VERSION 5.8 ;
BUSBITCHARS "[]" ;
DIVIDERCHAR "/" ;
CLEARANCEMEASURE EUCLIDEAN ;

SITE CoreSite
    SIZE 0.4800 BY 3.7800 ;
    CLASS CORE ;
    SYMMETRY Y ;
END CoreSite

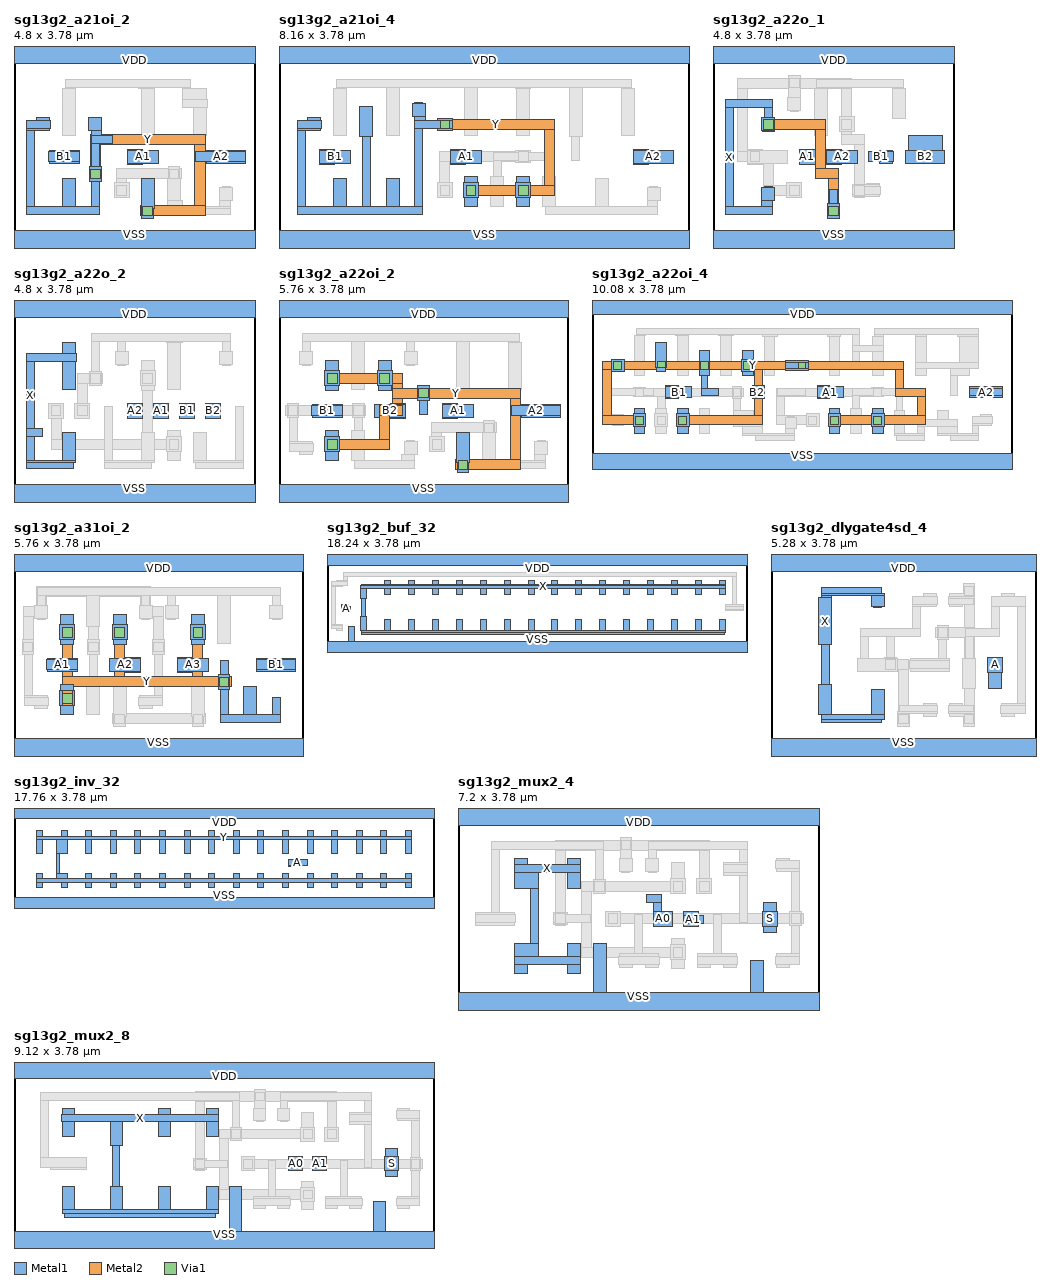
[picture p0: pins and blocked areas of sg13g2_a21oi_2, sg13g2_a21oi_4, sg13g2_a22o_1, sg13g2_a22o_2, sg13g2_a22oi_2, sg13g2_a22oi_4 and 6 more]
MACRO sg13g2_a21oi_2
  CLASS CORE ;
  ORIGIN 0 0 ;
  FOREIGN sg13g2_a21oi_2 0 0 ;
  SIZE 4.8000 BY 3.7800 ;
  SYMMETRY X Y ;
  SITE CoreSite ;
  PIN A1
    DIRECTION INPUT ;
    USE SIGNAL ;
    ANTENNAMODEL OXIDE1 ;
    ANTENNAGATEAREA 0.4836 LAYER Metal1 ;
    PORT
      LAYER Metal1 ;
        RECT 2.2500 1.5500 2.5500 1.5700 ;
        RECT 2.2500 1.5700 2.8700 1.8300 ;
        RECT 2.2500 1.8300 2.5500 1.8500 ;
    END
  END A1
  PIN A2
    DIRECTION INPUT ;
    USE SIGNAL ;
    ANTENNAMODEL OXIDE1 ;
    ANTENNAGATEAREA 0.4836 LAYER Metal1 ;
    PORT
      LAYER Metal1 ;
        RECT 3.8300 1.5700 4.6100 1.6050 ;
        RECT 3.6200 1.6050 4.6100 1.7950 ;
        RECT 3.8300 1.7950 4.6100 1.8300 ;
    END
  END A2
  PIN B1
    DIRECTION INPUT ;
    USE SIGNAL ;
    ANTENNAMODEL OXIDE1 ;
    ANTENNAGATEAREA 0.4836 LAYER Metal1 ;
    PORT
      LAYER Metal1 ;
        RECT 0.7100 1.5700 1.3100 1.6050 ;
        RECT 0.6950 1.6050 1.3100 1.7950 ;
        RECT 0.7100 1.7950 1.3100 1.8300 ;
    END
  END B1
  PIN Y
    DIRECTION OUTPUT ;
    USE SIGNAL ;
    ANTENNAPARTIALMETALAREA 0.19855 LAYER Metal1 ;
    ANTENNADIFFAREA 1.309 LAYER Metal1 ;
    ANTENNADIFFAREA 1.309 LAYER Metal2 ;
    PORT
      LAYER Metal2 ;
        RECT 2.5150 0.5200 3.8000 0.7200 ;
        RECT 1.5200 1.2100 1.7200 1.9450 ;
        RECT 3.6000 0.7200 3.8000 1.9450 ;
        RECT 1.5200 1.9450 3.8000 2.1450 ;
      LAYER Metal1 ;
        RECT 2.5450 0.4750 2.7750 0.6600 ;
        RECT 2.5300 0.6600 2.7900 1.2600 ;
        RECT 0.2400 0.5400 1.7000 0.7000 ;
        RECT 1.5400 0.7000 1.7000 1.2100 ;
        RECT 0.9700 0.7000 1.2300 1.2600 ;
        RECT 1.5050 1.2100 1.7350 1.5000 ;
        RECT 1.5400 1.5000 1.7000 1.9650 ;
        RECT 1.5400 1.9650 1.9600 2.1250 ;
        RECT 0.2400 0.7000 0.4000 2.2100 ;
        RECT 1.5400 2.1250 1.7500 2.2100 ;
        RECT 0.2400 2.2100 0.7100 2.2600 ;
        RECT 0.2400 2.2600 0.7250 2.4200 ;
        RECT 0.4500 2.4200 0.7100 2.4700 ;
        RECT 1.4900 2.2100 1.7500 2.4700 ;
        RECT 1.5400 2.4700 1.7000 2.4850 ;
      LAYER Via1 ;
        RECT 2.5650 0.5250 2.7550 0.7150 ;
        RECT 1.5250 1.2600 1.7150 1.4500 ;
    END
  END Y
  PIN VDD
    DIRECTION INOUT ;
    USE POWER ;
    SHAPE ABUTMENT ;
    PORT
      LAYER Metal1 ;
        RECT 0.0000 3.5600 4.8000 4.0000 ;
    END
  END VDD
  PIN VSS
    DIRECTION INOUT ;
    USE GROUND ;
    SHAPE ABUTMENT ;
    PORT
      LAYER Metal1 ;
        RECT 0.0000 -0.2200 4.8000 0.2200 ;
    END
  END VSS
  OBS
    LAYER Metal2 ;
      RECT 2.0400 0.8850 2.2400 1.2550 ;
      RECT 2.0400 1.2550 3.3250 1.4550 ;
    LAYER Metal1 ;
      RECT 1.9900 0.8800 2.2900 1.1800 ;
      RECT 3.1000 0.5400 4.3000 0.6600 ;
      RECT 3.0500 0.6600 4.3000 0.7000 ;
      RECT 3.0500 0.7000 3.3600 0.8300 ;
      RECT 4.0900 0.7000 4.3000 0.8300 ;
      RECT 4.0900 0.8300 4.3500 1.0900 ;
      RECT 4.1400 1.0900 4.3000 1.1050 ;
      RECT 3.0500 0.8300 3.3100 1.2600 ;
      RECT 3.0650 1.2600 3.2950 1.5000 ;
      RECT 3.5700 2.1100 3.8300 2.6700 ;
      RECT 3.3600 2.6700 3.8450 2.8300 ;
      RECT 0.9700 2.1100 1.2300 3.0500 ;
      RECT 2.5300 2.1100 2.7900 3.0500 ;
      RECT 3.3600 2.8300 3.8300 3.0500 ;
      RECT 1.0200 3.0500 1.2300 3.0800 ;
      RECT 2.4800 3.0500 2.7900 3.0800 ;
      RECT 3.3600 3.0500 3.5200 3.0800 ;
      RECT 1.0200 3.0800 3.5200 3.2400 ;
    LAYER Via1 ;
      RECT 2.0450 0.9350 2.2350 1.1250 ;
      RECT 3.0850 1.2600 3.2750 1.4500 ;
  END
END sg13g2_a21oi_2

MACRO sg13g2_a21oi_4
  CLASS CORE ;
  ORIGIN 0 0 ;
  FOREIGN sg13g2_a21oi_4 0 0 ;
  SIZE 8.1600 BY 3.7800 ;
  SYMMETRY X Y ;
  SITE CoreSite ;
  PIN A1
    DIRECTION INPUT ;
    USE SIGNAL ;
    ANTENNAMODEL OXIDE1 ;
    ANTENNAGATEAREA 0.9672 LAYER Metal1 ;
    PORT
      LAYER Metal1 ;
        RECT 3.4100 1.5500 3.7100 1.5700 ;
        RECT 3.4100 1.5700 4.0300 1.8300 ;
        RECT 3.4100 1.8300 3.7100 1.8500 ;
    END
  END A1
  PIN A2
    DIRECTION INPUT ;
    USE SIGNAL ;
    ANTENNAMODEL OXIDE1 ;
    ANTENNAGATEAREA 0.9672 LAYER Metal1 ;
    PORT
      LAYER Metal1 ;
        RECT 7.0500 1.5500 7.3500 1.5700 ;
        RECT 7.0500 1.5700 7.8500 1.8300 ;
        RECT 7.0500 1.8300 7.3500 1.8500 ;
    END
  END A2
  PIN B1
    DIRECTION INPUT ;
    USE SIGNAL ;
    ANTENNAMODEL OXIDE1 ;
    ANTENNAGATEAREA 0.9672 LAYER Metal1 ;
    PORT
      LAYER Metal1 ;
        RECT 0.8100 1.5500 1.1100 1.5700 ;
        RECT 0.8100 1.5700 1.4300 1.8300 ;
        RECT 0.8100 1.8300 1.1100 1.8500 ;
    END
  END B1
  PIN Y
    DIRECTION OUTPUT ;
    USE SIGNAL ;
    ANTENNAPARTIALMETALAREA 2.0692 LAYER Metal1 ;
    ANTENNADIFFAREA 2.323 LAYER Metal1 ;
    ANTENNADIFFAREA 2.323 LAYER Metal2 ;
    PORT
      LAYER Metal2 ;
        RECT 3.6750 0.9300 5.4800 1.1300 ;
        RECT 5.2800 1.1300 5.4800 2.2400 ;
        RECT 3.1550 2.2400 5.4800 2.4400 ;
      LAYER Metal1 ;
        RECT 3.6900 0.7100 3.9500 0.8800 ;
        RECT 3.6700 0.8800 3.9700 1.1800 ;
        RECT 3.6900 1.1800 3.9500 1.3100 ;
        RECT 4.7300 0.7100 4.9900 0.8800 ;
        RECT 4.7100 0.8800 5.0100 1.1800 ;
        RECT 4.7300 1.1800 4.9900 1.3100 ;
        RECT 0.3600 0.5400 2.8600 0.7000 ;
        RECT 1.0900 0.7000 1.3500 1.2600 ;
        RECT 2.1300 0.7000 2.3900 1.2600 ;
        RECT 1.6600 0.7000 1.8200 2.0900 ;
        RECT 0.3600 0.7000 0.5200 2.2100 ;
        RECT 0.3600 2.2100 0.8300 2.2600 ;
        RECT 2.7000 0.7000 2.8600 2.2600 ;
        RECT 3.1550 2.2250 3.4450 2.2600 ;
        RECT 0.3600 2.2600 0.8450 2.4200 ;
        RECT 2.7000 2.2600 3.4450 2.4200 ;
        RECT 3.1550 2.4200 3.4450 2.4550 ;
        RECT 0.5700 2.4200 0.8300 2.4700 ;
        RECT 2.7000 2.4200 2.9100 2.5000 ;
        RECT 1.6100 2.0900 1.8700 2.6900 ;
        RECT 2.6500 2.5000 2.9100 2.7600 ;
        RECT 2.7000 2.7600 2.8600 2.7750 ;
      LAYER Via1 ;
        RECT 3.7250 0.9350 3.9150 1.1250 ;
        RECT 4.7650 0.9350 4.9550 1.1250 ;
        RECT 3.2050 2.2450 3.3950 2.4350 ;
    END
  END Y
  PIN VDD
    DIRECTION INOUT ;
    USE POWER ;
    SHAPE ABUTMENT ;
    PORT
      LAYER Metal1 ;
        RECT 0.0000 3.5600 8.1600 4.0000 ;
    END
  END VDD
  PIN VSS
    DIRECTION INOUT ;
    USE GROUND ;
    SHAPE ABUTMENT ;
    PORT
      LAYER Metal1 ;
        RECT 0.0000 -0.2200 8.1600 0.2200 ;
    END
  END VSS
  OBS
    LAYER Metal2 ;
      RECT 3.2000 0.8850 3.4000 1.6000 ;
      RECT 3.2000 1.6000 5.0050 1.8000 ;
    LAYER Metal1 ;
      RECT 3.1500 0.8800 3.4500 1.1800 ;
      RECT 5.3000 0.5400 7.5400 0.7000 ;
      RECT 5.3000 0.7000 5.5100 0.7100 ;
      RECT 7.3300 0.7000 7.5400 0.8300 ;
      RECT 7.3300 0.8300 7.5900 1.0900 ;
      RECT 7.3800 1.0900 7.5400 1.1050 ;
      RECT 6.2900 0.7000 6.5500 1.2600 ;
      RECT 4.2100 0.7100 4.4700 1.3100 ;
      RECT 5.2500 0.7100 5.5100 1.3100 ;
      RECT 4.2600 1.3100 4.4200 1.6200 ;
      RECT 4.7150 1.5850 5.0050 1.6200 ;
      RECT 5.3000 1.3100 5.4600 1.6200 ;
      RECT 4.2600 1.6200 5.4600 1.7800 ;
      RECT 4.7150 1.7800 5.0050 1.8150 ;
      RECT 5.8200 1.6200 5.9800 2.0900 ;
      RECT 1.0900 2.1100 1.3500 3.0500 ;
      RECT 4.7300 2.1100 4.9900 3.0500 ;
      RECT 6.8100 2.1100 7.0700 3.0500 ;
      RECT 1.1400 3.0500 1.3500 3.0800 ;
      RECT 2.1300 2.1100 2.3900 3.0800 ;
      RECT 3.6900 2.1100 3.9500 3.0800 ;
      RECT 4.7150 3.0500 5.0050 3.0800 ;
      RECT 5.7700 2.0900 6.0300 3.0800 ;
      RECT 6.8100 3.0500 7.0200 3.0800 ;
      RECT 1.1400 3.0800 7.0200 3.2400 ;
    LAYER Via1 ;
      RECT 3.2050 0.9350 3.3950 1.1250 ;
      RECT 4.7650 1.6050 4.9550 1.7950 ;
  END
END sg13g2_a21oi_4

MACRO sg13g2_a22o_1
  CLASS CORE ;
  ORIGIN 0 0 ;
  FOREIGN sg13g2_a22o_1 0 0 ;
  SIZE 4.8000 BY 3.7800 ;
  SYMMETRY X Y ;
  SITE CoreSite ;
  PIN A1
    DIRECTION INPUT ;
    USE SIGNAL ;
    ANTENNAMODEL OXIDE1 ;
    ANTENNAGATEAREA 0.2418 LAYER Metal1 ;
    PORT
      LAYER Metal1 ;
        RECT 1.7300 1.5500 2.0300 1.8500 ;
    END
  END A1
  PIN A2
    DIRECTION INPUT ;
    USE SIGNAL ;
    ANTENNAMODEL OXIDE1 ;
    ANTENNAGATEAREA 0.2418 LAYER Metal1 ;
    PORT
      LAYER Metal1 ;
        RECT 2.2500 1.5500 2.5500 1.5700 ;
        RECT 2.2500 1.5700 2.8700 1.8300 ;
        RECT 2.2500 1.8300 2.5500 1.8500 ;
    END
  END A2
  PIN B1
    DIRECTION INPUT ;
    USE SIGNAL ;
    ANTENNAMODEL OXIDE1 ;
    ANTENNAGATEAREA 0.2418 LAYER Metal1 ;
    PORT
      LAYER Metal1 ;
        RECT 3.3100 1.5700 3.5700 1.6050 ;
        RECT 3.1000 1.6050 3.5850 1.7950 ;
        RECT 3.3100 1.7950 3.5700 1.8300 ;
    END
  END B1
  PIN B2
    DIRECTION INPUT ;
    USE SIGNAL ;
    ANTENNAMODEL OXIDE1 ;
    ANTENNAGATEAREA 0.2418 LAYER Metal1 ;
    PORT
      LAYER Metal1 ;
        RECT 3.8800 1.5550 4.0400 1.5700 ;
        RECT 3.8300 1.5700 4.6100 1.8300 ;
        RECT 3.8800 1.8300 4.5600 2.1250 ;
    END
  END B2
  PIN X
    DIRECTION OUTPUT ;
    USE SIGNAL ;
    ANTENNAPARTIALMETALAREA 0.8174 LAYER Metal1 ;
    ANTENNADIFFAREA 0.6102 LAYER Metal1 ;
    ANTENNADIFFAREA 0.6102 LAYER Metal2 ;
    PORT
      LAYER Metal2 ;
        RECT 2.3000 0.4750 2.5000 1.2550 ;
        RECT 2.0400 1.2550 2.5000 1.4550 ;
        RECT 2.0400 1.4550 2.2400 2.2400 ;
        RECT 0.9550 2.2400 2.2400 2.4400 ;
      LAYER Metal1 ;
        RECT 2.2850 0.4750 2.5150 0.7650 ;
        RECT 2.3200 0.7650 2.4800 1.0400 ;
        RECT 0.2400 0.5400 1.1800 0.7000 ;
        RECT 0.9700 0.7000 1.1800 0.8300 ;
        RECT 0.9700 0.8300 1.2300 1.0900 ;
        RECT 1.0200 1.0900 1.1800 1.1050 ;
        RECT 0.9850 2.1950 1.2150 2.2100 ;
        RECT 0.9700 2.2100 1.2300 2.4700 ;
        RECT 0.9850 2.4700 1.2150 2.4850 ;
        RECT 0.2400 0.7000 0.4000 2.6700 ;
        RECT 1.0200 2.4850 1.1800 2.6700 ;
        RECT 0.2400 2.6700 1.1800 2.8300 ;
      LAYER Via1 ;
        RECT 2.3050 0.5250 2.4950 0.7150 ;
        RECT 1.0050 2.2450 1.1950 2.4350 ;
    END
  END X
  PIN VDD
    DIRECTION INOUT ;
    USE POWER ;
    SHAPE ABUTMENT ;
    PORT
      LAYER Metal1 ;
        RECT 0.0000 3.5600 4.8000 4.0000 ;
    END
  END VDD
  PIN VSS
    DIRECTION INOUT ;
    USE GROUND ;
    SHAPE ABUTMENT ;
    PORT
      LAYER Metal1 ;
        RECT 0.0000 -0.2200 4.8000 0.2200 ;
    END
  END VSS
  OBS
    LAYER Metal2 ;
      RECT 1.0000 0.9300 1.7650 1.1300 ;
      RECT 1.0000 1.1300 1.2000 1.6000 ;
      RECT 0.4800 1.6000 1.2000 1.8000 ;
      RECT 2.8200 0.8850 3.0200 1.9450 ;
      RECT 2.5600 1.9450 3.0200 2.1450 ;
      RECT 0.4800 1.8000 0.6800 3.0600 ;
      RECT 2.5600 2.1450 2.7600 3.0600 ;
      RECT 0.4800 3.0600 2.7600 3.2600 ;
    LAYER Metal1 ;
      RECT 3.0500 0.9000 3.3100 0.9150 ;
      RECT 2.7750 0.9150 3.3100 0.9500 ;
      RECT 2.7750 0.9500 3.3250 1.1100 ;
      RECT 2.7750 1.1100 3.3100 1.1450 ;
      RECT 3.0500 1.1450 3.3100 1.1600 ;
      RECT 1.4700 0.8800 1.7700 1.1800 ;
      RECT 0.6900 1.5500 0.9900 1.5700 ;
      RECT 0.6900 1.5700 1.4900 1.8300 ;
      RECT 0.6900 1.8300 0.9900 1.8500 ;
      RECT 2.5100 2.1900 2.8100 2.4900 ;
      RECT 1.5400 2.6050 1.7000 2.6200 ;
      RECT 1.4900 2.6200 1.7500 2.8800 ;
      RECT 1.5050 2.8800 1.7350 3.3050 ;
      RECT 2.0100 2.1100 2.2700 3.0500 ;
      RECT 3.5700 2.4500 3.8300 3.0500 ;
      RECT 2.0600 3.0500 2.3200 3.0800 ;
      RECT 3.5700 3.0500 3.7800 3.0800 ;
      RECT 2.0600 3.0800 3.7800 3.2400 ;
    LAYER Via1 ;
      RECT 1.5250 0.9350 1.7150 1.1250 ;
      RECT 2.8250 0.9350 3.0150 1.1250 ;
      RECT 0.7450 1.6050 0.9350 1.7950 ;
      RECT 2.5650 2.2450 2.7550 2.4350 ;
      RECT 1.5250 3.0650 1.7150 3.2550 ;
  END
END sg13g2_a22o_1

MACRO sg13g2_a22o_2
  CLASS CORE ;
  ORIGIN 0 0 ;
  FOREIGN sg13g2_a22o_2 0 0 ;
  SIZE 4.8000 BY 3.7800 ;
  SYMMETRY X Y ;
  SITE CoreSite ;
  PIN A1
    DIRECTION INPUT ;
    USE SIGNAL ;
    ANTENNAMODEL OXIDE1 ;
    ANTENNAGATEAREA 0.2418 LAYER Metal1 ;
    PORT
      LAYER Metal1 ;
        RECT 2.7700 1.5500 3.0700 1.8500 ;
    END
  END A1
  PIN A2
    DIRECTION INPUT ;
    USE SIGNAL ;
    ANTENNAMODEL OXIDE1 ;
    ANTENNAGATEAREA 0.2418 LAYER Metal1 ;
    PORT
      LAYER Metal1 ;
        RECT 2.2500 1.5500 2.5500 1.8500 ;
    END
  END A2
  PIN B1
    DIRECTION INPUT ;
    USE SIGNAL ;
    ANTENNAMODEL OXIDE1 ;
    ANTENNAGATEAREA 0.2418 LAYER Metal1 ;
    PORT
      LAYER Metal1 ;
        RECT 3.2900 1.5500 3.5900 1.8500 ;
    END
  END B1
  PIN B2
    DIRECTION INPUT ;
    USE SIGNAL ;
    ANTENNAMODEL OXIDE1 ;
    ANTENNAGATEAREA 0.2418 LAYER Metal1 ;
    PORT
      LAYER Metal1 ;
        RECT 3.8100 1.5500 4.1100 1.8500 ;
    END
  END B2
  PIN X
    DIRECTION OUTPUT ;
    USE SIGNAL ;
    ANTENNADIFFAREA 0.7254 LAYER Metal1 ;
    PORT
      LAYER Metal1 ;
        RECT 0.2400 0.5400 1.1800 0.6600 ;
        RECT 0.2400 0.6600 1.2300 0.7000 ;
        RECT 0.2400 0.7000 0.4000 1.1800 ;
        RECT 0.9700 0.7000 1.2300 1.2600 ;
        RECT 0.2400 1.1800 0.5600 1.3400 ;
        RECT 0.2400 1.3400 0.4000 2.6700 ;
        RECT 0.9700 2.1100 1.2300 2.6700 ;
        RECT 0.2400 2.6700 1.2450 2.8300 ;
        RECT 0.9700 2.8300 1.2300 3.0500 ;
    END
  END X
  PIN VDD
    DIRECTION INOUT ;
    USE POWER ;
    SHAPE ABUTMENT ;
    PORT
      LAYER Metal1 ;
        RECT 0.0000 3.5600 4.8000 4.0000 ;
    END
  END VDD
  PIN VSS
    DIRECTION INOUT ;
    USE GROUND ;
    SHAPE ABUTMENT ;
    PORT
      LAYER Metal1 ;
        RECT 0.0000 -0.2200 4.8000 0.2200 ;
    END
  END VSS
  OBS
    LAYER Metal2 ;
      RECT 0.7400 0.9300 3.3250 1.1300 ;
      RECT 0.7400 1.1300 0.9400 1.8450 ;
      RECT 2.5600 1.1300 2.7600 2.4850 ;
      RECT 1.2600 1.5550 1.4600 2.2400 ;
      RECT 1.2600 2.2400 1.7650 2.4400 ;
    LAYER Metal1 ;
      RECT 3.0500 0.7100 3.3100 0.8800 ;
      RECT 3.0300 0.8800 3.3300 1.1800 ;
      RECT 3.0500 1.1800 3.3100 1.3100 ;
      RECT 0.6900 1.5500 0.9900 1.8500 ;
      RECT 2.5300 2.0900 2.7900 2.1900 ;
      RECT 2.5100 2.1900 2.8100 2.4900 ;
      RECT 2.5300 2.4900 2.7900 2.6900 ;
      RECT 1.8000 0.5400 2.7400 0.6600 ;
      RECT 1.8000 0.6600 2.7900 0.7000 ;
      RECT 2.5300 0.7000 2.7900 1.2600 ;
      RECT 1.8000 0.7000 1.9600 1.7800 ;
      RECT 3.6200 0.5400 4.5600 0.6600 ;
      RECT 3.5700 0.6600 4.5600 0.7000 ;
      RECT 3.5700 0.7000 3.8300 1.2600 ;
      RECT 4.4000 0.7000 4.5600 1.7800 ;
      RECT 1.2100 1.5500 1.5100 1.8500 ;
      RECT 1.5050 2.1950 1.7350 2.4850 ;
      RECT 2.0600 2.6050 2.2200 2.6200 ;
      RECT 4.1400 2.6050 4.3000 2.6200 ;
      RECT 2.0100 2.6200 2.2700 2.8800 ;
      RECT 4.0900 2.6200 4.3500 2.8800 ;
      RECT 3.0500 2.1100 3.3100 3.0500 ;
      RECT 1.5400 2.4850 1.7000 3.0800 ;
      RECT 2.0600 2.8800 2.2200 3.0800 ;
      RECT 3.0350 3.0500 3.3600 3.0800 ;
      RECT 4.1400 2.8800 4.3000 3.0800 ;
      RECT 1.5400 3.0800 4.3000 3.2400 ;
    LAYER Via1 ;
      RECT 3.0850 0.9350 3.2750 1.1250 ;
      RECT 0.7450 1.6050 0.9350 1.7950 ;
      RECT 2.5650 2.2450 2.7550 2.4350 ;
      RECT 1.2650 1.6050 1.4550 1.7950 ;
      RECT 1.5250 2.2450 1.7150 2.4350 ;
  END
END sg13g2_a22o_2

MACRO sg13g2_a22oi_2
  CLASS CORE ;
  ORIGIN 0 0 ;
  FOREIGN sg13g2_a22oi_2 0 0 ;
  SIZE 5.7600 BY 3.7800 ;
  SYMMETRY X Y ;
  SITE CoreSite ;
  PIN A1
    DIRECTION INPUT ;
    USE SIGNAL ;
    ANTENNAMODEL OXIDE1 ;
    ANTENNAGATEAREA 0.4836 LAYER Metal1 ;
    PORT
      LAYER Metal1 ;
        RECT 3.2500 1.5500 3.5500 1.5700 ;
        RECT 3.2500 1.5700 3.8700 1.8300 ;
        RECT 3.2500 1.8300 3.5500 1.8500 ;
    END
  END A1
  PIN A2
    DIRECTION INPUT ;
    USE SIGNAL ;
    ANTENNAMODEL OXIDE1 ;
    ANTENNAGATEAREA 0.4836 LAYER Metal1 ;
    PORT
      LAYER Metal1 ;
        RECT 4.8300 1.5700 5.6100 1.6050 ;
        RECT 4.6200 1.6050 5.6100 1.7950 ;
        RECT 4.8300 1.7950 5.6100 1.8300 ;
    END
  END A2
  PIN B1
    DIRECTION INPUT ;
    USE SIGNAL ;
    ANTENNAMODEL OXIDE1 ;
    ANTENNAGATEAREA 0.4836 LAYER Metal1 ;
    PORT
      LAYER Metal1 ;
        RECT 0.6700 1.5700 1.2700 1.6050 ;
        RECT 0.6550 1.6050 1.2700 1.7950 ;
        RECT 0.6700 1.7950 1.2700 1.8300 ;
    END
  END B1
  PIN B2
    DIRECTION INPUT ;
    USE SIGNAL ;
    ANTENNAMODEL OXIDE1 ;
    ANTENNAGATEAREA 0.4836 LAYER Metal1 ;
    PORT
      LAYER Metal1 ;
        RECT 2.2100 1.5500 2.5100 1.5700 ;
        RECT 1.8900 1.5700 2.5100 1.8300 ;
        RECT 2.2100 1.8300 2.5100 1.8500 ;
    END
  END B2
  PIN Y
    DIRECTION OUTPUT ;
    USE SIGNAL ;
    ANTENNAPARTIALMETALAREA 0.70255 LAYER Metal1 ;
    ANTENNADIFFAREA 1.4508 LAYER Metal1 ;
    ANTENNADIFFAREA 1.4508 LAYER Metal2 ;
    PORT
      LAYER Metal2 ;
        RECT 3.5150 0.5200 4.8000 0.7200 ;
        RECT 0.9150 0.9300 2.2000 1.1300 ;
        RECT 2.0000 1.1300 2.2000 1.6000 ;
        RECT 2.0000 1.6000 2.4600 1.8000 ;
        RECT 2.2600 1.8000 2.4600 1.9450 ;
        RECT 4.6000 0.7200 4.8000 1.9450 ;
        RECT 2.2600 1.9450 4.8000 2.1450 ;
        RECT 2.2600 2.1450 2.4600 2.2400 ;
        RECT 0.9150 2.2400 2.4600 2.4400 ;
      LAYER Metal1 ;
        RECT 3.5450 0.4750 3.7750 0.6600 ;
        RECT 3.5300 0.6600 3.7900 1.2600 ;
        RECT 0.9300 0.7100 1.1900 0.8800 ;
        RECT 0.9100 0.8800 1.2100 1.1800 ;
        RECT 0.9300 1.1800 1.1900 1.3100 ;
        RECT 2.8000 1.6200 2.9600 1.9000 ;
        RECT 2.7650 1.9000 2.9950 2.1900 ;
        RECT 0.9300 2.0900 1.1900 2.1900 ;
        RECT 0.9100 2.1900 1.2100 2.4900 ;
        RECT 0.9300 2.4900 1.1900 2.6900 ;
        RECT 1.9700 2.0900 2.2300 2.1900 ;
        RECT 1.9500 2.1900 2.2500 2.4900 ;
        RECT 1.9700 2.4900 2.2300 2.6900 ;
      LAYER Via1 ;
        RECT 3.5650 0.5250 3.7550 0.7150 ;
        RECT 0.9650 0.9350 1.1550 1.1250 ;
        RECT 2.7850 1.9500 2.9750 2.1400 ;
        RECT 0.9650 2.2450 1.1550 2.4350 ;
        RECT 2.0050 2.2450 2.1950 2.4350 ;
    END
  END Y
  PIN VDD
    DIRECTION INOUT ;
    USE POWER ;
    SHAPE ABUTMENT ;
    PORT
      LAYER Metal1 ;
        RECT 0.0000 3.5600 5.7600 4.0000 ;
    END
  END VDD
  PIN VSS
    DIRECTION INOUT ;
    USE GROUND ;
    SHAPE ABUTMENT ;
    PORT
      LAYER Metal1 ;
        RECT 0.0000 -0.2200 5.7600 0.2200 ;
    END
  END VSS
  OBS
    LAYER Metal2 ;
      RECT 0.1350 1.6000 1.7250 1.8000 ;
      RECT 3.0400 0.8850 3.2400 1.2550 ;
      RECT 3.0400 1.2550 4.3250 1.4550 ;
    LAYER Metal1 ;
      RECT 0.4100 0.8300 0.6700 0.8800 ;
      RECT 0.2000 0.8800 0.6850 1.0400 ;
      RECT 0.2000 1.0400 0.6700 1.0900 ;
      RECT 0.2000 1.0900 0.3600 1.5550 ;
      RECT 0.1650 1.5550 0.3950 1.8450 ;
      RECT 1.5000 0.5400 2.7000 0.7000 ;
      RECT 1.5000 0.7000 1.7100 0.7100 ;
      RECT 2.4400 0.7000 2.7000 0.8300 ;
      RECT 2.4900 0.8300 2.7500 1.0900 ;
      RECT 2.5400 1.0900 2.7000 1.1050 ;
      RECT 1.4500 0.7100 1.7100 1.3100 ;
      RECT 1.5000 1.3100 1.6600 1.5550 ;
      RECT 1.4650 1.5550 1.6950 1.8450 ;
      RECT 2.9900 0.8800 3.2900 1.1800 ;
      RECT 4.1000 0.5400 5.3000 0.6600 ;
      RECT 4.0500 0.6600 5.3000 0.7000 ;
      RECT 5.0900 0.7000 5.3000 0.8300 ;
      RECT 5.0900 0.8300 5.3500 1.0900 ;
      RECT 5.1400 1.0900 5.3000 1.1050 ;
      RECT 4.0500 0.7000 4.3100 1.2600 ;
      RECT 4.0650 1.2600 4.2950 1.5000 ;
      RECT 0.4600 2.6050 0.6200 2.6200 ;
      RECT 2.5400 2.6050 2.7000 2.6200 ;
      RECT 0.4100 2.6200 0.6700 2.8800 ;
      RECT 2.4900 2.6200 2.7500 2.8800 ;
      RECT 4.5700 2.1100 4.8300 3.0500 ;
      RECT 0.4600 2.8800 0.6200 3.0800 ;
      RECT 1.4500 2.1100 1.7100 3.0800 ;
      RECT 2.5400 2.8800 2.7000 3.0800 ;
      RECT 3.5300 2.1100 3.7900 3.0800 ;
      RECT 4.5700 3.0500 4.7800 3.0800 ;
      RECT 0.4600 3.0800 4.7800 3.2400 ;
    LAYER Via1 ;
      RECT 0.1850 1.6050 0.3750 1.7950 ;
      RECT 1.4850 1.6050 1.6750 1.7950 ;
      RECT 3.0450 0.9350 3.2350 1.1250 ;
      RECT 4.0850 1.2600 4.2750 1.4500 ;
  END
END sg13g2_a22oi_2

MACRO sg13g2_a22oi_4
  CLASS CORE ;
  ORIGIN 0 0 ;
  FOREIGN sg13g2_a22oi_4 0 0 ;
  SIZE 10.0800 BY 3.7800 ;
  SYMMETRY X Y ;
  SITE CoreSite ;
  PIN A1
    DIRECTION INPUT ;
    USE SIGNAL ;
    ANTENNAMODEL OXIDE1 ;
    ANTENNAGATEAREA 0.9672 LAYER Metal1 ;
    PORT
      LAYER Metal1 ;
        RECT 5.4100 1.5500 5.7100 1.5700 ;
        RECT 5.4100 1.5700 6.0300 1.8300 ;
        RECT 5.4100 1.8300 5.7100 1.8500 ;
    END
  END A1
  PIN A2
    DIRECTION INPUT ;
    USE SIGNAL ;
    ANTENNAMODEL OXIDE1 ;
    ANTENNAGATEAREA 0.9672 LAYER Metal1 ;
    PORT
      LAYER Metal1 ;
        RECT 9.0700 1.5700 9.8500 1.6200 ;
        RECT 9.0550 1.6200 9.8500 1.7800 ;
        RECT 9.0700 1.7800 9.8500 1.8300 ;
    END
  END A2
  PIN B1
    DIRECTION INPUT ;
    USE SIGNAL ;
    ANTENNAMODEL OXIDE1 ;
    ANTENNAGATEAREA 0.9672 LAYER Metal1 ;
    PORT
      LAYER Metal1 ;
        RECT 1.7700 1.5500 2.0700 1.5700 ;
        RECT 1.7700 1.5700 2.3900 1.8300 ;
        RECT 1.7700 1.8300 2.0700 1.8500 ;
    END
  END B1
  PIN B2
    DIRECTION INPUT ;
    USE SIGNAL ;
    ANTENNAMODEL OXIDE1 ;
    ANTENNAGATEAREA 0.9672 LAYER Metal1 ;
    PORT
      LAYER Metal1 ;
        RECT 3.8500 1.5500 4.1500 1.6200 ;
        RECT 3.7800 1.6200 4.1500 1.7800 ;
        RECT 3.8500 1.7800 4.1500 1.8500 ;
    END
  END B2
  PIN Y
    DIRECTION OUTPUT ;
    USE SIGNAL ;
    ANTENNAPARTIALMETALAREA 1.2434 LAYER Metal1 ;
    ANTENNADIFFAREA 3.1966 LAYER Metal1 ;
    ANTENNADIFFAREA 3.1966 LAYER Metal2 ;
    PORT
      LAYER Metal2 ;
        RECT 0.2600 0.9300 1.2850 1.1300 ;
        RECT 2.0350 0.9300 4.1000 1.1300 ;
        RECT 5.6750 0.9300 8.0000 1.1300 ;
        RECT 7.8000 1.1300 8.0000 1.6000 ;
        RECT 7.2800 1.6000 8.0000 1.8000 ;
        RECT 0.2600 1.1300 0.4600 2.2400 ;
        RECT 3.9000 1.1300 4.1000 2.2400 ;
        RECT 7.2800 1.8000 7.4800 2.2400 ;
        RECT 0.2600 2.2400 7.4800 2.4400 ;
      LAYER Metal1 ;
        RECT 1.0100 0.7100 1.2700 0.8800 ;
        RECT 0.9900 0.8800 1.2900 1.1800 ;
        RECT 1.0100 1.1800 1.2700 1.3100 ;
        RECT 2.0500 0.7100 2.3100 0.8800 ;
        RECT 2.0300 0.8800 2.3300 1.1800 ;
        RECT 2.0500 1.1800 2.3100 1.3100 ;
        RECT 5.6900 0.7100 5.9500 0.8800 ;
        RECT 5.6700 0.8800 5.9700 1.1800 ;
        RECT 5.6900 1.1800 5.9500 1.3100 ;
        RECT 6.7300 0.7100 6.9900 0.8800 ;
        RECT 6.7100 0.8800 7.0100 1.1800 ;
        RECT 6.7300 1.1800 6.9900 1.3100 ;
        RECT 4.6500 2.2100 4.9100 2.2250 ;
        RECT 4.6500 2.2250 5.1850 2.2600 ;
        RECT 4.6350 2.2600 5.1850 2.4200 ;
        RECT 4.6500 2.4200 5.1850 2.4550 ;
        RECT 4.6500 2.4550 4.9100 2.4700 ;
        RECT 0.4700 2.1900 0.7700 2.4900 ;
        RECT 2.6200 1.6200 3.0400 1.7800 ;
        RECT 2.6200 1.7800 2.7800 2.0900 ;
        RECT 2.5700 2.0900 2.8300 2.6900 ;
        RECT 3.6100 2.0900 3.8700 2.1900 ;
        RECT 3.5900 2.1900 3.8900 2.4900 ;
        RECT 3.6100 2.4900 3.8700 2.6900 ;
        RECT 1.5450 2.1950 1.7750 2.3000 ;
        RECT 1.5300 2.3000 1.7900 2.9000 ;
      LAYER Via1 ;
        RECT 1.0450 0.9350 1.2350 1.1250 ;
        RECT 2.0850 0.9350 2.2750 1.1250 ;
        RECT 5.7250 0.9350 5.9150 1.1250 ;
        RECT 6.7650 0.9350 6.9550 1.1250 ;
        RECT 0.5250 2.2450 0.7150 2.4350 ;
        RECT 1.5650 2.2450 1.7550 2.4350 ;
        RECT 2.6050 2.2450 2.7950 2.4350 ;
        RECT 3.6450 2.2450 3.8350 2.4350 ;
        RECT 4.9450 2.2450 5.1350 2.4350 ;
    END
  END Y
  PIN VDD
    DIRECTION INOUT ;
    USE POWER ;
    SHAPE ABUTMENT ;
    PORT
      LAYER Metal1 ;
        RECT 0.0000 3.5600 10.0800 4.0000 ;
    END
  END VDD
  PIN VSS
    DIRECTION INOUT ;
    USE GROUND ;
    SHAPE ABUTMENT ;
    PORT
      LAYER Metal1 ;
        RECT 0.0000 -0.2200 10.0800 0.2200 ;
    END
  END VSS
  OBS
    LAYER Metal2 ;
      RECT 4.4200 0.9300 5.4450 1.1300 ;
      RECT 4.4200 1.1300 4.6200 1.6000 ;
      RECT 4.4200 1.6000 7.0050 1.8000 ;
      RECT 1.5600 0.8850 1.7600 1.6000 ;
      RECT 0.9950 1.6000 3.6250 1.8000 ;
    LAYER Metal1 ;
      RECT 5.1500 0.8800 5.4500 1.1800 ;
      RECT 7.3000 0.5400 7.9800 0.6600 ;
      RECT 8.6000 0.5400 9.2800 0.6600 ;
      RECT 7.2500 0.6600 7.9800 0.7000 ;
      RECT 8.2900 0.6600 9.2800 0.7000 ;
      RECT 7.8200 0.7000 7.9800 0.8800 ;
      RECT 8.2900 0.7000 8.7600 0.8800 ;
      RECT 9.1200 0.7000 9.2800 0.9000 ;
      RECT 9.1200 0.9000 9.5900 0.9500 ;
      RECT 7.8200 0.8800 8.7600 1.0400 ;
      RECT 9.1200 0.9500 9.6050 1.1100 ;
      RECT 9.3300 1.1100 9.5900 1.1600 ;
      RECT 7.2500 0.7000 7.5100 1.2600 ;
      RECT 8.2900 1.0400 8.5500 1.2600 ;
      RECT 6.2100 0.7100 6.4700 1.3100 ;
      RECT 6.2600 1.3100 6.4200 1.6200 ;
      RECT 6.7150 1.5850 7.0050 1.6200 ;
      RECT 7.3000 1.2600 7.4600 1.6200 ;
      RECT 6.2600 1.6200 7.4600 1.7800 ;
      RECT 6.7150 1.7800 7.0050 1.8150 ;
      RECT 1.5300 0.7100 1.7900 0.8800 ;
      RECT 1.5100 0.8800 1.8100 1.1800 ;
      RECT 1.5300 1.1800 1.7900 1.3100 ;
      RECT 0.4900 0.9000 0.7500 0.9500 ;
      RECT 0.2800 0.9500 0.7650 1.1100 ;
      RECT 0.2800 1.1100 0.7500 1.1600 ;
      RECT 0.2800 1.1600 0.4400 1.6200 ;
      RECT 0.9950 1.5850 1.2850 1.6200 ;
      RECT 0.2800 1.6200 1.4800 1.7800 ;
      RECT 0.9950 1.7800 1.2850 1.8150 ;
      RECT 3.9200 0.5400 4.8600 0.6600 ;
      RECT 3.6100 0.6600 4.8600 0.7000 ;
      RECT 4.6350 0.7000 4.8600 0.8300 ;
      RECT 3.6100 0.7000 4.0800 0.8800 ;
      RECT 2.5700 0.7100 2.8300 0.9500 ;
      RECT 3.4000 0.8800 4.0800 0.9500 ;
      RECT 2.5550 0.9500 4.0800 1.0400 ;
      RECT 4.6500 0.8300 4.9100 1.0900 ;
      RECT 4.7000 1.0900 4.8600 1.1050 ;
      RECT 2.5550 1.0400 3.8700 1.1100 ;
      RECT 3.4000 1.1100 3.8700 1.2600 ;
      RECT 2.5700 1.1100 2.8300 1.3100 ;
      RECT 3.4000 1.2600 3.5600 1.5550 ;
      RECT 3.3650 1.5550 3.5950 1.8450 ;
      RECT 4.4400 1.6200 5.1200 1.7800 ;
      RECT 8.6000 1.6200 8.7600 2.0900 ;
      RECT 5.6900 2.0900 5.9500 2.2600 ;
      RECT 7.7700 2.0900 8.0300 2.2600 ;
      RECT 8.6000 2.0900 9.0700 2.2600 ;
      RECT 5.6750 2.2600 6.4200 2.4200 ;
      RECT 7.7550 2.2600 9.2800 2.4200 ;
      RECT 6.2600 2.4200 6.4200 2.6700 ;
      RECT 6.7300 2.0900 6.9900 2.6700 ;
      RECT 6.2600 2.6700 6.9900 2.8300 ;
      RECT 4.1300 2.0900 4.3900 3.0300 ;
      RECT 5.6900 2.4200 5.9500 3.0300 ;
      RECT 6.7300 2.8300 6.9900 3.0300 ;
      RECT 7.7700 2.4200 8.0300 3.0300 ;
      RECT 8.8100 2.4200 9.2800 3.0300 ;
      RECT 1.0100 2.1100 1.2700 3.0500 ;
      RECT 2.0500 2.1100 2.3100 3.0500 ;
      RECT 3.0900 2.1100 3.3500 3.0500 ;
      RECT 1.0600 3.0500 1.2850 3.0800 ;
      RECT 2.0000 3.0500 2.3250 3.0800 ;
      RECT 3.0400 3.0500 3.4000 3.0800 ;
      RECT 4.0800 3.0300 4.4400 3.0800 ;
      RECT 5.6400 3.0300 5.9650 3.0800 ;
      RECT 6.2600 2.8300 6.4200 3.0800 ;
      RECT 6.7800 3.0300 7.0050 3.0800 ;
      RECT 7.7550 3.0300 8.0300 3.0800 ;
      RECT 8.7600 3.0300 9.2800 3.0800 ;
      RECT 1.0600 3.0800 6.4200 3.2400 ;
      RECT 6.7800 3.0800 9.2800 3.2400 ;
    LAYER Via1 ;
      RECT 5.2050 0.9350 5.3950 1.1250 ;
      RECT 6.7650 1.6050 6.9550 1.7950 ;
      RECT 1.5650 0.9350 1.7550 1.1250 ;
      RECT 1.0450 1.6050 1.2350 1.7950 ;
      RECT 3.3850 1.6050 3.5750 1.7950 ;
  END
END sg13g2_a22oi_4

MACRO sg13g2_a31oi_2
  CLASS CORE ;
  ORIGIN 0 0 ;
  FOREIGN sg13g2_a31oi_2 0 0 ;
  SIZE 5.7600 BY 3.7800 ;
  SYMMETRY X Y ;
  SITE CoreSite ;
  PIN A1
    DIRECTION INPUT ;
    USE SIGNAL ;
    ANTENNAMODEL OXIDE1 ;
    ANTENNAGATEAREA 0.4836 LAYER Metal1 ;
    PORT
      LAYER Metal1 ;
        RECT 0.6700 1.5700 1.2700 1.6050 ;
        RECT 0.6550 1.6050 1.2700 1.7950 ;
        RECT 0.6700 1.7950 1.2700 1.8300 ;
    END
  END A1
  PIN A2
    DIRECTION INPUT ;
    USE SIGNAL ;
    ANTENNAMODEL OXIDE1 ;
    ANTENNAGATEAREA 0.4836 LAYER Metal1 ;
    PORT
      LAYER Metal1 ;
        RECT 2.2100 1.5500 2.5100 1.5700 ;
        RECT 1.8900 1.5700 2.5100 1.8300 ;
        RECT 2.2100 1.8300 2.5100 1.8500 ;
    END
  END A2
  PIN A3
    DIRECTION INPUT ;
    USE SIGNAL ;
    ANTENNAMODEL OXIDE1 ;
    ANTENNAGATEAREA 0.4836 LAYER Metal1 ;
    PORT
      LAYER Metal1 ;
        RECT 3.2500 1.5500 3.5500 1.5700 ;
        RECT 3.2500 1.5700 3.8700 1.8300 ;
        RECT 3.2500 1.8300 3.5500 1.8500 ;
    END
  END A3
  PIN B1
    DIRECTION INPUT ;
    USE SIGNAL ;
    ANTENNAMODEL OXIDE1 ;
    ANTENNAGATEAREA 0.4836 LAYER Metal1 ;
    PORT
      LAYER Metal1 ;
        RECT 4.8300 1.5700 5.6100 1.6050 ;
        RECT 4.8150 1.6050 5.6100 1.7950 ;
        RECT 4.8300 1.7950 5.6100 1.8300 ;
    END
  END B1
  PIN Y
    DIRECTION OUTPUT ;
    USE SIGNAL ;
    ANTENNAPARTIALMETALAREA 0.672 LAYER Metal1 ;
    ANTENNADIFFAREA 1.8876 LAYER Metal1 ;
    ANTENNADIFFAREA 1.8876 LAYER Metal2 ;
    PORT
      LAYER Metal2 ;
        RECT 0.9600 0.8850 1.1600 1.2550 ;
        RECT 0.9600 1.2550 4.3250 1.4550 ;
        RECT 0.9600 1.4550 1.1600 2.4850 ;
        RECT 2.0000 1.4550 2.2000 2.4850 ;
        RECT 3.5600 1.4550 3.7600 2.4850 ;
      LAYER Metal1 ;
        RECT 0.9300 0.7100 1.1900 0.8800 ;
        RECT 0.9100 0.8800 1.2100 1.1800 ;
        RECT 0.9300 1.1800 1.1900 1.3100 ;
        RECT 4.1000 0.5400 5.3000 0.7000 ;
        RECT 5.1400 0.7000 5.3000 1.0400 ;
        RECT 4.1000 0.7000 4.2600 1.2100 ;
        RECT 4.5700 0.7000 4.8300 1.2600 ;
        RECT 4.0650 1.2100 4.2950 1.5000 ;
        RECT 4.1000 1.5000 4.2600 1.7800 ;
        RECT 0.9300 2.0900 1.1900 2.1900 ;
        RECT 0.9100 2.1900 1.2100 2.4900 ;
        RECT 0.9300 2.4900 1.1900 2.6900 ;
        RECT 1.9700 2.0900 2.2300 2.1900 ;
        RECT 1.9500 2.1900 2.2500 2.4900 ;
        RECT 1.9700 2.4900 2.2300 2.6900 ;
        RECT 3.5300 2.0900 3.7900 2.1900 ;
        RECT 3.5100 2.1900 3.8100 2.4900 ;
        RECT 3.5300 2.4900 3.7900 2.6900 ;
      LAYER Via1 ;
        RECT 0.9650 0.9350 1.1550 1.1250 ;
        RECT 4.0850 1.2600 4.2750 1.4500 ;
        RECT 0.9650 2.2450 1.1550 2.4350 ;
        RECT 2.0050 2.2450 2.1950 2.4350 ;
        RECT 3.5650 2.2450 3.7550 2.4350 ;
    END
  END Y
  PIN VDD
    DIRECTION INOUT ;
    USE POWER ;
    SHAPE ABUTMENT ;
    PORT
      LAYER Metal1 ;
        RECT 0.0000 3.5600 5.7600 4.0000 ;
    END
  END VDD
  PIN VSS
    DIRECTION INOUT ;
    USE GROUND ;
    SHAPE ABUTMENT ;
    PORT
      LAYER Metal1 ;
        RECT 0.0000 -0.2200 5.7600 0.2200 ;
    END
  END VSS
  OBS
    LAYER Metal2 ;
      RECT 1.9550 0.5200 3.8050 0.7200 ;
      RECT 0.1800 1.9000 0.3800 2.6500 ;
      RECT 2.7800 1.9000 2.9800 2.6500 ;
      RECT 0.1800 2.6500 0.6400 2.8500 ;
      RECT 2.5200 2.6500 2.9800 2.8500 ;
      RECT 0.4400 2.8500 0.6400 3.0600 ;
      RECT 1.4800 1.9000 1.6800 3.0600 ;
      RECT 2.5200 2.8500 2.7200 3.0600 ;
      RECT 0.4400 3.0600 2.7200 3.2600 ;
    LAYER Metal1 ;
      RECT 1.9850 0.4750 2.2150 0.6600 ;
      RECT 1.9700 0.6600 2.2300 1.2600 ;
      RECT 3.5450 0.4750 3.7750 0.6600 ;
      RECT 3.5300 0.6600 3.7900 1.2600 ;
      RECT 0.4100 0.8300 0.6700 0.8800 ;
      RECT 0.2000 0.8800 0.6850 1.0400 ;
      RECT 0.2000 1.0400 0.6700 1.0900 ;
      RECT 0.2000 1.0900 0.3600 1.9000 ;
      RECT 0.1650 1.9000 0.3950 2.1900 ;
      RECT 1.4500 0.7100 1.7100 1.3100 ;
      RECT 1.5000 1.3100 1.6600 1.9000 ;
      RECT 1.4650 1.9000 1.6950 2.1900 ;
      RECT 2.4900 0.8300 2.7500 0.8800 ;
      RECT 2.4750 0.8800 2.9600 1.0400 ;
      RECT 2.4900 1.0400 2.9600 1.0900 ;
      RECT 2.8000 1.0900 2.9600 1.9000 ;
      RECT 2.7650 1.9000 2.9950 2.1900 ;
      RECT 0.4600 2.6050 0.6200 2.6200 ;
      RECT 2.5400 2.6050 2.7000 2.6200 ;
      RECT 3.0600 2.6050 3.2200 2.6200 ;
      RECT 5.1400 2.6050 5.3000 2.6200 ;
      RECT 0.4100 2.6200 0.6700 2.8800 ;
      RECT 2.4900 2.6200 2.7500 2.8800 ;
      RECT 3.0100 2.6200 3.2700 2.8800 ;
      RECT 5.0900 2.6200 5.3500 2.8800 ;
      RECT 0.4600 2.8800 0.6200 3.0800 ;
      RECT 1.4500 2.4500 1.7100 3.0800 ;
      RECT 2.5400 2.8800 2.7000 3.0800 ;
      RECT 3.0600 2.8800 3.2200 3.0800 ;
      RECT 4.0500 2.1100 4.3100 3.0800 ;
      RECT 5.1400 2.8800 5.3000 3.0800 ;
      RECT 0.4600 3.0800 5.3000 3.2400 ;
    LAYER Via1 ;
      RECT 2.0050 0.5250 2.1950 0.7150 ;
      RECT 3.5650 0.5250 3.7550 0.7150 ;
      RECT 0.1850 1.9500 0.3750 2.1400 ;
      RECT 1.4850 1.9500 1.6750 2.1400 ;
      RECT 2.7850 1.9500 2.9750 2.1400 ;
  END
END sg13g2_a31oi_2

MACRO sg13g2_buf_32
  CLASS CORE ;
  ORIGIN 0 0 ;
  FOREIGN sg13g2_buf_32 0 0 ;
  SIZE 18.2400 BY 3.7800 ;
  SYMMETRY X Y ;
  SITE CoreSite ;
  PIN A
    DIRECTION INPUT ;
    USE SIGNAL ;
    ANTENNAMODEL OXIDE1 ;
    ANTENNAGATEAREA 0.1807 LAYER Metal1 ;
    PORT
      LAYER Metal1 ;
        RECT 0.6500 1.5500 0.9500 1.6000 ;
        RECT 0.6500 1.6000 1.0400 1.7600 ;
        RECT 0.6500 1.7600 0.9500 1.8500 ;
    END
  END A
  PIN X
    DIRECTION OUTPUT ;
    USE SIGNAL ;
    ANTENNADIFFAREA 11.6064 LAYER Metal1 ;
    PORT
      LAYER Metal1 ;
        RECT 1.5000 0.5400 17.2600 0.6100 ;
        RECT 1.5000 0.6100 17.3100 0.7000 ;
        RECT 1.5000 0.7000 1.7100 0.7100 ;
        RECT 2.4900 0.7000 2.7500 1.2100 ;
        RECT 3.5300 0.7000 3.7900 1.2100 ;
        RECT 4.5700 0.7000 4.8300 1.2100 ;
        RECT 5.6100 0.7000 5.8700 1.2100 ;
        RECT 6.6500 0.7000 6.9100 1.2100 ;
        RECT 7.6900 0.7000 7.9500 1.2100 ;
        RECT 8.7300 0.7000 8.9900 1.2100 ;
        RECT 9.7700 0.7000 10.0300 1.2100 ;
        RECT 10.8100 0.7000 11.0700 1.2100 ;
        RECT 11.8500 0.7000 12.1100 1.2100 ;
        RECT 12.8900 0.7000 13.1500 1.2100 ;
        RECT 13.9300 0.7000 14.1900 1.2100 ;
        RECT 14.9700 0.7000 15.2300 1.2100 ;
        RECT 16.0100 0.7000 16.2700 1.2100 ;
        RECT 17.0500 0.7000 17.3100 1.2100 ;
        RECT 1.4500 0.7100 1.7100 1.3100 ;
        RECT 1.5000 1.3100 1.6600 2.0900 ;
        RECT 1.4500 2.0900 1.7100 2.5500 ;
        RECT 2.4900 2.3000 2.7500 2.5500 ;
        RECT 3.5300 2.3000 3.7900 2.5500 ;
        RECT 4.5700 2.3000 4.8300 2.5500 ;
        RECT 5.6100 2.3000 5.8700 2.5500 ;
        RECT 6.6500 2.3000 6.9100 2.5500 ;
        RECT 7.6900 2.3000 7.9500 2.5500 ;
        RECT 8.7300 2.3000 8.9900 2.5500 ;
        RECT 9.7700 2.3000 10.0300 2.5500 ;
        RECT 10.8100 2.3000 11.0700 2.5500 ;
        RECT 11.8500 2.3000 12.1100 2.5500 ;
        RECT 12.8900 2.3000 13.1500 2.5500 ;
        RECT 13.9300 2.3000 14.1900 2.5500 ;
        RECT 14.9700 2.3000 15.2300 2.5500 ;
        RECT 16.0100 2.3000 16.2700 2.5500 ;
        RECT 17.0500 2.3000 17.3100 2.5500 ;
        RECT 1.4500 2.5500 17.3250 2.6900 ;
        RECT 1.5000 2.6900 17.3250 2.7100 ;
        RECT 2.4900 2.7100 2.7500 2.9000 ;
        RECT 3.5300 2.7100 3.7900 2.9000 ;
        RECT 4.5700 2.7100 4.8300 2.9000 ;
        RECT 5.6100 2.7100 5.8700 2.9000 ;
        RECT 6.6500 2.7100 6.9100 2.9000 ;
        RECT 7.6900 2.7100 7.9500 2.9000 ;
        RECT 8.7300 2.7100 8.9900 2.9000 ;
        RECT 9.7700 2.7100 10.0300 2.9000 ;
        RECT 10.8100 2.7100 11.0700 2.9000 ;
        RECT 11.8500 2.7100 12.1100 2.9000 ;
        RECT 12.8900 2.7100 13.1500 2.9000 ;
        RECT 13.9300 2.7100 14.1900 2.9000 ;
        RECT 14.9700 2.7100 15.2300 2.9000 ;
        RECT 16.0100 2.7100 16.2700 2.9000 ;
        RECT 17.0500 2.7100 17.3100 2.9000 ;
    END
  END X
  PIN VDD
    DIRECTION INOUT ;
    USE POWER ;
    SHAPE ABUTMENT ;
    PORT
      LAYER Metal1 ;
        RECT 0.0000 3.5600 18.2400 4.0000 ;
    END
  END VDD
  PIN VSS
    DIRECTION INOUT ;
    USE GROUND ;
    SHAPE ABUTMENT ;
    PORT
      LAYER Metal1 ;
        RECT 0.0000 -0.2200 18.2400 0.2200 ;
        RECT 0.9300 0.2200 1.1900 0.8700 ;
    END
  END VSS
  OBS
    LAYER Metal1 ;
      RECT 0.4100 0.7350 0.6700 0.7850 ;
      RECT 0.2000 0.7850 0.6850 0.9450 ;
      RECT 0.2000 0.9450 0.6700 0.9950 ;
      RECT 17.3100 1.5700 18.0900 1.6200 ;
      RECT 17.2950 1.6200 18.0900 1.7800 ;
      RECT 17.3100 1.7800 18.0900 1.8300 ;
      RECT 0.2000 0.9950 0.3600 2.6400 ;
      RECT 0.2000 2.6400 0.6700 2.6900 ;
      RECT 0.2000 2.6900 0.8800 2.8500 ;
      RECT 0.4100 2.8500 0.8800 2.9000 ;
      RECT 0.7200 2.9000 0.8800 3.0800 ;
      RECT 17.6200 1.8300 17.7800 3.0800 ;
      RECT 0.7200 3.0800 17.7800 3.2400 ;
  END
END sg13g2_buf_32

MACRO sg13g2_dlygate4sd_4
  CLASS CORE ;
  ORIGIN 0 0 ;
  FOREIGN sg13g2_dlygate4sd_4 0 0 ;
  SIZE 5.2800 BY 3.7800 ;
  SYMMETRY X Y ;
  SITE CoreSite ;
  PIN A
    DIRECTION INPUT ;
    USE SIGNAL ;
    ANTENNAMODEL OXIDE1 ;
    ANTENNAGATEAREA 0.1092 LAYER Metal1 ;
    PORT
      LAYER Metal1 ;
        RECT 4.3300 1.2300 4.5900 1.5500 ;
        RECT 4.3100 1.5500 4.6100 1.8500 ;
    END
  END A
  PIN X
    DIRECTION OUTPUT ;
    USE SIGNAL ;
    ANTENNADIFFAREA 1.4508 LAYER Metal1 ;
    PORT
      LAYER Metal1 ;
        RECT 1.0000 0.5400 2.2000 0.6100 ;
        RECT 1.0000 0.6100 2.2500 0.7000 ;
        RECT 1.0000 0.7000 1.2100 0.7100 ;
        RECT 1.9900 0.7000 2.2500 1.2100 ;
        RECT 0.9500 0.7100 1.2100 1.3100 ;
        RECT 1.0000 1.3100 1.1600 2.0900 ;
        RECT 2.0400 2.8350 2.2000 2.8500 ;
        RECT 0.9500 2.0900 1.2100 3.0300 ;
        RECT 1.0000 3.0300 1.2100 3.0800 ;
        RECT 1.9900 2.8500 2.2500 3.0800 ;
        RECT 1.0000 3.0800 2.2500 3.1100 ;
        RECT 1.0000 3.1100 2.2000 3.2400 ;
    END
  END X
  PIN VDD
    DIRECTION INOUT ;
    USE POWER ;
    SHAPE ABUTMENT ;
    PORT
      LAYER Metal1 ;
        RECT 0.0000 3.5600 5.2800 4.0000 ;
    END
  END VDD
  PIN VSS
    DIRECTION INOUT ;
    USE GROUND ;
    SHAPE ABUTMENT ;
    PORT
      LAYER Metal1 ;
        RECT 0.0000 -0.2200 5.2800 0.2200 ;
    END
  END VSS
  OBS
    LAYER Metal2 ;
      RECT 2.5400 0.4750 2.7400 1.6000 ;
      RECT 2.2350 1.6000 2.7400 1.8000 ;
      RECT 3.8400 0.4750 4.0400 2.2400 ;
      RECT 3.2750 2.2400 4.0400 2.4400 ;
      RECT 3.8400 2.4400 4.0400 3.3050 ;
    LAYER Metal1 ;
      RECT 2.5250 0.4750 2.7550 0.7200 ;
      RECT 3.0300 0.6700 3.2900 0.7200 ;
      RECT 2.5250 0.7200 3.3050 0.7650 ;
      RECT 2.5600 0.7650 3.3050 0.8800 ;
      RECT 3.0300 0.8800 3.2900 0.9300 ;
      RECT 1.7800 1.5550 1.9400 1.5700 ;
      RECT 2.2650 1.5550 2.4950 1.5700 ;
      RECT 1.7300 1.5700 2.5100 1.8300 ;
      RECT 2.2650 1.8300 2.4950 1.8450 ;
      RECT 1.7800 1.8300 1.9400 2.2600 ;
      RECT 2.3000 1.8450 2.4600 2.2600 ;
      RECT 1.7800 2.2600 2.9800 2.4200 ;
      RECT 2.8200 2.4200 2.9800 2.8500 ;
      RECT 2.8200 2.8500 3.2900 2.9000 ;
      RECT 2.8200 2.9000 3.3050 3.0600 ;
      RECT 3.0300 3.0600 3.2900 3.1100 ;
      RECT 3.8250 0.4750 4.0550 0.6700 ;
      RECT 3.5500 0.6700 4.0550 0.7200 ;
      RECT 3.5350 0.7200 4.0550 0.7650 ;
      RECT 3.5350 0.7650 4.0200 0.8800 ;
      RECT 3.5500 0.8800 3.8100 0.9300 ;
      RECT 2.7700 1.5700 3.5500 1.6200 ;
      RECT 2.7550 1.6200 3.5500 1.7800 ;
      RECT 2.7700 1.7800 3.5500 1.8300 ;
      RECT 3.3400 1.8300 3.5000 2.1950 ;
      RECT 3.3050 2.1950 3.5350 2.4850 ;
      RECT 3.5500 2.8500 3.8100 2.9000 ;
      RECT 3.5350 2.9000 4.0200 3.0150 ;
      RECT 3.5350 3.0150 4.0550 3.0600 ;
      RECT 3.5500 3.0600 4.0550 3.1100 ;
      RECT 3.8250 3.1100 4.0550 3.3050 ;
      RECT 4.5900 0.6700 4.8500 0.7200 ;
      RECT 4.5750 0.7200 5.0600 0.8800 ;
      RECT 4.5900 0.8800 5.0600 0.9300 ;
      RECT 3.8100 1.2300 4.0700 1.8300 ;
      RECT 3.8600 1.8300 4.0200 2.2600 ;
      RECT 3.8600 2.2600 4.5400 2.4200 ;
      RECT 4.3800 2.4200 4.5400 2.8500 ;
      RECT 4.9000 0.9300 5.0600 2.8500 ;
      RECT 4.3800 2.8500 5.0600 3.0600 ;
      RECT 4.5900 3.0600 4.8500 3.1100 ;
    LAYER Via1 ;
      RECT 2.5450 0.5250 2.7350 0.7150 ;
      RECT 2.2850 1.6050 2.4750 1.7950 ;
      RECT 3.8450 0.5250 4.0350 0.7150 ;
      RECT 3.3250 2.2450 3.5150 2.4350 ;
      RECT 3.8450 3.0650 4.0350 3.2550 ;
  END
END sg13g2_dlygate4sd_4

MACRO sg13g2_inv_32
  CLASS CORE ;
  ORIGIN 0 0 ;
  FOREIGN sg13g2_inv_32 0 0 ;
  SIZE 17.7600 BY 3.7800 ;
  SYMMETRY X Y ;
  SITE CoreSite ;
  PIN A
    DIRECTION INPUT ;
    USE SIGNAL ;
    ANTENNAMODEL OXIDE1 ;
    ANTENNAGATEAREA 7.7376 LAYER Metal1 ;
    PORT
      LAYER Metal1 ;
        RECT 11.5900 1.5500 11.8900 1.5700 ;
        RECT 11.5900 1.5700 12.3900 1.8300 ;
        RECT 11.5900 1.8300 11.8900 1.8500 ;
    END
  END A
  PIN Y
    DIRECTION OUTPUT ;
    USE SIGNAL ;
    ANTENNADIFFAREA 11.6064 LAYER Metal1 ;
    PORT
      LAYER Metal1 ;
        RECT 0.9500 0.6600 1.2100 0.8800 ;
        RECT 1.9900 0.6600 2.2500 0.8800 ;
        RECT 3.0300 0.6600 3.2900 0.8800 ;
        RECT 4.0700 0.6600 4.3300 0.8800 ;
        RECT 5.1100 0.6600 5.3700 0.8800 ;
        RECT 6.1500 0.6600 6.4100 0.8800 ;
        RECT 7.1900 0.6600 7.4500 0.8800 ;
        RECT 8.2300 0.6600 8.4900 0.8800 ;
        RECT 9.2700 0.6600 9.5300 0.8800 ;
        RECT 10.3100 0.6600 10.5700 0.8800 ;
        RECT 11.3500 0.6600 11.6100 0.8800 ;
        RECT 12.3900 0.6600 12.6500 0.8800 ;
        RECT 13.4300 0.6600 13.6900 0.8800 ;
        RECT 14.4700 0.6600 14.7300 0.8800 ;
        RECT 15.5100 0.6600 15.7700 0.8800 ;
        RECT 16.5500 0.6600 16.8100 0.8800 ;
        RECT 0.9350 0.8800 16.8250 1.0400 ;
        RECT 0.9500 1.0400 1.2100 1.2600 ;
        RECT 1.7800 1.0400 2.2500 1.2600 ;
        RECT 3.0300 1.0400 3.2900 1.2600 ;
        RECT 4.0700 1.0400 4.3300 1.2600 ;
        RECT 5.1100 1.0400 5.3700 1.2600 ;
        RECT 6.1500 1.0400 6.4100 1.2600 ;
        RECT 7.1900 1.0400 7.4500 1.2600 ;
        RECT 8.2300 1.0400 8.4900 1.2600 ;
        RECT 9.2700 1.0400 9.5300 1.2600 ;
        RECT 10.3100 1.0400 10.5700 1.2600 ;
        RECT 11.3500 1.0400 11.6100 1.2600 ;
        RECT 12.3900 1.0400 12.6500 1.2600 ;
        RECT 13.4300 1.0400 13.6900 1.2600 ;
        RECT 14.4700 1.0400 14.7300 1.2600 ;
        RECT 15.5100 1.0400 15.7700 1.2600 ;
        RECT 16.5500 1.0400 16.8100 1.2600 ;
        RECT 1.7800 1.2600 1.9400 2.1100 ;
        RECT 0.9500 2.1100 1.2100 2.6700 ;
        RECT 1.7800 2.1100 2.2500 2.6700 ;
        RECT 3.0300 2.1100 3.2900 2.6700 ;
        RECT 4.0700 2.1100 4.3300 2.6700 ;
        RECT 5.1100 2.1100 5.3700 2.6700 ;
        RECT 6.1500 2.1100 6.4100 2.6700 ;
        RECT 7.1900 2.1100 7.4500 2.6700 ;
        RECT 8.2300 2.1100 8.4900 2.6700 ;
        RECT 9.2700 2.1100 9.5300 2.6700 ;
        RECT 10.3100 2.1100 10.5700 2.6700 ;
        RECT 11.3500 2.1100 11.6100 2.6700 ;
        RECT 12.3900 2.1100 12.6500 2.6700 ;
        RECT 13.4300 2.1100 13.6900 2.6700 ;
        RECT 14.4700 2.1100 14.7300 2.6700 ;
        RECT 15.5100 2.1100 15.7700 2.6700 ;
        RECT 16.5500 2.1100 16.8100 2.6700 ;
        RECT 0.9350 2.6700 16.8250 2.8300 ;
        RECT 0.9500 2.8300 1.2100 3.0500 ;
        RECT 1.9900 2.8300 2.2500 3.0500 ;
        RECT 3.0300 2.8300 3.2900 3.0500 ;
        RECT 4.0700 2.8300 4.3300 3.0500 ;
        RECT 5.1100 2.8300 5.3700 3.0500 ;
        RECT 6.1500 2.8300 6.4100 3.0500 ;
        RECT 7.1900 2.8300 7.4500 3.0500 ;
        RECT 8.2300 2.8300 8.4900 3.0500 ;
        RECT 9.2700 2.8300 9.5300 3.0500 ;
        RECT 10.3100 2.8300 10.5700 3.0500 ;
        RECT 11.3500 2.8300 11.6100 3.0500 ;
        RECT 12.3900 2.8300 12.6500 3.0500 ;
        RECT 13.4300 2.8300 13.6900 3.0500 ;
        RECT 14.4700 2.8300 14.7300 3.0500 ;
        RECT 15.5100 2.8300 15.7700 3.0500 ;
        RECT 16.5500 2.8300 16.8100 3.0500 ;
    END
  END Y
  PIN VDD
    DIRECTION INOUT ;
    USE POWER ;
    SHAPE ABUTMENT ;
    PORT
      LAYER Metal1 ;
        RECT 0.0000 3.5600 17.7600 4.0000 ;
    END
  END VDD
  PIN VSS
    DIRECTION INOUT ;
    USE GROUND ;
    SHAPE ABUTMENT ;
    PORT
      LAYER Metal1 ;
        RECT 0.0000 -0.2200 17.7600 0.2200 ;
    END
  END VSS
END sg13g2_inv_32

MACRO sg13g2_mux2_4
  CLASS CORE ;
  ORIGIN 0 0 ;
  FOREIGN sg13g2_mux2_4 0 0 ;
  SIZE 7.2000 BY 3.7800 ;
  SYMMETRY X Y ;
  SITE CoreSite ;
  PIN A0
    DIRECTION INPUT ;
    USE SIGNAL ;
    ANTENNAMODEL OXIDE1 ;
    ANTENNAGATEAREA 0.2262 LAYER Metal1 ;
    PORT
      LAYER Metal1 ;
        RECT 3.8900 1.5500 4.2700 1.8500 ;
        RECT 3.8900 1.8500 4.0500 2.0200 ;
        RECT 3.7600 2.0200 4.0500 2.1800 ;
    END
  END A0
  PIN A1
    DIRECTION INPUT ;
    USE SIGNAL ;
    ANTENNAMODEL OXIDE1 ;
    ANTENNAGATEAREA 0.2262 LAYER Metal1 ;
    PORT
      LAYER Metal1 ;
        RECT 4.4900 1.5500 4.7900 1.6000 ;
        RECT 4.4900 1.6000 4.8800 1.7600 ;
        RECT 4.4900 1.7600 4.7900 1.8500 ;
    END
  END A1
  PIN S
    DIRECTION INPUT ;
    USE SIGNAL ;
    ANTENNAMODEL OXIDE1 ;
    ANTENNAGATEAREA 0.4069 LAYER Metal1 ;
    PORT
      LAYER Metal1 ;
        RECT 6.0700 1.4200 6.3300 1.5500 ;
        RECT 6.0500 1.5500 6.3500 1.8500 ;
        RECT 6.0700 1.8500 6.3300 2.0200 ;
    END
  END S
  PIN X
    DIRECTION OUTPUT ;
    USE SIGNAL ;
    ANTENNADIFFAREA 1.4508 LAYER Metal1 ;
    PORT
      LAYER Metal1 ;
        RECT 1.1300 0.6100 1.3900 0.7850 ;
        RECT 2.1700 0.6100 2.4300 0.7850 ;
        RECT 1.1150 0.7850 2.4450 0.9450 ;
        RECT 1.1300 0.9450 1.6000 1.2100 ;
        RECT 2.1700 0.9450 2.4300 1.2100 ;
        RECT 1.4400 1.2100 1.6000 2.3000 ;
        RECT 1.1300 2.3000 1.6000 2.6100 ;
        RECT 2.1700 2.3000 2.4300 2.6100 ;
        RECT 1.1150 2.6100 2.4450 2.7700 ;
        RECT 1.1300 2.7700 1.3900 2.9000 ;
        RECT 2.1700 2.7700 2.4300 2.9000 ;
    END
  END X
  PIN VDD
    DIRECTION INOUT ;
    USE POWER ;
    SHAPE ABUTMENT ;
    PORT
      LAYER Metal1 ;
        RECT 0.0000 3.5600 7.2000 4.0000 ;
    END
  END VDD
  PIN VSS
    DIRECTION INOUT ;
    USE GROUND ;
    SHAPE ABUTMENT ;
    PORT
      LAYER Metal1 ;
        RECT 0.0000 -0.2200 7.2000 0.2200 ;
        RECT 5.8100 0.2200 6.0700 0.8700 ;
        RECT 2.6900 0.2200 2.9500 1.2100 ;
    END
  END VSS
  OBS
    LAYER Metal2 ;
      RECT 2.4600 0.9300 4.5250 1.1300 ;
      RECT 2.4600 1.1300 2.6600 2.2400 ;
      RECT 2.4600 2.2400 4.5250 2.4400 ;
      RECT 1.9400 1.5550 2.1400 3.0600 ;
      RECT 4.8000 2.1950 5.0000 3.0600 ;
      RECT 1.9400 3.0600 5.0000 3.2600 ;
      RECT 2.9350 1.6000 6.8650 1.8000 ;
    LAYER Metal1 ;
      RECT 3.2100 0.7350 3.4700 0.7850 ;
      RECT 3.7300 0.7350 3.9900 0.7850 ;
      RECT 3.1950 0.7850 4.0050 0.9450 ;
      RECT 3.2100 0.9450 3.9900 0.9950 ;
      RECT 3.5200 0.9950 3.6800 1.7800 ;
      RECT 4.7700 0.7350 5.0300 0.7850 ;
      RECT 5.2900 0.7350 5.5500 0.7850 ;
      RECT 4.7550 0.7850 5.5650 0.9450 ;
      RECT 4.7700 0.9450 5.5500 0.9950 ;
      RECT 5.0800 0.9950 5.2400 1.7800 ;
      RECT 4.2500 0.7100 4.5100 0.8800 ;
      RECT 4.2300 0.8800 4.5300 1.1800 ;
      RECT 4.2500 1.1800 4.5100 1.3100 ;
      RECT 4.2300 2.1900 4.5300 2.4900 ;
      RECT 4.2500 2.4900 4.5100 2.8100 ;
      RECT 0.3500 1.5700 1.1300 1.6200 ;
      RECT 0.3500 1.6200 1.1450 1.7800 ;
      RECT 0.3500 1.7800 1.1300 1.8300 ;
      RECT 2.7050 2.1950 2.9350 2.4850 ;
      RECT 0.6600 1.8300 0.8200 3.0800 ;
      RECT 2.7400 2.4850 2.9000 3.0800 ;
      RECT 0.6600 3.0800 2.9000 3.2400 ;
      RECT 1.8950 1.5850 2.1850 1.6200 ;
      RECT 1.8950 1.6200 2.6400 1.7800 ;
      RECT 1.8950 1.7800 2.1850 1.8150 ;
      RECT 4.7500 2.1900 5.0500 2.4900 ;
      RECT 3.2600 2.6250 3.4200 2.6400 ;
      RECT 3.2100 2.6400 3.4700 2.9000 ;
      RECT 3.2250 2.9000 3.4550 3.3050 ;
      RECT 2.9300 1.5500 3.2300 1.8500 ;
      RECT 6.3300 0.7350 6.5900 0.7850 ;
      RECT 6.3150 0.7850 6.8000 0.9450 ;
      RECT 6.3300 0.9450 6.8000 0.9950 ;
      RECT 6.6400 0.9950 6.8000 1.5550 ;
      RECT 6.6050 1.5550 6.8350 1.8450 ;
      RECT 6.6400 1.8450 6.8000 2.6400 ;
      RECT 6.3300 2.6400 6.8000 2.6900 ;
      RECT 6.3150 2.6900 6.8000 2.8500 ;
      RECT 6.3300 2.8500 6.5900 2.9000 ;
      RECT 5.6000 1.6200 5.7600 2.5600 ;
      RECT 5.2900 2.5600 5.7600 2.6100 ;
      RECT 3.7800 2.6250 3.9400 2.6400 ;
      RECT 5.2750 2.6100 5.7600 2.7700 ;
      RECT 5.2900 2.7700 5.7600 2.8200 ;
      RECT 3.7300 2.6400 3.9900 2.9000 ;
      RECT 3.7800 2.9000 3.9400 3.0800 ;
      RECT 5.6000 2.8200 5.7600 3.0800 ;
      RECT 3.7800 3.0800 5.7600 3.2400 ;
    LAYER Via1 ;
      RECT 4.2850 0.9350 4.4750 1.1250 ;
      RECT 2.7250 2.2450 2.9150 2.4350 ;
      RECT 4.2850 2.2450 4.4750 2.4350 ;
      RECT 1.9450 1.6050 2.1350 1.7950 ;
      RECT 4.8050 2.2450 4.9950 2.4350 ;
      RECT 3.2450 3.0650 3.4350 3.2550 ;
      RECT 2.9850 1.6050 3.1750 1.7950 ;
      RECT 6.6250 1.6050 6.8150 1.7950 ;
  END
END sg13g2_mux2_4

MACRO sg13g2_mux2_8
  CLASS CORE ;
  ORIGIN 0 0 ;
  FOREIGN sg13g2_mux2_8 0 0 ;
  SIZE 9.1200 BY 3.7800 ;
  SYMMETRY X Y ;
  SITE CoreSite ;
  PIN A0
    DIRECTION INPUT ;
    USE SIGNAL ;
    ANTENNAMODEL OXIDE1 ;
    ANTENNAGATEAREA 0.2262 LAYER Metal1 ;
    PORT
      LAYER Metal1 ;
        RECT 5.9700 1.5500 6.2700 1.8500 ;
    END
  END A0
  PIN A1
    DIRECTION INPUT ;
    USE SIGNAL ;
    ANTENNAMODEL OXIDE1 ;
    ANTENNAGATEAREA 0.2262 LAYER Metal1 ;
    PORT
      LAYER Metal1 ;
        RECT 6.4900 1.5500 6.7900 1.8500 ;
    END
  END A1
  PIN S
    DIRECTION INPUT ;
    USE SIGNAL ;
    ANTENNAMODEL OXIDE1 ;
    ANTENNAGATEAREA 0.4069 LAYER Metal1 ;
    PORT
      LAYER Metal1 ;
        RECT 8.0700 1.4200 8.3300 1.5500 ;
        RECT 8.0500 1.5500 8.3500 1.8500 ;
        RECT 8.0700 1.8500 8.3300 2.0200 ;
    END
  END S
  PIN X
    DIRECTION OUTPUT ;
    USE SIGNAL ;
    ANTENNADIFFAREA 2.9016 LAYER Metal1 ;
    PORT
      LAYER Metal1 ;
        RECT 1.1000 0.5400 4.3800 0.6100 ;
        RECT 1.0500 0.6100 4.4300 0.7000 ;
        RECT 1.0500 0.7000 1.3100 1.2100 ;
        RECT 2.0900 0.7000 2.3500 1.2100 ;
        RECT 3.1300 0.7000 3.3900 1.2100 ;
        RECT 4.1700 0.7000 4.4300 1.2100 ;
        RECT 2.1400 1.2100 2.3000 2.0900 ;
        RECT 1.0500 2.3000 1.3100 2.6100 ;
        RECT 2.0900 2.0900 2.3500 2.6100 ;
        RECT 3.1300 2.3000 3.3900 2.6100 ;
        RECT 4.1700 2.3000 4.4300 2.6100 ;
        RECT 1.0350 2.6100 4.4450 2.7700 ;
        RECT 1.0500 2.7700 1.3100 2.9000 ;
        RECT 3.1300 2.7700 3.3900 2.9000 ;
        RECT 4.1700 2.7700 4.4300 2.9000 ;
    END
  END X
  PIN VDD
    DIRECTION INOUT ;
    USE POWER ;
    SHAPE ABUTMENT ;
    PORT
      LAYER Metal1 ;
        RECT 0.0000 3.5600 9.1200 4.0000 ;
    END
  END VDD
  PIN VSS
    DIRECTION INOUT ;
    USE GROUND ;
    SHAPE ABUTMENT ;
    PORT
      LAYER Metal1 ;
        RECT 0.0000 -0.2200 9.1200 0.2200 ;
        RECT 7.8100 0.2200 8.0700 0.8700 ;
        RECT 4.6900 0.2200 4.9500 1.2100 ;
    END
  END VSS
  OBS
    LAYER Metal2 ;
      RECT 4.4600 0.9300 6.5250 1.1300 ;
      RECT 4.4600 1.1300 4.6600 2.2400 ;
      RECT 4.4600 2.2400 6.5250 2.4400 ;
      RECT 3.9400 1.5550 4.1400 3.0600 ;
      RECT 6.8000 2.1950 7.0000 3.0600 ;
      RECT 3.9400 3.0600 7.0000 3.2600 ;
      RECT 4.9350 1.6000 8.8650 1.8000 ;
    LAYER Metal1 ;
      RECT 6.2500 0.7100 6.5100 0.8800 ;
      RECT 6.2300 0.8800 6.5300 1.1800 ;
      RECT 6.2500 1.1800 6.5100 1.3100 ;
      RECT 6.2300 2.1900 6.5300 2.4900 ;
      RECT 6.2500 2.4900 6.5100 2.8100 ;
      RECT 0.7900 1.5700 1.5700 1.6200 ;
      RECT 0.5800 1.6200 1.5700 1.8300 ;
      RECT 4.7050 2.1950 4.9350 2.4850 ;
      RECT 0.5800 1.8300 0.7400 3.0800 ;
      RECT 4.7400 2.4850 4.9000 3.0800 ;
      RECT 0.5800 3.0800 4.9000 3.2400 ;
      RECT 3.8950 1.5850 4.1850 1.6200 ;
      RECT 3.8950 1.6200 4.6400 1.7800 ;
      RECT 3.8950 1.7800 4.1850 1.8150 ;
      RECT 6.7500 2.1900 7.0500 2.4900 ;
      RECT 5.2600 2.6250 5.4200 2.6400 ;
      RECT 5.2100 2.6400 5.4700 2.9000 ;
      RECT 5.2250 2.9000 5.4550 3.3050 ;
      RECT 4.9300 1.5500 5.2300 1.8500 ;
      RECT 8.3300 0.7350 8.5900 0.7850 ;
      RECT 8.3150 0.7850 8.8000 0.9450 ;
      RECT 8.3300 0.9450 8.8000 0.9950 ;
      RECT 8.6400 0.9950 8.8000 1.5550 ;
      RECT 8.6050 1.5550 8.8350 1.8450 ;
      RECT 8.6400 1.8450 8.8000 2.6400 ;
      RECT 8.3300 2.6400 8.8000 2.6900 ;
      RECT 8.3150 2.6900 8.8000 2.8500 ;
      RECT 8.3300 2.8500 8.5900 2.9000 ;
      RECT 5.2100 0.7350 5.4700 0.7850 ;
      RECT 5.7300 0.7350 5.9900 0.7850 ;
      RECT 5.1950 0.7850 6.0050 0.9450 ;
      RECT 5.2100 0.9450 5.9900 0.9950 ;
      RECT 5.5200 0.9950 5.6800 1.7800 ;
      RECT 6.7700 0.7350 7.0300 0.7850 ;
      RECT 7.2900 0.7350 7.5500 0.7850 ;
      RECT 6.7550 0.7850 7.5650 0.9450 ;
      RECT 6.7700 0.9450 7.5500 0.9950 ;
      RECT 7.0800 0.9950 7.2400 1.7800 ;
      RECT 7.6000 1.6200 7.7600 2.5600 ;
      RECT 7.2900 2.5600 7.7600 2.6100 ;
      RECT 5.7800 2.6250 5.9400 2.6400 ;
      RECT 7.2750 2.6100 7.7600 2.7700 ;
      RECT 7.2900 2.7700 7.7600 2.8200 ;
      RECT 5.7300 2.6400 5.9900 2.9000 ;
      RECT 5.7800 2.9000 5.9400 3.0800 ;
      RECT 7.6000 2.8200 7.7600 3.0800 ;
      RECT 5.7800 3.0800 7.7600 3.2400 ;
    LAYER Via1 ;
      RECT 6.2850 0.9350 6.4750 1.1250 ;
      RECT 4.7250 2.2450 4.9150 2.4350 ;
      RECT 6.2850 2.2450 6.4750 2.4350 ;
      RECT 3.9450 1.6050 4.1350 1.7950 ;
      RECT 6.8050 2.2450 6.9950 2.4350 ;
      RECT 5.2450 3.0650 5.4350 3.2550 ;
      RECT 4.9850 1.6050 5.1750 1.7950 ;
      RECT 8.6250 1.6050 8.8150 1.7950 ;
  END
END sg13g2_mux2_8

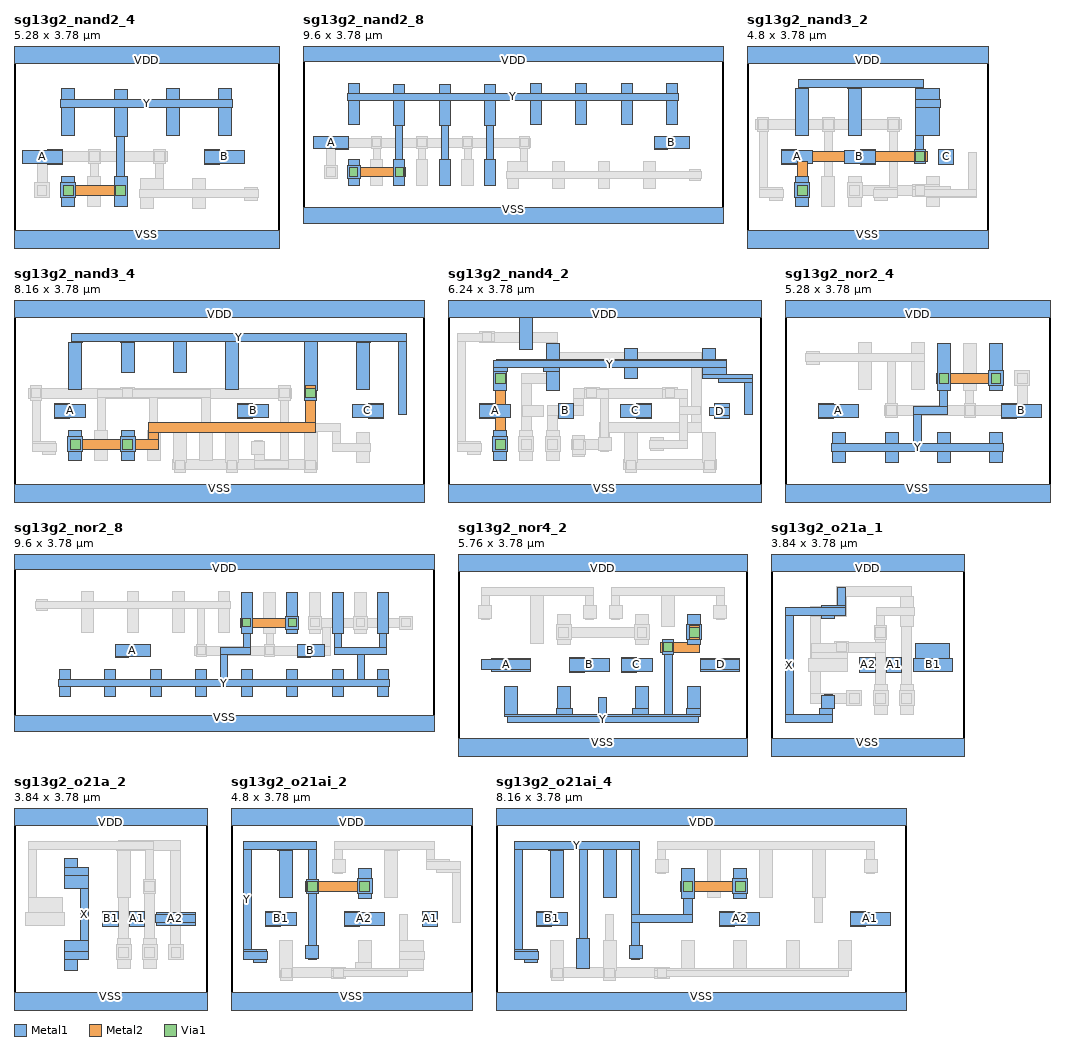
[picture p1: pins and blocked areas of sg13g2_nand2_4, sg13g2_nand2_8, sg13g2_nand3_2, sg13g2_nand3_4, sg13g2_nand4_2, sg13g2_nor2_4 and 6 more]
MACRO sg13g2_nand2_4
  CLASS CORE ;
  ORIGIN 0 0 ;
  FOREIGN sg13g2_nand2_4 0 0 ;
  SIZE 5.2800 BY 3.7800 ;
  SYMMETRY X Y ;
  SITE CoreSite ;
  PIN A
    DIRECTION INPUT ;
    USE SIGNAL ;
    ANTENNAMODEL OXIDE1 ;
    ANTENNAGATEAREA 0.9672 LAYER Metal1 ;
    PORT
      LAYER Metal1 ;
        RECT 0.6700 1.5500 0.9700 1.5700 ;
        RECT 0.1700 1.5700 0.9700 1.8300 ;
        RECT 0.6700 1.8300 0.9700 1.8500 ;
    END
  END A
  PIN B
    DIRECTION INPUT ;
    USE SIGNAL ;
    ANTENNAMODEL OXIDE1 ;
    ANTENNAGATEAREA 0.9672 LAYER Metal1 ;
    PORT
      LAYER Metal1 ;
        RECT 3.7900 1.5500 4.0900 1.5700 ;
        RECT 3.7900 1.5700 4.5900 1.8300 ;
        RECT 3.7900 1.8300 4.0900 1.8500 ;
    END
  END B
  PIN Y
    DIRECTION OUTPUT ;
    USE SIGNAL ;
    ANTENNAPARTIALMETALAREA 0.168 LAYER Metal1 ;
    ANTENNADIFFAREA 2.3244 LAYER Metal1 ;
    ANTENNADIFFAREA 2.3244 LAYER Metal2 ;
    PORT
      LAYER Metal2 ;
        RECT 0.9350 0.9300 2.2650 1.1300 ;
      LAYER Metal1 ;
        RECT 0.9500 0.7100 1.2100 0.8800 ;
        RECT 0.9300 0.8800 1.2300 1.1800 ;
        RECT 0.9500 1.1800 1.2100 1.3100 ;
        RECT 1.9900 0.7100 2.2500 1.3100 ;
        RECT 2.0400 1.3100 2.2000 2.0900 ;
        RECT 0.9500 2.1100 1.2100 2.6700 ;
        RECT 1.9900 2.0900 2.2500 2.6700 ;
        RECT 3.0300 2.1100 3.2900 2.6700 ;
        RECT 4.0700 2.1100 4.3300 2.6700 ;
        RECT 0.9350 2.6700 4.3450 2.8300 ;
        RECT 1.9900 2.8300 2.2500 3.0300 ;
        RECT 0.9500 2.8300 1.2100 3.0500 ;
        RECT 3.0300 2.8300 3.2900 3.0500 ;
        RECT 4.0700 2.8300 4.3300 3.0500 ;
      LAYER Via1 ;
        RECT 0.9850 0.9350 1.1750 1.1250 ;
        RECT 2.0250 0.9350 2.2150 1.1250 ;
    END
  END Y
  PIN VDD
    DIRECTION INOUT ;
    USE POWER ;
    SHAPE ABUTMENT ;
    PORT
      LAYER Metal1 ;
        RECT 0.0000 3.5600 5.2800 4.0000 ;
    END
  END VDD
  PIN VSS
    DIRECTION INOUT ;
    USE GROUND ;
    SHAPE ABUTMENT ;
    PORT
      LAYER Metal1 ;
        RECT 0.0000 -0.2200 5.2800 0.2200 ;
    END
  END VSS
  OBS
    LAYER Metal2 ;
      RECT 0.4600 0.8850 0.6600 1.6000 ;
      RECT 0.4600 1.6000 3.0450 1.8000 ;
    LAYER Metal1 ;
      RECT 0.4100 0.8800 0.7100 1.1800 ;
      RECT 1.4700 0.7100 1.7300 1.3100 ;
      RECT 1.5200 1.3100 1.6800 1.5550 ;
      RECT 1.4850 1.5550 1.7150 1.8450 ;
      RECT 2.5100 0.6600 2.7700 0.8800 ;
      RECT 3.5500 0.6600 3.8100 0.8800 ;
      RECT 4.5900 0.8300 4.8500 0.8800 ;
      RECT 2.4950 0.8800 4.8650 1.0400 ;
      RECT 4.5900 1.0400 4.8500 1.0900 ;
      RECT 2.5100 1.0400 2.9800 1.2600 ;
      RECT 3.5500 1.0400 3.8100 1.2600 ;
      RECT 2.8200 1.2600 2.9800 1.5550 ;
      RECT 2.7850 1.5550 3.0150 1.8450 ;
    LAYER Via1 ;
      RECT 0.4650 0.9350 0.6550 1.1250 ;
      RECT 1.5050 1.6050 1.6950 1.7950 ;
      RECT 2.8050 1.6050 2.9950 1.7950 ;
  END
END sg13g2_nand2_4

MACRO sg13g2_nand2_8
  CLASS CORE ;
  ORIGIN 0 0 ;
  FOREIGN sg13g2_nand2_8 0 0 ;
  SIZE 9.6000 BY 3.7800 ;
  SYMMETRY X Y ;
  SITE CoreSite ;
  PIN A
    DIRECTION INPUT ;
    USE SIGNAL ;
    ANTENNAMODEL OXIDE1 ;
    ANTENNAGATEAREA 1.9344 LAYER Metal1 ;
    PORT
      LAYER Metal1 ;
        RECT 0.7500 1.5500 1.0500 1.5700 ;
        RECT 0.2500 1.5700 1.0500 1.8300 ;
        RECT 0.7500 1.8300 1.0500 1.8500 ;
    END
  END A
  PIN B
    DIRECTION INPUT ;
    USE SIGNAL ;
    ANTENNAMODEL OXIDE1 ;
    ANTENNAGATEAREA 1.9344 LAYER Metal1 ;
    PORT
      LAYER Metal1 ;
        RECT 8.0300 1.5500 8.3300 1.5700 ;
        RECT 8.0300 1.5700 8.8300 1.8300 ;
        RECT 8.0300 1.8300 8.3300 1.8500 ;
    END
  END B
  PIN Y
    DIRECTION OUTPUT ;
    USE SIGNAL ;
    ANTENNAPARTIALMETALAREA 0.168 LAYER Metal1 ;
    ANTENNADIFFAREA 4.6488 LAYER Metal1 ;
    ANTENNADIFFAREA 4.6488 LAYER Metal2 ;
    PORT
      LAYER Metal2 ;
        RECT 1.0150 0.9300 2.3450 1.1300 ;
      LAYER Metal1 ;
        RECT 1.0300 0.7100 1.2900 0.8800 ;
        RECT 1.0100 0.8800 1.3100 1.1800 ;
        RECT 1.0300 1.1800 1.2900 1.3100 ;
        RECT 2.0700 0.7100 2.3300 1.3100 ;
        RECT 3.1100 0.7100 3.3700 1.3100 ;
        RECT 4.1500 0.7100 4.4100 1.3100 ;
        RECT 2.1200 1.3100 2.2800 2.0900 ;
        RECT 3.1600 1.3100 3.3200 2.0900 ;
        RECT 4.2000 1.3100 4.3600 2.0900 ;
        RECT 1.0300 2.1100 1.2900 2.6700 ;
        RECT 2.0700 2.0900 2.3300 2.6700 ;
        RECT 3.1100 2.0900 3.3700 2.6700 ;
        RECT 4.1500 2.0900 4.4100 2.6700 ;
        RECT 5.1900 2.1100 5.4500 2.6700 ;
        RECT 6.2300 2.1100 6.4900 2.6700 ;
        RECT 7.2700 2.1100 7.5300 2.6700 ;
        RECT 8.3100 2.1100 8.5700 2.6700 ;
        RECT 1.0150 2.6700 8.5850 2.8300 ;
        RECT 2.0700 2.8300 2.3300 3.0300 ;
        RECT 3.1100 2.8300 3.3700 3.0300 ;
        RECT 4.1500 2.8300 4.4100 3.0300 ;
        RECT 1.0300 2.8300 1.2900 3.0500 ;
        RECT 5.1900 2.8300 5.4500 3.0500 ;
        RECT 6.2300 2.8300 6.4900 3.0500 ;
        RECT 7.2700 2.8300 7.5300 3.0500 ;
        RECT 8.3100 2.8300 8.5700 3.0500 ;
      LAYER Via1 ;
        RECT 1.0650 0.9350 1.2550 1.1250 ;
        RECT 2.1050 0.9350 2.2950 1.1250 ;
    END
  END Y
  PIN VDD
    DIRECTION INOUT ;
    USE POWER ;
    SHAPE ABUTMENT ;
    PORT
      LAYER Metal1 ;
        RECT 0.0000 3.5600 9.6000 4.0000 ;
    END
  END VDD
  PIN VSS
    DIRECTION INOUT ;
    USE GROUND ;
    SHAPE ABUTMENT ;
    PORT
      LAYER Metal1 ;
        RECT 0.0000 -0.2200 9.6000 0.2200 ;
    END
  END VSS
  OBS
    LAYER Metal2 ;
      RECT 0.5400 0.8850 0.7400 1.6000 ;
      RECT 0.5400 1.6000 5.2050 1.8000 ;
    LAYER Metal1 ;
      RECT 0.4900 0.8800 0.7900 1.1800 ;
      RECT 1.5500 0.7100 1.8100 1.3100 ;
      RECT 1.6000 1.3100 1.7600 1.5550 ;
      RECT 1.5650 1.5550 1.7950 1.8450 ;
      RECT 2.5900 0.7100 2.8500 1.3100 ;
      RECT 2.6400 1.3100 2.8000 1.5550 ;
      RECT 2.6050 1.5550 2.8350 1.8450 ;
      RECT 3.6300 0.7100 3.8900 1.3100 ;
      RECT 3.6800 1.3100 3.8400 1.5550 ;
      RECT 3.6450 1.5550 3.8750 1.8450 ;
      RECT 4.6700 0.6600 4.9300 0.8800 ;
      RECT 5.7100 0.6600 5.9700 0.8800 ;
      RECT 6.7500 0.6600 7.0100 0.8800 ;
      RECT 7.7900 0.6600 8.0500 0.8800 ;
      RECT 8.8300 0.8300 9.0900 0.8800 ;
      RECT 4.6550 0.8800 9.1050 1.0400 ;
      RECT 8.8300 1.0400 9.0900 1.0900 ;
      RECT 4.6700 1.0400 5.1400 1.2600 ;
      RECT 5.7100 1.0400 5.9700 1.2600 ;
      RECT 6.7500 1.0400 7.0100 1.2600 ;
      RECT 7.7900 1.0400 8.0500 1.2600 ;
      RECT 4.9800 1.2600 5.1400 1.5550 ;
      RECT 4.9450 1.5550 5.1750 1.8450 ;
    LAYER Via1 ;
      RECT 0.5450 0.9350 0.7350 1.1250 ;
      RECT 1.5850 1.6050 1.7750 1.7950 ;
      RECT 2.6250 1.6050 2.8150 1.7950 ;
      RECT 3.6650 1.6050 3.8550 1.7950 ;
      RECT 4.9650 1.6050 5.1550 1.7950 ;
  END
END sg13g2_nand2_8

MACRO sg13g2_nand3_2
  CLASS CORE ;
  ORIGIN 0 0 ;
  FOREIGN sg13g2_nand3_2 0 0 ;
  SIZE 4.8000 BY 3.7800 ;
  SYMMETRY X Y ;
  SITE CoreSite ;
  PIN A
    DIRECTION INPUT ;
    USE SIGNAL ;
    ANTENNAMODEL OXIDE1 ;
    ANTENNAGATEAREA 0.4836 LAYER Metal1 ;
    PORT
      LAYER Metal1 ;
        RECT 0.6900 1.5500 0.9900 1.5700 ;
        RECT 0.6900 1.5700 1.3100 1.8300 ;
        RECT 0.6900 1.8300 0.9900 1.8500 ;
    END
  END A
  PIN B
    DIRECTION INPUT ;
    USE SIGNAL ;
    ANTENNAMODEL OXIDE1 ;
    ANTENNAGATEAREA 0.4836 LAYER Metal1 ;
    PORT
      LAYER Metal1 ;
        RECT 2.2500 1.5500 2.5500 1.5700 ;
        RECT 1.9300 1.5700 2.5500 1.8300 ;
        RECT 2.2500 1.8300 2.5500 1.8500 ;
    END
  END B
  PIN C
    DIRECTION INPUT ;
    USE SIGNAL ;
    ANTENNAMODEL OXIDE1 ;
    ANTENNAGATEAREA 0.4836 LAYER Metal1 ;
    PORT
      LAYER Metal1 ;
        RECT 3.8100 1.5500 4.1100 1.8500 ;
    END
  END C
  PIN Y
    DIRECTION OUTPUT ;
    USE SIGNAL ;
    ANTENNAPARTIALMETALAREA 0.168 LAYER Metal1 ;
    ANTENNADIFFAREA 1.599 LAYER Metal1 ;
    ANTENNADIFFAREA 1.599 LAYER Metal2 ;
    PORT
      LAYER Metal2 ;
        RECT 1.0000 0.8850 1.2000 1.6000 ;
        RECT 1.0000 1.6000 3.5850 1.8000 ;
      LAYER Metal1 ;
        RECT 0.9700 0.7100 1.2300 0.8800 ;
        RECT 0.9500 0.8800 1.2500 1.1800 ;
        RECT 0.9700 1.1800 1.2300 1.3100 ;
        RECT 3.3250 1.5550 3.5550 1.8450 ;
        RECT 3.3600 1.8450 3.5200 2.1100 ;
        RECT 3.3600 2.1100 3.8300 2.6700 ;
        RECT 3.3600 2.6700 3.8450 2.8300 ;
        RECT 0.9700 2.1100 1.2300 3.0500 ;
        RECT 2.0100 2.1100 2.2700 3.0500 ;
        RECT 3.3600 2.8300 3.8300 3.0500 ;
        RECT 1.0200 3.0500 1.2300 3.0800 ;
        RECT 1.9950 3.0500 2.2850 3.0800 ;
        RECT 3.3600 3.0500 3.5200 3.0800 ;
        RECT 1.0200 3.0800 3.5200 3.2400 ;
      LAYER Via1 ;
        RECT 1.0050 0.9350 1.1950 1.1250 ;
        RECT 3.3450 1.6050 3.5350 1.7950 ;
    END
  END Y
  PIN VDD
    DIRECTION INOUT ;
    USE POWER ;
    SHAPE ABUTMENT ;
    PORT
      LAYER Metal1 ;
        RECT 0.0000 3.5600 4.8000 4.0000 ;
    END
  END VDD
  PIN VSS
    DIRECTION INOUT ;
    USE GROUND ;
    SHAPE ABUTMENT ;
    PORT
      LAYER Metal1 ;
        RECT 0.0000 -0.2200 4.8000 0.2200 ;
    END
  END VSS
  OBS
    LAYER Metal2 ;
      RECT 0.1750 2.2400 3.0650 2.4400 ;
      RECT 1.9950 0.9300 3.5850 1.1300 ;
    LAYER Metal1 ;
      RECT 0.4500 0.8300 0.7100 0.8800 ;
      RECT 0.2400 0.8800 0.7250 1.0400 ;
      RECT 0.2400 1.0400 0.7100 1.0900 ;
      RECT 0.2400 1.0900 0.4000 2.1950 ;
      RECT 0.2050 2.1950 0.4350 2.4850 ;
      RECT 1.4900 0.7100 1.7500 1.3100 ;
      RECT 1.5400 1.3100 1.7000 2.1950 ;
      RECT 1.5050 2.1950 1.7350 2.4850 ;
      RECT 2.5300 0.8300 2.7900 0.8800 ;
      RECT 2.5150 0.8800 3.0000 1.0400 ;
      RECT 2.5300 1.0400 3.0000 1.0900 ;
      RECT 2.8400 1.0900 3.0000 2.1950 ;
      RECT 2.8050 2.1950 3.0350 2.4850 ;
      RECT 2.0100 0.7100 2.2700 0.8800 ;
      RECT 1.9900 0.8800 2.2900 1.1800 ;
      RECT 2.0100 1.1800 2.2700 1.3100 ;
      RECT 3.5700 0.7100 3.8300 0.8800 ;
      RECT 3.5700 0.8800 4.5600 0.9150 ;
      RECT 3.2950 0.9150 4.5600 1.0400 ;
      RECT 3.2950 1.0400 4.0400 1.1100 ;
      RECT 3.2950 1.1100 3.8300 1.1450 ;
      RECT 3.5700 1.1450 3.8300 1.3100 ;
      RECT 4.4000 1.0400 4.5600 1.7800 ;
    LAYER Via1 ;
      RECT 0.2250 2.2450 0.4150 2.4350 ;
      RECT 1.5250 2.2450 1.7150 2.4350 ;
      RECT 2.8250 2.2450 3.0150 2.4350 ;
      RECT 2.0450 0.9350 2.2350 1.1250 ;
      RECT 3.3450 0.9350 3.5350 1.1250 ;
  END
END sg13g2_nand3_2

MACRO sg13g2_nand3_4
  CLASS CORE ;
  ORIGIN 0 0 ;
  FOREIGN sg13g2_nand3_4 0 0 ;
  SIZE 8.1600 BY 3.7800 ;
  SYMMETRY X Y ;
  SITE CoreSite ;
  PIN A
    DIRECTION INPUT ;
    USE SIGNAL ;
    ANTENNAMODEL OXIDE1 ;
    ANTENNAGATEAREA 0.9672 LAYER Metal1 ;
    PORT
      LAYER Metal1 ;
        RECT 0.8100 1.5500 1.1100 1.5700 ;
        RECT 0.8100 1.5700 1.4300 1.8300 ;
        RECT 0.8100 1.8300 1.1100 1.8500 ;
    END
  END A
  PIN B
    DIRECTION INPUT ;
    USE SIGNAL ;
    ANTENNAMODEL OXIDE1 ;
    ANTENNAGATEAREA 0.9672 LAYER Metal1 ;
    PORT
      LAYER Metal1 ;
        RECT 4.4500 1.5500 4.7500 1.5700 ;
        RECT 4.4500 1.5700 5.0700 1.8300 ;
        RECT 4.4500 1.8300 4.7500 1.8500 ;
    END
  END B
  PIN C
    DIRECTION INPUT ;
    USE SIGNAL ;
    ANTENNAMODEL OXIDE1 ;
    ANTENNAGATEAREA 0.9672 LAYER Metal1 ;
    PORT
      LAYER Metal1 ;
        RECT 7.0500 1.5500 7.3500 1.5700 ;
        RECT 6.7300 1.5700 7.3500 1.8300 ;
        RECT 7.0500 1.8300 7.3500 1.8500 ;
    END
  END C
  PIN Y
    DIRECTION OUTPUT ;
    USE SIGNAL ;
    ANTENNAPARTIALMETALAREA 0.336 LAYER Metal1 ;
    ANTENNADIFFAREA 3.198 LAYER Metal1 ;
    ANTENNADIFFAREA 3.198 LAYER Metal2 ;
    PORT
      LAYER Metal2 ;
        RECT 1.0750 0.9300 2.8800 1.1300 ;
        RECT 2.6800 1.1300 2.8800 1.2550 ;
        RECT 2.6800 1.2550 6.0000 1.4550 ;
        RECT 5.8000 1.4550 6.0000 2.1900 ;
      LAYER Metal1 ;
        RECT 1.0900 0.7100 1.3500 0.8800 ;
        RECT 1.0700 0.8800 1.3700 1.1800 ;
        RECT 1.0900 1.1800 1.3500 1.3100 ;
        RECT 2.1300 0.7100 2.3900 0.8800 ;
        RECT 2.1100 0.8800 2.4100 1.1800 ;
        RECT 2.1300 1.1800 2.3900 1.3100 ;
        RECT 5.7850 1.9000 6.0150 2.0900 ;
        RECT 1.0900 2.1100 1.3500 3.0500 ;
        RECT 2.1300 2.4500 2.3900 3.0500 ;
        RECT 6.8100 2.1100 7.0700 3.0500 ;
        RECT 1.1400 3.0500 1.3650 3.0800 ;
        RECT 2.1150 3.0500 2.4050 3.0800 ;
        RECT 3.1700 2.4500 3.4300 3.0800 ;
        RECT 4.2100 2.1100 4.4700 3.0800 ;
        RECT 5.7700 2.0900 6.0300 3.0800 ;
        RECT 6.8100 3.0500 7.0850 3.0800 ;
        RECT 7.6400 1.6200 7.8000 3.0800 ;
        RECT 1.1400 3.0800 7.8000 3.2400 ;
      LAYER Via1 ;
        RECT 1.1250 0.9350 1.3150 1.1250 ;
        RECT 2.1650 0.9350 2.3550 1.1250 ;
        RECT 5.8050 1.9500 5.9950 2.1400 ;
    END
  END Y
  PIN VDD
    DIRECTION INOUT ;
    USE POWER ;
    SHAPE ABUTMENT ;
    PORT
      LAYER Metal1 ;
        RECT 0.0000 3.5600 8.1600 4.0000 ;
    END
  END VDD
  PIN VSS
    DIRECTION INOUT ;
    USE GROUND ;
    SHAPE ABUTMENT ;
    PORT
      LAYER Metal1 ;
        RECT 0.0000 -0.2200 8.1600 0.2200 ;
    END
  END VSS
  OBS
    LAYER Metal2 ;
      RECT 3.1550 0.5200 6.0450 0.7200 ;
      RECT 0.2950 1.9450 5.5250 2.1450 ;
    LAYER Metal1 ;
      RECT 3.1850 0.4750 3.4150 0.6600 ;
      RECT 3.1700 0.6600 3.4300 1.2600 ;
      RECT 4.2250 0.4750 4.4550 0.6600 ;
      RECT 4.2100 0.6600 4.4700 1.2600 ;
      RECT 5.7850 0.4750 6.0150 0.6600 ;
      RECT 6.8100 0.6600 7.0700 0.8800 ;
      RECT 6.3400 0.8800 7.0850 1.0400 ;
      RECT 5.7700 0.6600 6.0300 1.2600 ;
      RECT 6.8100 1.0400 7.0700 1.2600 ;
      RECT 5.8200 1.2600 6.0300 1.2750 ;
      RECT 6.3400 1.0400 6.5000 1.2750 ;
      RECT 5.8200 1.2750 6.5000 1.4350 ;
      RECT 1.6100 0.7100 1.8700 1.3100 ;
      RECT 2.6500 0.7100 2.9100 1.3100 ;
      RECT 3.6900 0.7100 3.9500 1.3100 ;
      RECT 1.6600 1.3100 1.8200 1.9650 ;
      RECT 2.1150 1.9300 2.4050 1.9650 ;
      RECT 2.7000 1.3100 2.8600 1.9650 ;
      RECT 3.7400 1.3100 3.9000 1.9650 ;
      RECT 1.6600 1.9650 3.9000 2.1250 ;
      RECT 2.1150 2.1250 2.4050 2.1600 ;
      RECT 0.5700 0.8300 0.8300 0.8800 ;
      RECT 0.3600 0.8800 0.8450 1.0400 ;
      RECT 0.3600 1.0400 0.8300 1.0900 ;
      RECT 0.3600 1.0900 0.5200 1.9000 ;
      RECT 0.3250 1.9000 0.5550 2.1900 ;
      RECT 4.7800 0.5400 5.4600 0.7000 ;
      RECT 4.7800 0.7000 4.9900 0.8300 ;
      RECT 4.7300 0.8300 4.9900 1.0900 ;
      RECT 4.7800 1.0900 4.9400 1.1050 ;
      RECT 5.3000 0.7000 5.4600 1.9000 ;
      RECT 5.2650 1.9000 5.4950 2.1900 ;
    LAYER Via1 ;
      RECT 3.2050 0.5250 3.3950 0.7150 ;
      RECT 4.2450 0.5250 4.4350 0.7150 ;
      RECT 5.8050 0.5250 5.9950 0.7150 ;
      RECT 0.3450 1.9500 0.5350 2.1400 ;
      RECT 2.1650 1.9500 2.3550 2.1400 ;
      RECT 5.2850 1.9500 5.4750 2.1400 ;
  END
END sg13g2_nand3_4

MACRO sg13g2_nand4_2
  CLASS CORE ;
  ORIGIN 0 0 ;
  FOREIGN sg13g2_nand4_2 0 0 ;
  SIZE 6.2400 BY 3.7800 ;
  SYMMETRY X Y ;
  SITE CoreSite ;
  PIN A
    DIRECTION INPUT ;
    USE SIGNAL ;
    ANTENNAMODEL OXIDE1 ;
    ANTENNAGATEAREA 0.4836 LAYER Metal1 ;
    PORT
      LAYER Metal1 ;
        RECT 0.6300 1.5500 0.9300 1.5700 ;
        RECT 0.6300 1.5700 1.2500 1.8300 ;
        RECT 0.6300 1.8300 0.9300 1.8500 ;
    END
  END A
  PIN B
    DIRECTION INPUT ;
    USE SIGNAL ;
    ANTENNAMODEL OXIDE1 ;
    ANTENNAGATEAREA 0.4836 LAYER Metal1 ;
    PORT
      LAYER Metal1 ;
        RECT 2.1900 1.5500 2.4900 1.8500 ;
    END
  END B
  PIN C
    DIRECTION INPUT ;
    USE SIGNAL ;
    ANTENNAMODEL OXIDE1 ;
    ANTENNAGATEAREA 0.4836 LAYER Metal1 ;
    PORT
      LAYER Metal1 ;
        RECT 3.7500 1.5500 4.0500 1.5700 ;
        RECT 3.4300 1.5700 4.0500 1.8300 ;
        RECT 3.7500 1.8300 4.0500 1.8500 ;
    END
  END C
  PIN D
    DIRECTION INPUT ;
    USE SIGNAL ;
    ANTENNAMODEL OXIDE1 ;
    ANTENNAGATEAREA 0.4836 LAYER Metal1 ;
    PORT
      LAYER Metal1 ;
        RECT 5.3100 1.5500 5.6100 1.6000 ;
        RECT 5.2000 1.6000 5.6100 1.7600 ;
        RECT 5.3100 1.7600 5.6100 1.8500 ;
    END
  END D
  PIN Y
    DIRECTION OUTPUT ;
    USE SIGNAL ;
    ANTENNAPARTIALMETALAREA 0.168 LAYER Metal1 ;
    ANTENNADIFFAREA 2.0358 LAYER Metal1 ;
    ANTENNADIFFAREA 2.0358 LAYER Metal2 ;
    PORT
      LAYER Metal2 ;
        RECT 0.9400 0.8850 1.1400 2.4850 ;
      LAYER Metal1 ;
        RECT 0.9100 0.7100 1.1700 0.8800 ;
        RECT 0.8900 0.8800 1.1900 1.1800 ;
        RECT 0.9100 1.1800 1.1700 1.3100 ;
        RECT 5.9000 1.6200 6.0600 2.2600 ;
        RECT 5.3800 2.2600 6.0600 2.3300 ;
        RECT 5.0700 2.3300 6.0600 2.4200 ;
        RECT 0.9100 2.0900 1.1700 2.4700 ;
        RECT 1.9500 2.0900 2.2100 2.4700 ;
        RECT 0.9100 2.4700 1.1850 2.5500 ;
        RECT 1.9000 2.4700 2.2250 2.5500 ;
        RECT 3.5100 2.3300 3.7700 2.5500 ;
        RECT 5.0700 2.4200 5.5400 2.5500 ;
        RECT 0.9100 2.5500 5.5400 2.6900 ;
        RECT 0.9600 2.6900 5.5400 2.7100 ;
        RECT 3.5100 2.7100 3.7700 2.9300 ;
        RECT 5.0700 2.7100 5.3300 2.9300 ;
        RECT 1.9500 2.7100 2.2100 3.0300 ;
      LAYER Via1 ;
        RECT 0.9450 0.9350 1.1350 1.1250 ;
        RECT 0.9450 2.2450 1.1350 2.4350 ;
    END
  END Y
  PIN VDD
    DIRECTION INOUT ;
    USE POWER ;
    SHAPE ABUTMENT ;
    PORT
      LAYER Metal1 ;
        RECT 1.4300 2.9100 1.6900 3.5600 ;
        RECT 0.0000 3.5600 6.2400 4.0000 ;
    END
  END VDD
  PIN VSS
    DIRECTION INOUT ;
    USE GROUND ;
    SHAPE ABUTMENT ;
    PORT
      LAYER Metal1 ;
        RECT 0.0000 -0.2200 6.2400 0.2200 ;
    END
  END VSS
  OBS
    LAYER Metal2 ;
      RECT 3.4950 0.5200 5.3450 0.7200 ;
      RECT 2.4550 0.9300 3.2200 1.1300 ;
      RECT 3.0200 1.1300 3.2200 1.2550 ;
      RECT 3.0200 1.2550 5.0400 1.4550 ;
      RECT 1.4600 0.8850 1.6600 2.2400 ;
      RECT 1.4600 2.2400 2.1800 2.4400 ;
      RECT 1.9800 2.4400 2.1800 2.6500 ;
      RECT 4.8400 1.4550 5.0400 2.6500 ;
      RECT 1.9800 2.6500 5.0400 2.8500 ;
      RECT 1.9800 2.8500 2.1800 3.0600 ;
      RECT 0.6350 3.0600 2.1800 3.2600 ;
      RECT 1.9800 0.8850 2.1800 1.6000 ;
      RECT 1.9800 1.6000 2.7000 1.8000 ;
      RECT 2.5000 1.8000 2.7000 1.9450 ;
      RECT 2.5000 1.9450 4.5650 2.1450 ;
    LAYER Metal1 ;
      RECT 3.5250 0.4750 3.7550 0.6600 ;
      RECT 3.5100 0.6600 3.7700 1.2600 ;
      RECT 5.0850 0.4750 5.3150 0.6600 ;
      RECT 5.0700 0.6600 5.3300 1.2600 ;
      RECT 2.4850 0.7950 2.7150 0.8300 ;
      RECT 2.4700 0.8300 2.7300 1.0900 ;
      RECT 2.4850 1.0900 2.7150 1.1950 ;
      RECT 1.4300 0.7100 1.6900 0.8800 ;
      RECT 1.4100 0.8800 1.7100 1.1800 ;
      RECT 1.4300 1.1800 1.6900 1.3100 ;
      RECT 0.3900 0.8300 0.6500 0.8800 ;
      RECT 0.1800 0.8800 0.6650 1.0400 ;
      RECT 0.1800 1.0400 0.6500 1.0900 ;
      RECT 0.1800 1.0900 0.3400 3.0800 ;
      RECT 0.6350 3.0450 0.9250 3.0800 ;
      RECT 0.1800 3.0800 0.9250 3.2400 ;
      RECT 0.6350 3.2400 0.9250 3.2750 ;
      RECT 1.9500 0.7100 2.2100 0.8800 ;
      RECT 1.9300 0.8800 2.2300 1.1800 ;
      RECT 1.9500 1.1800 2.2100 1.3100 ;
      RECT 3.0400 0.8850 3.2000 0.9000 ;
      RECT 2.9900 0.9000 3.2500 1.1600 ;
      RECT 3.0400 1.1600 3.2000 1.9300 ;
      RECT 2.7150 1.9300 3.2000 2.1250 ;
      RECT 2.7150 2.1250 3.0050 2.1600 ;
      RECT 4.0300 0.9000 4.2900 0.9500 ;
      RECT 4.0150 0.9500 4.7600 1.1100 ;
      RECT 4.0300 1.1100 4.2900 1.1600 ;
      RECT 4.6000 1.1100 4.7600 1.6200 ;
      RECT 4.6000 1.6200 5.0200 1.7800 ;
      RECT 4.6000 1.7800 4.7600 1.9300 ;
      RECT 4.2750 1.9300 4.7600 2.1250 ;
      RECT 4.2750 2.1250 4.5650 2.1600 ;
      RECT 1.4800 1.5900 1.9000 1.8100 ;
    LAYER Via1 ;
      RECT 3.5450 0.5250 3.7350 0.7150 ;
      RECT 5.1050 0.5250 5.2950 0.7150 ;
      RECT 1.4650 0.9350 1.6550 1.1250 ;
      RECT 2.5050 0.9350 2.6950 1.1250 ;
      RECT 0.6850 3.0650 0.8750 3.2550 ;
      RECT 1.9850 0.9350 2.1750 1.1250 ;
      RECT 2.7650 1.9500 2.9550 2.1400 ;
      RECT 4.3250 1.9500 4.5150 2.1400 ;
  END
END sg13g2_nand4_2

MACRO sg13g2_nor2_4
  CLASS CORE ;
  ORIGIN 0 0 ;
  FOREIGN sg13g2_nor2_4 0 0 ;
  SIZE 5.2800 BY 3.7800 ;
  SYMMETRY X Y ;
  SITE CoreSite ;
  PIN A
    DIRECTION INPUT ;
    USE SIGNAL ;
    ANTENNAMODEL OXIDE1 ;
    ANTENNAGATEAREA 0.9672 LAYER Metal1 ;
    PORT
      LAYER Metal1 ;
        RECT 0.6700 1.5500 0.9700 1.5700 ;
        RECT 0.6700 1.5700 1.4700 1.8300 ;
        RECT 0.6700 1.8300 0.9700 1.8500 ;
    END
  END A
  PIN B
    DIRECTION INPUT ;
    USE SIGNAL ;
    ANTENNAMODEL OXIDE1 ;
    ANTENNAGATEAREA 0.9672 LAYER Metal1 ;
    PORT
      LAYER Metal1 ;
        RECT 4.3100 1.5500 4.6100 1.5700 ;
        RECT 4.3100 1.5700 5.1100 1.8300 ;
        RECT 4.3100 1.8300 4.6100 1.8500 ;
    END
  END B
  PIN Y
    DIRECTION OUTPUT ;
    USE SIGNAL ;
    ANTENNAPARTIALMETALAREA 0.2564 LAYER Metal1 ;
    ANTENNADIFFAREA 2.028 LAYER Metal1 ;
    ANTENNADIFFAREA 2.028 LAYER Metal2 ;
    PORT
      LAYER Metal2 ;
        RECT 3.0150 2.2400 4.3450 2.4400 ;
      LAYER Metal1 ;
        RECT 0.9500 0.6600 1.2100 0.8800 ;
        RECT 1.9900 0.6600 2.2500 0.8800 ;
        RECT 3.0300 0.6600 3.2900 0.8800 ;
        RECT 4.0700 0.6600 4.3300 0.8800 ;
        RECT 0.9350 0.8800 4.3450 1.0400 ;
        RECT 0.9500 1.0400 1.2100 1.2600 ;
        RECT 1.9900 1.0400 2.2500 1.2600 ;
        RECT 3.0300 1.0400 3.2900 1.2600 ;
        RECT 4.0700 1.0400 4.3300 1.2600 ;
        RECT 2.5600 1.0400 2.7200 1.6200 ;
        RECT 2.5600 1.6200 3.2400 1.7800 ;
        RECT 3.0800 1.7800 3.2400 2.0900 ;
        RECT 3.0300 2.0900 3.2900 3.0300 ;
        RECT 4.0700 2.0900 4.3300 2.1900 ;
        RECT 4.0500 2.1900 4.3500 2.4900 ;
        RECT 4.0700 2.4900 4.3300 3.0300 ;
      LAYER Via1 ;
        RECT 3.0650 2.2450 3.2550 2.4350 ;
        RECT 4.1050 2.2450 4.2950 2.4350 ;
    END
  END Y
  PIN VDD
    DIRECTION INOUT ;
    USE POWER ;
    SHAPE ABUTMENT ;
    PORT
      LAYER Metal1 ;
        RECT 0.0000 3.5600 5.2800 4.0000 ;
    END
  END VDD
  PIN VSS
    DIRECTION INOUT ;
    USE GROUND ;
    SHAPE ABUTMENT ;
    PORT
      LAYER Metal1 ;
        RECT 0.0000 -0.2200 5.2800 0.2200 ;
    END
  END VSS
  OBS
    LAYER Metal2 ;
      RECT 1.9750 1.6000 4.8200 1.8000 ;
      RECT 4.6200 1.8000 4.8200 2.4850 ;
    LAYER Metal1 ;
      RECT 4.5700 2.1900 4.8700 2.4900 ;
      RECT 3.5650 1.5550 3.7950 1.8450 ;
      RECT 3.6000 1.8450 3.7600 2.0900 ;
      RECT 3.5500 2.0900 3.8100 3.0300 ;
      RECT 2.0050 1.5550 2.2350 1.8450 ;
      RECT 0.4300 2.6200 0.6900 2.6700 ;
      RECT 1.4700 2.1100 1.7300 2.6700 ;
      RECT 2.0400 1.8450 2.2000 2.6700 ;
      RECT 2.5100 2.1100 2.7700 2.6700 ;
      RECT 0.4150 2.6700 2.7850 2.8300 ;
      RECT 0.4300 2.8300 0.6900 2.8800 ;
      RECT 1.4700 2.8300 1.7300 3.0500 ;
      RECT 2.5100 2.8300 2.7700 3.0500 ;
    LAYER Via1 ;
      RECT 2.0250 1.6050 2.2150 1.7950 ;
      RECT 3.5850 1.6050 3.7750 1.7950 ;
      RECT 4.6250 2.2450 4.8150 2.4350 ;
  END
END sg13g2_nor2_4

MACRO sg13g2_nor2_8
  CLASS CORE ;
  ORIGIN 0 0 ;
  FOREIGN sg13g2_nor2_8 0 0 ;
  SIZE 9.6000 BY 3.7800 ;
  SYMMETRY X Y ;
  SITE CoreSite ;
  PIN A
    DIRECTION INPUT ;
    USE SIGNAL ;
    ANTENNAMODEL OXIDE1 ;
    ANTENNAGATEAREA 1.9344 LAYER Metal1 ;
    PORT
      LAYER Metal1 ;
        RECT 2.3100 1.5500 2.6100 1.5700 ;
        RECT 2.3100 1.5700 3.1100 1.8300 ;
        RECT 2.3100 1.8300 2.6100 1.8500 ;
    END
  END A
  PIN B
    DIRECTION INPUT ;
    USE SIGNAL ;
    ANTENNAMODEL OXIDE1 ;
    ANTENNAGATEAREA 1.9344 LAYER Metal1 ;
    PORT
      LAYER Metal1 ;
        RECT 6.4700 1.5500 6.7700 1.5700 ;
        RECT 6.4700 1.5700 7.0900 1.8300 ;
        RECT 6.4700 1.8300 6.7700 1.8500 ;
    END
  END B
  PIN Y
    DIRECTION OUTPUT ;
    USE SIGNAL ;
    ANTENNAPARTIALMETALAREA 0.2564 LAYER Metal1 ;
    ANTENNADIFFAREA 4.056 LAYER Metal1 ;
    ANTENNADIFFAREA 4.056 LAYER Metal2 ;
    PORT
      LAYER Metal2 ;
        RECT 5.1750 2.2400 6.5050 2.4400 ;
      LAYER Metal1 ;
        RECT 6.2300 2.0900 6.4900 2.1900 ;
        RECT 6.2100 2.1900 6.5100 2.4900 ;
        RECT 6.2300 2.4900 6.4900 3.0300 ;
        RECT 1.0300 0.6600 1.2900 0.8800 ;
        RECT 2.0700 0.6600 2.3300 0.8800 ;
        RECT 3.1100 0.6600 3.3700 0.8800 ;
        RECT 4.1500 0.6600 4.4100 0.8800 ;
        RECT 5.1900 0.6600 5.4500 0.8800 ;
        RECT 6.2300 0.6600 6.4900 0.8800 ;
        RECT 7.2700 0.6600 7.5300 0.8800 ;
        RECT 8.3100 0.6600 8.5700 0.8800 ;
        RECT 1.0150 0.8800 8.5850 1.0400 ;
        RECT 1.0300 1.0400 1.2900 1.2600 ;
        RECT 2.0700 1.0400 2.3300 1.2600 ;
        RECT 3.1100 1.0400 3.3700 1.2600 ;
        RECT 4.1500 1.0400 4.4100 1.2600 ;
        RECT 5.1900 1.0400 5.4500 1.2600 ;
        RECT 6.2300 1.0400 6.4900 1.2600 ;
        RECT 7.2700 1.0400 7.5300 1.2600 ;
        RECT 8.3100 1.0400 8.5700 1.2600 ;
        RECT 4.7200 1.0400 4.8800 1.6200 ;
        RECT 7.8400 1.0400 8.0000 1.6200 ;
        RECT 4.7200 1.6200 5.4000 1.7800 ;
        RECT 7.3200 1.6200 8.5200 1.7800 ;
        RECT 5.2400 1.7800 5.4000 2.0900 ;
        RECT 7.3200 1.7800 7.4800 2.0900 ;
        RECT 8.3600 1.7800 8.5200 2.0900 ;
        RECT 5.1900 2.0900 5.4500 3.0300 ;
        RECT 7.2700 2.0900 7.5300 3.0300 ;
        RECT 8.3100 2.0900 8.5700 3.0300 ;
      LAYER Via1 ;
        RECT 5.2250 2.2450 5.4150 2.4350 ;
        RECT 6.2650 2.2450 6.4550 2.4350 ;
    END
  END Y
  PIN VDD
    DIRECTION INOUT ;
    USE POWER ;
    SHAPE ABUTMENT ;
    PORT
      LAYER Metal1 ;
        RECT 0.0000 3.5600 9.6000 4.0000 ;
    END
  END VDD
  PIN VSS
    DIRECTION INOUT ;
    USE GROUND ;
    SHAPE ABUTMENT ;
    PORT
      LAYER Metal1 ;
        RECT 0.0000 -0.2200 9.6000 0.2200 ;
    END
  END VSS
  OBS
    LAYER Metal2 ;
      RECT 4.1350 1.6000 7.2400 1.8000 ;
      RECT 7.0400 1.8000 7.2400 2.2400 ;
      RECT 6.7350 2.2400 9.1050 2.4400 ;
    LAYER Metal1 ;
      RECT 8.8100 2.1900 9.1100 2.4900 ;
      RECT 5.7250 1.5550 5.9550 1.8450 ;
      RECT 5.7600 1.8450 5.9200 2.0900 ;
      RECT 5.7100 2.0900 5.9700 3.0300 ;
      RECT 6.7500 2.0900 7.0100 2.1900 ;
      RECT 6.7300 2.1900 7.0300 2.4900 ;
      RECT 6.7500 2.4900 7.0100 3.0300 ;
      RECT 7.7900 2.0900 8.0500 2.1900 ;
      RECT 7.7700 2.1900 8.0700 2.4900 ;
      RECT 7.7900 2.4900 8.0500 3.0300 ;
      RECT 4.1650 1.5550 4.3950 1.8450 ;
      RECT 0.5100 2.6200 0.7700 2.6700 ;
      RECT 1.5500 2.1100 1.8100 2.6700 ;
      RECT 2.5900 2.1100 2.8500 2.6700 ;
      RECT 3.6300 2.1100 3.8900 2.6700 ;
      RECT 4.2000 1.8450 4.3600 2.6700 ;
      RECT 4.6700 2.1100 4.9300 2.6700 ;
      RECT 0.4950 2.6700 4.9450 2.8300 ;
      RECT 0.5100 2.8300 0.7700 2.8800 ;
      RECT 1.5500 2.8300 1.8100 3.0500 ;
      RECT 2.5900 2.8300 2.8500 3.0500 ;
      RECT 3.6300 2.8300 3.8900 3.0500 ;
      RECT 4.6700 2.8300 4.9300 3.0500 ;
    LAYER Via1 ;
      RECT 4.1850 1.6050 4.3750 1.7950 ;
      RECT 5.7450 1.6050 5.9350 1.7950 ;
      RECT 6.7850 2.2450 6.9750 2.4350 ;
      RECT 7.8250 2.2450 8.0150 2.4350 ;
      RECT 8.8650 2.2450 9.0550 2.4350 ;
  END
END sg13g2_nor2_8

MACRO sg13g2_nor4_2
  CLASS CORE ;
  ORIGIN 0 0 ;
  FOREIGN sg13g2_nor4_2 0 0 ;
  SIZE 5.7600 BY 3.7800 ;
  SYMMETRY X Y ;
  SITE CoreSite ;
  PIN A
    DIRECTION INPUT ;
    USE SIGNAL ;
    ANTENNAMODEL OXIDE1 ;
    ANTENNAGATEAREA 0.4836 LAYER Metal1 ;
    PORT
      LAYER Metal1 ;
        RECT 0.6700 1.5700 1.4500 1.6050 ;
        RECT 0.4600 1.6050 1.4500 1.7950 ;
        RECT 0.6700 1.7950 1.4500 1.8300 ;
    END
  END A
  PIN B
    DIRECTION INPUT ;
    USE SIGNAL ;
    ANTENNAMODEL OXIDE1 ;
    ANTENNAGATEAREA 0.4836 LAYER Metal1 ;
    PORT
      LAYER Metal1 ;
        RECT 2.2100 1.5500 2.5100 1.5700 ;
        RECT 2.2100 1.5700 3.0100 1.8300 ;
        RECT 2.2100 1.8300 2.5100 1.8500 ;
    END
  END B
  PIN C
    DIRECTION INPUT ;
    USE SIGNAL ;
    ANTENNAMODEL OXIDE1 ;
    ANTENNAGATEAREA 0.4836 LAYER Metal1 ;
    PORT
      LAYER Metal1 ;
        RECT 3.2500 1.5500 3.5500 1.5700 ;
        RECT 3.2500 1.5700 3.8700 1.8300 ;
        RECT 3.2500 1.8300 3.5500 1.8500 ;
    END
  END C
  PIN D
    DIRECTION INPUT ;
    USE SIGNAL ;
    ANTENNAMODEL OXIDE1 ;
    ANTENNAGATEAREA 0.4836 LAYER Metal1 ;
    PORT
      LAYER Metal1 ;
        RECT 4.8300 1.5700 5.6100 1.6050 ;
        RECT 4.8150 1.6050 5.6100 1.7950 ;
        RECT 4.8300 1.7950 5.6100 1.8300 ;
    END
  END D
  PIN Y
    DIRECTION OUTPUT ;
    USE SIGNAL ;
    ANTENNAPARTIALMETALAREA 0.168 LAYER Metal1 ;
    ANTENNADIFFAREA 1.5912 LAYER Metal1 ;
    ANTENNADIFFAREA 1.5912 LAYER Metal2 ;
    PORT
      LAYER Metal2 ;
        RECT 4.0350 1.9450 4.8000 2.1450 ;
        RECT 4.6000 2.1450 4.8000 2.4850 ;
      LAYER Metal1 ;
        RECT 0.9800 0.5400 4.7800 0.6600 ;
        RECT 0.9300 0.6600 4.8300 0.7000 ;
        RECT 1.9550 0.7000 2.2800 0.8300 ;
        RECT 3.4800 0.7000 3.7900 0.8300 ;
        RECT 4.5550 0.7000 4.8300 0.8300 ;
        RECT 2.8000 0.7000 2.9600 1.0400 ;
        RECT 0.9300 0.7000 1.1900 1.2600 ;
        RECT 1.9700 0.8300 2.2300 1.2600 ;
        RECT 3.5300 0.8300 3.7900 1.2600 ;
        RECT 4.5700 0.8300 4.8300 1.2600 ;
        RECT 4.1000 0.7000 4.2600 1.9000 ;
        RECT 4.0650 1.9000 4.2950 2.1900 ;
        RECT 4.5700 2.0900 4.8300 2.1900 ;
        RECT 4.5500 2.1900 4.8500 2.4900 ;
        RECT 4.5700 2.4900 4.8300 2.6900 ;
      LAYER Via1 ;
        RECT 4.0850 1.9500 4.2750 2.1400 ;
        RECT 4.6050 2.2450 4.7950 2.4350 ;
    END
  END Y
  PIN VDD
    DIRECTION INOUT ;
    USE POWER ;
    SHAPE ABUTMENT ;
    PORT
      LAYER Metal1 ;
        RECT 0.0000 3.5600 5.7600 4.0000 ;
    END
  END VDD
  PIN VSS
    DIRECTION INOUT ;
    USE GROUND ;
    SHAPE ABUTMENT ;
    PORT
      LAYER Metal1 ;
        RECT 0.0000 -0.2200 5.7600 0.2200 ;
    END
  END VSS
  OBS
    LAYER Metal2 ;
      RECT 1.9550 2.2400 3.8050 2.4400 ;
    LAYER Metal1 ;
      RECT 0.4600 2.6050 0.6200 2.6200 ;
      RECT 2.5400 2.6050 2.7000 2.6200 ;
      RECT 0.4100 2.6200 0.6700 2.8800 ;
      RECT 2.4900 2.6200 2.7500 2.8800 ;
      RECT 0.4600 2.8800 0.6200 3.0800 ;
      RECT 1.4500 2.1100 1.7100 3.0800 ;
      RECT 2.5400 2.8800 2.7000 3.0800 ;
      RECT 0.4600 3.0800 2.7000 3.2400 ;
      RECT 1.9700 2.0900 2.2300 2.1900 ;
      RECT 1.9500 2.1900 2.2500 2.4900 ;
      RECT 1.9700 2.4900 2.2300 2.6900 ;
      RECT 3.5300 2.0900 3.7900 2.1900 ;
      RECT 3.5100 2.1900 3.8100 2.4900 ;
      RECT 3.5300 2.4900 3.7900 2.6900 ;
      RECT 3.0600 2.6050 3.2200 2.6200 ;
      RECT 5.1400 2.6050 5.3000 2.6200 ;
      RECT 3.0100 2.6200 3.2700 2.8800 ;
      RECT 5.0900 2.6200 5.3500 2.8800 ;
      RECT 3.0600 2.8800 3.2200 3.0800 ;
      RECT 4.0500 2.4500 4.3100 3.0800 ;
      RECT 5.1400 2.8800 5.3000 3.0800 ;
      RECT 3.0600 3.0800 5.3000 3.2400 ;
    LAYER Via1 ;
      RECT 2.0050 2.2450 2.1950 2.4350 ;
      RECT 3.5650 2.2450 3.7550 2.4350 ;
  END
END sg13g2_nor4_2

MACRO sg13g2_o21a_1
  CLASS CORE ;
  ORIGIN 0 0 ;
  FOREIGN sg13g2_o21a_1 0 0 ;
  SIZE 3.8400 BY 3.7800 ;
  SYMMETRY X Y ;
  SITE CoreSite ;
  PIN A1
    DIRECTION INPUT ;
    USE SIGNAL ;
    ANTENNAMODEL OXIDE1 ;
    ANTENNAGATEAREA 0.2418 LAYER Metal1 ;
    PORT
      LAYER Metal1 ;
        RECT 2.2900 1.5500 2.5900 1.8500 ;
    END
  END A1
  PIN A2
    DIRECTION INPUT ;
    USE SIGNAL ;
    ANTENNAMODEL OXIDE1 ;
    ANTENNAGATEAREA 0.2418 LAYER Metal1 ;
    PORT
      LAYER Metal1 ;
        RECT 1.7700 1.5500 2.0700 1.8500 ;
    END
  END A2
  PIN B1
    DIRECTION INPUT ;
    USE SIGNAL ;
    ANTENNAMODEL OXIDE1 ;
    ANTENNAGATEAREA 0.2418 LAYER Metal1 ;
    PORT
      LAYER Metal1 ;
        RECT 2.8800 1.5550 3.0400 1.5700 ;
        RECT 2.8300 1.5700 3.6100 1.8300 ;
        RECT 2.8800 1.8300 3.5600 2.1250 ;
    END
  END B1
  PIN X
    DIRECTION OUTPUT ;
    USE SIGNAL ;
    ANTENNADIFFAREA 0.6102 LAYER Metal1 ;
    PORT
      LAYER Metal1 ;
        RECT 0.2800 0.5400 1.2200 0.7000 ;
        RECT 0.9600 0.7000 1.2200 0.8300 ;
        RECT 1.0100 0.8300 1.2700 1.0900 ;
        RECT 1.0600 1.0900 1.2200 1.1050 ;
        RECT 0.2800 0.7000 0.4400 2.6700 ;
        RECT 1.0100 2.6200 1.2700 2.6700 ;
        RECT 0.2800 2.6700 1.4800 2.8300 ;
        RECT 1.0100 2.8300 1.4800 2.8800 ;
        RECT 1.3200 2.8800 1.4800 3.2400 ;
    END
  END X
  PIN VDD
    DIRECTION INOUT ;
    USE POWER ;
    SHAPE ABUTMENT ;
    PORT
      LAYER Metal1 ;
        RECT 0.0000 3.5600 3.8400 4.0000 ;
    END
  END VDD
  PIN VSS
    DIRECTION INOUT ;
    USE GROUND ;
    SHAPE ABUTMENT ;
    PORT
      LAYER Metal1 ;
        RECT 0.0000 -0.2200 3.8400 0.2200 ;
    END
  END VSS
  OBS
    LAYER Metal2 ;
      RECT 0.7800 0.9300 1.8050 1.1300 ;
      RECT 0.7800 1.1300 0.9800 2.6500 ;
      RECT 0.7800 2.6500 1.5000 2.8500 ;
      RECT 1.3000 2.8500 1.5000 3.0600 ;
      RECT 2.6000 0.8850 2.8000 3.0600 ;
      RECT 1.3000 3.0600 2.8000 3.2600 ;
      RECT 2.0800 0.8850 2.2800 1.9450 ;
      RECT 1.2550 1.9450 2.2800 2.1450 ;
      RECT 2.0800 2.1450 2.2800 2.4850 ;
    LAYER Metal1 ;
      RECT 1.5100 0.8800 1.8100 1.1800 ;
      RECT 2.5700 0.7100 2.8300 0.8800 ;
      RECT 2.5500 0.8800 2.8500 1.1800 ;
      RECT 2.5700 1.1800 2.8300 1.3100 ;
      RECT 2.0500 0.7100 2.3100 0.8800 ;
      RECT 2.0300 0.8800 2.3300 1.1800 ;
      RECT 2.0500 1.1800 2.3100 1.3100 ;
      RECT 0.8000 1.5550 0.9600 1.5700 ;
      RECT 0.7500 1.5700 1.5300 1.8300 ;
      RECT 0.8000 1.8300 1.5300 1.9300 ;
      RECT 0.8000 1.9300 1.5450 2.1250 ;
      RECT 1.2550 2.1250 1.5450 2.1600 ;
      RECT 2.0650 2.1950 2.2950 2.4850 ;
      RECT 2.1000 2.4850 2.2600 2.6700 ;
      RECT 2.5700 2.4500 2.8300 2.6700 ;
      RECT 2.1000 2.6700 2.8450 2.8300 ;
      RECT 2.5700 2.8300 2.8300 3.0500 ;
    LAYER Via1 ;
      RECT 1.5650 0.9350 1.7550 1.1250 ;
      RECT 2.6050 0.9350 2.7950 1.1250 ;
      RECT 2.0850 0.9350 2.2750 1.1250 ;
      RECT 1.3050 1.9500 1.4950 2.1400 ;
      RECT 2.0850 2.2450 2.2750 2.4350 ;
  END
END sg13g2_o21a_1

MACRO sg13g2_o21a_2
  CLASS CORE ;
  ORIGIN 0 0 ;
  FOREIGN sg13g2_o21a_2 0 0 ;
  SIZE 3.8400 BY 3.7800 ;
  SYMMETRY X Y ;
  SITE CoreSite ;
  PIN A1
    DIRECTION INPUT ;
    USE SIGNAL ;
    ANTENNAMODEL OXIDE1 ;
    ANTENNAGATEAREA 0.2418 LAYER Metal1 ;
    PORT
      LAYER Metal1 ;
        RECT 2.2900 1.5500 2.5900 1.8500 ;
    END
  END A1
  PIN A2
    DIRECTION INPUT ;
    USE SIGNAL ;
    ANTENNAMODEL OXIDE1 ;
    ANTENNAGATEAREA 0.2418 LAYER Metal1 ;
    PORT
      LAYER Metal1 ;
        RECT 2.8300 1.5700 3.6100 1.6200 ;
        RECT 2.8150 1.6200 3.6100 1.7800 ;
        RECT 2.8300 1.7800 3.6100 1.8300 ;
    END
  END A2
  PIN B1
    DIRECTION INPUT ;
    USE SIGNAL ;
    ANTENNAMODEL OXIDE1 ;
    ANTENNAGATEAREA 0.2418 LAYER Metal1 ;
    PORT
      LAYER Metal1 ;
        RECT 1.7700 1.5500 2.0700 1.8500 ;
    END
  END B1
  PIN X
    DIRECTION OUTPUT ;
    USE SIGNAL ;
    ANTENNADIFFAREA 0.7254 LAYER Metal1 ;
    PORT
      LAYER Metal1 ;
        RECT 1.0100 0.6600 1.2700 0.8800 ;
        RECT 0.9950 0.8800 1.4800 1.0400 ;
        RECT 1.0100 1.0400 1.4800 1.2600 ;
        RECT 1.3200 1.2600 1.4800 2.3000 ;
        RECT 1.0100 2.3000 1.4800 2.5500 ;
        RECT 0.9950 2.5500 1.4800 2.7100 ;
        RECT 1.0100 2.7100 1.2700 2.9000 ;
    END
  END X
  PIN VDD
    DIRECTION INOUT ;
    USE POWER ;
    SHAPE ABUTMENT ;
    PORT
      LAYER Metal1 ;
        RECT 0.0000 3.5600 3.8400 4.0000 ;
    END
  END VDD
  PIN VSS
    DIRECTION INOUT ;
    USE GROUND ;
    SHAPE ABUTMENT ;
    PORT
      LAYER Metal1 ;
        RECT 0.0000 -0.2200 3.8400 0.2200 ;
    END
  END VSS
  OBS
    LAYER Metal2 ;
      RECT 2.0800 0.8850 2.2800 3.0600 ;
      RECT 3.1200 0.8850 3.3200 3.0600 ;
      RECT 2.0800 3.0600 3.3200 3.2600 ;
      RECT 2.6000 0.8850 2.8000 2.4850 ;
    LAYER Metal1 ;
      RECT 3.0700 0.8800 3.3700 1.1800 ;
      RECT 2.0500 0.7100 2.3100 0.8800 ;
      RECT 2.0300 0.8800 2.3300 1.1800 ;
      RECT 2.0500 1.1800 2.3100 1.3100 ;
      RECT 2.5700 0.7100 2.8300 0.8800 ;
      RECT 2.5500 0.8800 2.8500 1.1800 ;
      RECT 2.5700 1.1800 2.8300 1.3100 ;
      RECT 0.8000 1.5550 0.9600 1.5700 ;
      RECT 0.2300 1.5700 1.0100 1.8300 ;
      RECT 0.2800 1.8300 0.9600 2.1250 ;
      RECT 2.5850 2.1950 2.8150 2.4850 ;
      RECT 2.0500 2.1100 2.3100 3.0500 ;
      RECT 0.2800 2.1250 0.4400 3.0800 ;
      RECT 2.0350 3.0500 2.3600 3.0800 ;
      RECT 2.6200 2.4850 2.7800 3.0800 ;
      RECT 0.2800 3.0800 2.7800 3.2400 ;
    LAYER Via1 ;
      RECT 2.0850 0.9350 2.2750 1.1250 ;
      RECT 3.1250 0.9350 3.3150 1.1250 ;
      RECT 2.6050 0.9350 2.7950 1.1250 ;
      RECT 2.6050 2.2450 2.7950 2.4350 ;
  END
END sg13g2_o21a_2

MACRO sg13g2_o21ai_2
  CLASS CORE ;
  ORIGIN 0 0 ;
  FOREIGN sg13g2_o21ai_2 0 0 ;
  SIZE 4.8000 BY 3.7800 ;
  SYMMETRY X Y ;
  SITE CoreSite ;
  PIN A1
    DIRECTION INPUT ;
    USE SIGNAL ;
    ANTENNAMODEL OXIDE1 ;
    ANTENNAGATEAREA 0.4836 LAYER Metal1 ;
    PORT
      LAYER Metal1 ;
        RECT 3.8100 1.5500 4.1100 1.8500 ;
    END
  END A1
  PIN A2
    DIRECTION INPUT ;
    USE SIGNAL ;
    ANTENNAMODEL OXIDE1 ;
    ANTENNAGATEAREA 0.4836 LAYER Metal1 ;
    PORT
      LAYER Metal1 ;
        RECT 2.2500 1.5500 2.5500 1.5700 ;
        RECT 2.2500 1.5700 3.0500 1.8300 ;
        RECT 2.2500 1.8300 2.5500 1.8500 ;
    END
  END A2
  PIN B1
    DIRECTION INPUT ;
    USE SIGNAL ;
    ANTENNAMODEL OXIDE1 ;
    ANTENNAGATEAREA 0.4836 LAYER Metal1 ;
    PORT
      LAYER Metal1 ;
        RECT 0.6900 1.5500 0.9900 1.5700 ;
        RECT 0.6900 1.5700 1.3100 1.8300 ;
        RECT 0.6900 1.8300 0.9900 1.8500 ;
    END
  END B1
  PIN Y
    DIRECTION OUTPUT ;
    USE SIGNAL ;
    ANTENNAPARTIALMETALAREA 0.168 LAYER Metal1 ;
    ANTENNADIFFAREA 1.3622 LAYER Metal1 ;
    ANTENNADIFFAREA 1.3622 LAYER Metal2 ;
    PORT
      LAYER Metal2 ;
        RECT 1.4750 2.2400 2.8050 2.4400 ;
      LAYER Metal1 ;
        RECT 2.5300 2.0900 2.7900 2.1900 ;
        RECT 2.5100 2.1900 2.8100 2.4900 ;
        RECT 2.5300 2.4900 2.7900 2.6900 ;
        RECT 0.4500 0.8300 0.7100 0.8800 ;
        RECT 1.5400 0.8850 1.7000 0.9000 ;
        RECT 0.2400 0.8800 0.7250 1.0400 ;
        RECT 0.2400 1.0400 0.7100 1.0900 ;
        RECT 1.4900 0.9000 1.7500 1.1600 ;
        RECT 1.5400 1.1600 1.7000 2.1950 ;
        RECT 1.5050 2.1950 1.7350 2.4850 ;
        RECT 0.9700 2.1100 1.2300 3.0500 ;
        RECT 0.2400 1.0900 0.4000 3.0800 ;
        RECT 0.9200 3.0500 1.2300 3.0800 ;
        RECT 1.5400 2.4850 1.7000 3.0800 ;
        RECT 0.2400 3.0800 1.7000 3.2400 ;
      LAYER Via1 ;
        RECT 1.5250 2.2450 1.7150 2.4350 ;
        RECT 2.5650 2.2450 2.7550 2.4350 ;
    END
  END Y
  PIN VDD
    DIRECTION INOUT ;
    USE POWER ;
    SHAPE ABUTMENT ;
    PORT
      LAYER Metal1 ;
        RECT 0.0000 3.5600 4.8000 4.0000 ;
    END
  END VDD
  PIN VSS
    DIRECTION INOUT ;
    USE GROUND ;
    SHAPE ABUTMENT ;
    PORT
      LAYER Metal1 ;
        RECT 0.0000 -0.2200 4.8000 0.2200 ;
    END
  END VSS
  OBS
    LAYER Metal2 ;
      RECT 0.9550 0.5200 2.2850 0.7200 ;
    LAYER Metal1 ;
      RECT 0.9850 0.4750 1.2150 0.6600 ;
      RECT 0.9700 0.6600 1.2300 1.2600 ;
      RECT 1.9950 0.5050 2.2850 0.5400 ;
      RECT 1.9950 0.5400 3.5200 0.6600 ;
      RECT 1.9950 0.6600 3.8300 0.7000 ;
      RECT 1.9950 0.7000 2.2850 0.7350 ;
      RECT 2.4800 0.7000 2.7900 0.8300 ;
      RECT 3.3600 0.7000 3.8300 0.8800 ;
      RECT 3.3600 0.8800 3.8450 1.0400 ;
      RECT 2.5300 0.8300 2.7900 1.2600 ;
      RECT 3.3600 1.0400 3.8300 1.2600 ;
      RECT 3.3600 1.2600 3.5200 1.7800 ;
      RECT 2.0600 2.6050 2.2200 2.6200 ;
      RECT 4.4000 1.6200 4.5600 2.6200 ;
      RECT 4.0900 2.6200 4.5600 2.6700 ;
      RECT 3.8800 2.6700 4.5600 2.8300 ;
      RECT 2.0100 2.6200 2.2700 2.8800 ;
      RECT 3.8800 2.8300 4.3500 2.8800 ;
      RECT 3.0500 2.1100 3.3100 3.0500 ;
      RECT 2.0600 2.8800 2.2200 3.0800 ;
      RECT 3.0500 3.0500 3.3600 3.0800 ;
      RECT 3.8800 2.8800 4.0400 3.0800 ;
      RECT 2.0600 3.0800 4.0400 3.2400 ;
    LAYER Via1 ;
      RECT 1.0050 0.5250 1.1950 0.7150 ;
      RECT 2.0450 0.5250 2.2350 0.7150 ;
  END
END sg13g2_o21ai_2

MACRO sg13g2_o21ai_4
  CLASS CORE ;
  ORIGIN 0 0 ;
  FOREIGN sg13g2_o21ai_4 0 0 ;
  SIZE 8.1600 BY 3.7800 ;
  SYMMETRY X Y ;
  SITE CoreSite ;
  PIN A1
    DIRECTION INPUT ;
    USE SIGNAL ;
    ANTENNAMODEL OXIDE1 ;
    ANTENNAGATEAREA 0.9672 LAYER Metal1 ;
    PORT
      LAYER Metal1 ;
        RECT 7.0500 1.5500 7.3500 1.5700 ;
        RECT 7.0500 1.5700 7.8500 1.8300 ;
        RECT 7.0500 1.8300 7.3500 1.8500 ;
    END
  END A1
  PIN A2
    DIRECTION INPUT ;
    USE SIGNAL ;
    ANTENNAMODEL OXIDE1 ;
    ANTENNAGATEAREA 0.9672 LAYER Metal1 ;
    PORT
      LAYER Metal1 ;
        RECT 4.4500 1.5500 4.7500 1.5700 ;
        RECT 4.4500 1.5700 5.2500 1.8300 ;
        RECT 4.4500 1.8300 4.7500 1.8500 ;
    END
  END A2
  PIN B1
    DIRECTION INPUT ;
    USE SIGNAL ;
    ANTENNAMODEL OXIDE1 ;
    ANTENNAGATEAREA 0.9672 LAYER Metal1 ;
    PORT
      LAYER Metal1 ;
        RECT 0.8100 1.5500 1.1100 1.5700 ;
        RECT 0.8100 1.5700 1.4300 1.8300 ;
        RECT 0.8100 1.8300 1.1100 1.8500 ;
    END
  END B1
  PIN Y
    DIRECTION OUTPUT ;
    USE SIGNAL ;
    ANTENNAPARTIALMETALAREA 0.168 LAYER Metal1 ;
    ANTENNADIFFAREA 2.5244 LAYER Metal1 ;
    ANTENNADIFFAREA 2.5244 LAYER Metal2 ;
    PORT
      LAYER Metal2 ;
        RECT 3.6750 2.2400 5.0050 2.4400 ;
      LAYER Metal1 ;
        RECT 4.7300 2.0900 4.9900 2.1900 ;
        RECT 4.7100 2.1900 5.0100 2.4900 ;
        RECT 4.7300 2.4900 4.9900 2.6900 ;
        RECT 0.5700 0.8300 0.8300 0.8800 ;
        RECT 2.7000 0.8850 2.8600 0.9000 ;
        RECT 0.3600 0.8800 0.8450 1.0400 ;
        RECT 0.3600 1.0400 0.8300 1.0900 ;
        RECT 2.6500 0.9000 2.9100 1.1600 ;
        RECT 1.6100 0.7100 1.8700 1.3100 ;
        RECT 2.7000 1.1600 2.8600 1.6200 ;
        RECT 2.7000 1.6200 3.9000 1.7800 ;
        RECT 3.7400 1.7800 3.9000 2.0900 ;
        RECT 3.6900 2.0900 3.9500 2.6900 ;
        RECT 1.0900 2.1100 1.3500 3.0500 ;
        RECT 0.3600 1.0900 0.5200 3.0800 ;
        RECT 1.0400 3.0500 1.3500 3.0800 ;
        RECT 1.6600 1.3100 1.8200 3.0800 ;
        RECT 2.1300 2.1100 2.3900 3.0800 ;
        RECT 2.7000 1.7800 2.8600 3.0800 ;
        RECT 0.3600 3.0800 2.8600 3.2400 ;
      LAYER Via1 ;
        RECT 3.7250 2.2450 3.9150 2.4350 ;
        RECT 4.7650 2.2450 4.9550 2.4350 ;
    END
  END Y
  PIN VDD
    DIRECTION INOUT ;
    USE POWER ;
    SHAPE ABUTMENT ;
    PORT
      LAYER Metal1 ;
        RECT 0.0000 3.5600 8.1600 4.0000 ;
    END
  END VDD
  PIN VSS
    DIRECTION INOUT ;
    USE GROUND ;
    SHAPE ABUTMENT ;
    PORT
      LAYER Metal1 ;
        RECT 0.0000 -0.2200 8.1600 0.2200 ;
    END
  END VSS
  OBS
    LAYER Metal2 ;
      RECT 1.0750 0.5200 3.4450 0.7200 ;
    LAYER Metal1 ;
      RECT 1.1050 0.4750 1.3350 0.6600 ;
      RECT 1.0900 0.6600 1.3500 1.2600 ;
      RECT 3.1550 0.5050 3.4450 0.5400 ;
      RECT 3.1550 0.5400 7.0200 0.6600 ;
      RECT 3.1550 0.6600 7.0700 0.7000 ;
      RECT 3.1550 0.7000 3.4450 0.7350 ;
      RECT 3.6900 0.7000 3.9500 1.2600 ;
      RECT 4.7300 0.7000 4.9900 1.2600 ;
      RECT 5.7700 0.7000 6.0300 1.2600 ;
      RECT 6.8100 0.7000 7.0700 1.2600 ;
      RECT 2.1450 0.4750 2.3750 0.6600 ;
      RECT 2.1300 0.6600 2.3900 1.2600 ;
      RECT 2.1800 1.2600 2.3400 1.7800 ;
      RECT 6.3400 1.6200 6.5000 2.1100 ;
      RECT 3.2200 2.6050 3.3800 2.6200 ;
      RECT 7.3800 2.6050 7.5400 2.6200 ;
      RECT 3.1700 2.6200 3.4300 2.8800 ;
      RECT 7.3300 2.6200 7.5900 2.8800 ;
      RECT 3.2200 2.8800 3.3800 3.0800 ;
      RECT 4.2100 2.1100 4.4700 3.0800 ;
      RECT 5.2500 2.1100 5.5100 3.0800 ;
      RECT 6.2900 2.1100 6.5500 3.0800 ;
      RECT 7.3800 2.8800 7.5400 3.0800 ;
      RECT 3.2200 3.0800 7.5400 3.2400 ;
    LAYER Via1 ;
      RECT 1.1250 0.5250 1.3150 0.7150 ;
      RECT 2.1650 0.5250 2.3550 0.7150 ;
      RECT 3.2050 0.5250 3.3950 0.7150 ;
  END
END sg13g2_o21ai_4

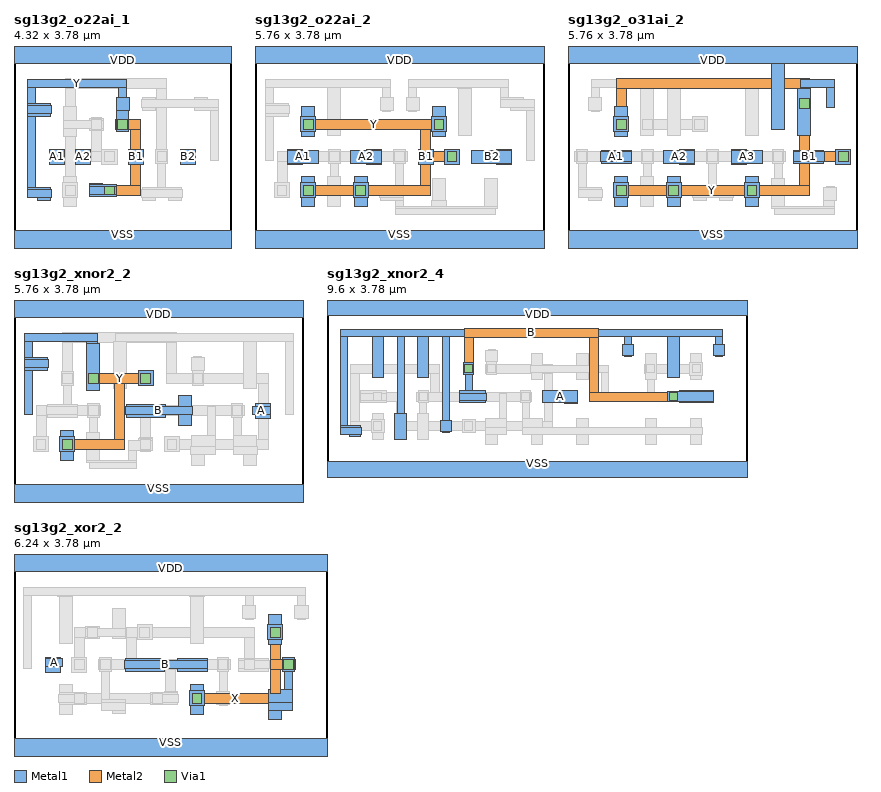
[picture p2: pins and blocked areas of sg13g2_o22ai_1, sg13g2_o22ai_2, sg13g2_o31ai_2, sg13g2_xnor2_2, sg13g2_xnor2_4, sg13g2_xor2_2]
MACRO sg13g2_o22ai_1
  CLASS CORE ;
  ORIGIN 0 0 ;
  FOREIGN sg13g2_o22ai_1 0 0 ;
  SIZE 4.3200 BY 3.7800 ;
  SYMMETRY X Y ;
  SITE CoreSite ;
  PIN A1
    DIRECTION INPUT ;
    USE SIGNAL ;
    ANTENNAMODEL OXIDE1 ;
    ANTENNAGATEAREA 0.2418 LAYER Metal1 ;
    PORT
      LAYER Metal1 ;
        RECT 0.7100 1.5500 1.0100 1.8500 ;
    END
  END A1
  PIN A2
    DIRECTION INPUT ;
    USE SIGNAL ;
    ANTENNAMODEL OXIDE1 ;
    ANTENNAGATEAREA 0.2418 LAYER Metal1 ;
    PORT
      LAYER Metal1 ;
        RECT 1.2300 1.5500 1.5300 1.8500 ;
    END
  END A2
  PIN B1
    DIRECTION INPUT ;
    USE SIGNAL ;
    ANTENNAMODEL OXIDE1 ;
    ANTENNAGATEAREA 0.2418 LAYER Metal1 ;
    PORT
      LAYER Metal1 ;
        RECT 2.2700 1.5500 2.5700 1.8500 ;
    END
  END B1
  PIN B2
    DIRECTION INPUT ;
    USE SIGNAL ;
    ANTENNAMODEL OXIDE1 ;
    ANTENNAGATEAREA 0.2418 LAYER Metal1 ;
    PORT
      LAYER Metal1 ;
        RECT 3.3100 1.5500 3.6100 1.8500 ;
    END
  END B2
  PIN Y
    DIRECTION OUTPUT ;
    USE SIGNAL ;
    ANTENNAPARTIALMETALAREA 0.13325 LAYER Metal1 ;
    ANTENNADIFFAREA 1.2204 LAYER Metal1 ;
    ANTENNADIFFAREA 1.2204 LAYER Metal2 ;
    PORT
      LAYER Metal2 ;
        RECT 1.7550 0.9300 2.5200 1.1300 ;
        RECT 2.3200 1.1300 2.5200 2.2400 ;
        RECT 2.0150 2.2400 2.5200 2.4400 ;
      LAYER Metal1 ;
        RECT 1.5100 0.9000 1.7700 0.9150 ;
        RECT 1.5100 0.9150 2.0450 0.9500 ;
        RECT 1.4950 0.9500 2.0450 1.1100 ;
        RECT 1.5100 1.1100 2.0450 1.1450 ;
        RECT 1.5100 1.1450 1.7700 1.1600 ;
        RECT 0.4700 0.8300 0.7300 0.8800 ;
        RECT 0.2600 0.8800 0.7450 1.0400 ;
        RECT 0.2600 1.0400 0.7300 1.0900 ;
        RECT 0.2600 1.0900 0.4200 2.5000 ;
        RECT 0.2600 2.5000 0.7300 2.5500 ;
        RECT 2.0450 2.1950 2.2750 2.6200 ;
        RECT 0.2600 2.5500 0.7450 2.7100 ;
        RECT 0.2600 2.7100 0.7300 2.7600 ;
        RECT 2.0300 2.6200 2.2900 2.8800 ;
        RECT 0.2600 2.7600 0.4200 3.0800 ;
        RECT 2.0800 2.8800 2.2400 3.0800 ;
        RECT 0.2600 3.0800 2.2400 3.2400 ;
      LAYER Via1 ;
        RECT 1.8050 0.9350 1.9950 1.1250 ;
        RECT 2.0650 2.2450 2.2550 2.4350 ;
    END
  END Y
  PIN VDD
    DIRECTION INOUT ;
    USE POWER ;
    SHAPE ABUTMENT ;
    PORT
      LAYER Metal1 ;
        RECT 0.0000 3.5600 4.3200 4.0000 ;
    END
  END VDD
  PIN VSS
    DIRECTION INOUT ;
    USE GROUND ;
    SHAPE ABUTMENT ;
    PORT
      LAYER Metal1 ;
        RECT 0.0000 -0.2200 4.3200 0.2200 ;
    END
  END VSS
  OBS
    LAYER Metal2 ;
      RECT 1.5400 1.6000 2.0450 1.8000 ;
      RECT 1.5400 1.8000 1.7400 2.4850 ;
      RECT 1.0200 0.8850 1.2200 3.0600 ;
      RECT 2.8400 1.5550 3.0400 3.0600 ;
      RECT 1.0200 3.0600 3.0400 3.2600 ;
    LAYER Metal1 ;
      RECT 1.7500 1.5500 2.0500 1.8500 ;
      RECT 0.9900 2.0900 1.2500 2.2600 ;
      RECT 1.4950 2.2250 1.7850 2.2600 ;
      RECT 0.9750 2.2600 1.7850 2.4200 ;
      RECT 1.4950 2.4200 1.7850 2.4550 ;
      RECT 0.9900 2.4200 1.2500 2.6900 ;
      RECT 0.9900 0.7100 1.2500 0.8800 ;
      RECT 0.9700 0.8800 1.2700 1.1800 ;
      RECT 0.9900 1.1800 1.2500 1.3100 ;
      RECT 2.5500 0.8300 2.8100 0.8800 ;
      RECT 3.0700 0.8300 3.3300 0.8800 ;
      RECT 2.5350 0.8800 3.3450 1.0400 ;
      RECT 2.5500 1.0400 3.3300 1.0900 ;
      RECT 2.8600 1.0900 3.0200 1.5550 ;
      RECT 2.8250 1.5550 3.0550 1.8450 ;
      RECT 3.9000 1.6200 4.0600 2.6200 ;
      RECT 2.5500 2.6200 2.8100 2.6700 ;
      RECT 3.5900 2.6200 4.0600 2.6700 ;
      RECT 2.5350 2.6700 4.0600 2.8300 ;
      RECT 2.5500 2.8300 2.8100 2.8800 ;
      RECT 3.5900 2.8300 3.8500 2.8800 ;
    LAYER Via1 ;
      RECT 1.8050 1.6050 1.9950 1.7950 ;
      RECT 1.5450 2.2450 1.7350 2.4350 ;
      RECT 1.0250 0.9350 1.2150 1.1250 ;
      RECT 2.8450 1.6050 3.0350 1.7950 ;
  END
END sg13g2_o22ai_1

MACRO sg13g2_o22ai_2
  CLASS CORE ;
  ORIGIN 0 0 ;
  FOREIGN sg13g2_o22ai_2 0 0 ;
  SIZE 5.7600 BY 3.7800 ;
  SYMMETRY X Y ;
  SITE CoreSite ;
  PIN A1
    DIRECTION INPUT ;
    USE SIGNAL ;
    ANTENNAMODEL OXIDE1 ;
    ANTENNAGATEAREA 0.4836 LAYER Metal1 ;
    PORT
      LAYER Metal1 ;
        RECT 0.6500 1.5500 0.9500 1.5700 ;
        RECT 0.6500 1.5700 1.2700 1.8300 ;
        RECT 0.6500 1.8300 0.9500 1.8500 ;
    END
  END A1
  PIN A2
    DIRECTION INPUT ;
    USE SIGNAL ;
    ANTENNAMODEL OXIDE1 ;
    ANTENNAGATEAREA 0.4836 LAYER Metal1 ;
    PORT
      LAYER Metal1 ;
        RECT 2.2100 1.5500 2.5100 1.5700 ;
        RECT 1.8900 1.5700 2.5100 1.8300 ;
        RECT 2.2100 1.8300 2.5100 1.8500 ;
    END
  END A2
  PIN B1
    DIRECTION INPUT ;
    USE SIGNAL ;
    ANTENNAMODEL OXIDE1 ;
    ANTENNAGATEAREA 0.4836 LAYER Metal1 ;
    PORT
      LAYER Metal1 ;
        RECT 3.2500 1.5500 3.5500 1.8500 ;
    END
  END B1
  PIN B2
    DIRECTION INPUT ;
    USE SIGNAL ;
    ANTENNAMODEL OXIDE1 ;
    ANTENNAGATEAREA 0.4836 LAYER Metal1 ;
    PORT
      LAYER Metal1 ;
        RECT 4.8100 1.5500 5.1100 1.5700 ;
        RECT 4.3100 1.5700 5.1100 1.8300 ;
        RECT 4.8100 1.8300 5.1100 1.8500 ;
    END
  END B2
  PIN Y
    DIRECTION OUTPUT ;
    USE SIGNAL ;
    ANTENNAPARTIALMETALAREA 0.672 LAYER Metal1 ;
    ANTENNADIFFAREA 1.4508 LAYER Metal1 ;
    ANTENNADIFFAREA 1.4508 LAYER Metal2 ;
    PORT
      LAYER Metal2 ;
        RECT 0.9150 0.9300 3.5000 1.1300 ;
        RECT 3.3000 1.1300 3.5000 1.6000 ;
        RECT 3.3000 1.6000 4.0650 1.8000 ;
        RECT 3.3000 1.8000 3.5000 2.2400 ;
        RECT 0.9150 2.2400 3.8050 2.4400 ;
      LAYER Metal1 ;
        RECT 0.9300 0.7100 1.1900 0.8800 ;
        RECT 0.9100 0.8800 1.2100 1.1800 ;
        RECT 0.9300 1.1800 1.1900 1.3100 ;
        RECT 1.9700 0.7100 2.2300 0.8800 ;
        RECT 1.9500 0.8800 2.2500 1.1800 ;
        RECT 1.9700 1.1800 2.2300 1.3100 ;
        RECT 3.7700 1.5500 4.0700 1.8500 ;
        RECT 0.9300 2.0900 1.1900 2.1900 ;
        RECT 0.9100 2.1900 1.2100 2.4900 ;
        RECT 0.9300 2.4900 1.1900 2.6900 ;
        RECT 3.5300 2.0900 3.7900 2.1900 ;
        RECT 3.5100 2.1900 3.8100 2.4900 ;
        RECT 3.5300 2.4900 3.7900 2.6900 ;
      LAYER Via1 ;
        RECT 0.9650 0.9350 1.1550 1.1250 ;
        RECT 2.0050 0.9350 2.1950 1.1250 ;
        RECT 3.8250 1.6050 4.0150 1.7950 ;
        RECT 0.9650 2.2450 1.1550 2.4350 ;
        RECT 3.5650 2.2450 3.7550 2.4350 ;
    END
  END Y
  PIN VDD
    DIRECTION INOUT ;
    USE POWER ;
    SHAPE ABUTMENT ;
    PORT
      LAYER Metal1 ;
        RECT 0.0000 3.5600 5.7600 4.0000 ;
    END
  END VDD
  PIN VSS
    DIRECTION INOUT ;
    USE GROUND ;
    SHAPE ABUTMENT ;
    PORT
      LAYER Metal1 ;
        RECT 0.0000 -0.2200 5.7600 0.2200 ;
    END
  END VSS
  OBS
    LAYER Metal2 ;
      RECT 0.4400 0.8850 0.6400 1.6000 ;
      RECT 0.4400 1.6000 3.0250 1.8000 ;
    LAYER Metal1 ;
      RECT 0.3900 0.8800 0.6900 1.1800 ;
      RECT 1.4500 0.7100 1.7100 1.3100 ;
      RECT 1.5000 1.3100 1.6600 1.5550 ;
      RECT 1.4650 1.5550 1.6950 1.8450 ;
      RECT 2.8000 0.5400 4.7800 0.6600 ;
      RECT 2.8000 0.6600 4.8300 0.7000 ;
      RECT 2.8000 0.7000 2.9600 0.8300 ;
      RECT 3.5150 0.7000 3.8050 0.8300 ;
      RECT 2.4900 0.8300 2.9600 0.8800 ;
      RECT 2.4750 0.8800 2.9600 1.0400 ;
      RECT 2.4900 1.0400 2.9600 1.0900 ;
      RECT 3.5300 0.8300 3.7900 1.2600 ;
      RECT 4.5700 0.7000 4.8300 1.2600 ;
      RECT 2.8000 1.0900 2.9600 1.5550 ;
      RECT 2.7650 1.5550 2.9950 1.8450 ;
      RECT 0.2000 1.6200 0.3600 2.5000 ;
      RECT 0.2000 2.5000 0.6700 2.5500 ;
      RECT 2.5400 2.6050 2.7000 2.6200 ;
      RECT 0.2000 2.5500 0.6850 2.7100 ;
      RECT 0.2000 2.7100 0.6700 2.7600 ;
      RECT 2.4900 2.6200 2.7500 2.8800 ;
      RECT 0.2000 2.7600 0.3600 3.0800 ;
      RECT 1.4500 2.1100 1.7100 3.0800 ;
      RECT 2.5400 2.8800 2.7000 3.0800 ;
      RECT 0.2000 3.0800 2.7000 3.2400 ;
      RECT 3.0600 2.6050 3.2200 2.6200 ;
      RECT 5.4000 1.6200 5.5600 2.6200 ;
      RECT 5.0900 2.6200 5.5600 2.6700 ;
      RECT 4.8800 2.6700 5.5600 2.8300 ;
      RECT 3.0100 2.6200 3.2700 2.8800 ;
      RECT 4.8800 2.8300 5.3500 2.8800 ;
      RECT 4.0500 2.1100 4.3100 3.0500 ;
      RECT 3.0600 2.8800 3.2200 3.0800 ;
      RECT 4.0350 3.0500 4.3100 3.0800 ;
      RECT 4.8800 2.8800 5.0400 3.0800 ;
      RECT 3.0600 3.0800 5.0400 3.2400 ;
    LAYER Via1 ;
      RECT 0.4450 0.9350 0.6350 1.1250 ;
      RECT 1.4850 1.6050 1.6750 1.7950 ;
      RECT 2.7850 1.6050 2.9750 1.7950 ;
  END
END sg13g2_o22ai_2

MACRO sg13g2_o31ai_2
  CLASS CORE ;
  ORIGIN 0 0 ;
  FOREIGN sg13g2_o31ai_2 0 0 ;
  SIZE 5.7600 BY 3.7800 ;
  SYMMETRY X Y ;
  SITE CoreSite ;
  PIN A1
    DIRECTION INPUT ;
    USE SIGNAL ;
    ANTENNAMODEL OXIDE1 ;
    ANTENNAGATEAREA 0.4836 LAYER Metal1 ;
    PORT
      LAYER Metal1 ;
        RECT 0.6700 1.5700 1.2700 1.6050 ;
        RECT 0.6550 1.6050 1.2700 1.7950 ;
        RECT 0.6700 1.7950 1.2700 1.8300 ;
    END
  END A1
  PIN A2
    DIRECTION INPUT ;
    USE SIGNAL ;
    ANTENNAMODEL OXIDE1 ;
    ANTENNAGATEAREA 0.4836 LAYER Metal1 ;
    PORT
      LAYER Metal1 ;
        RECT 2.2100 1.5500 2.5100 1.5700 ;
        RECT 1.8900 1.5700 2.5100 1.8300 ;
        RECT 2.2100 1.8300 2.5100 1.8500 ;
    END
  END A2
  PIN A3
    DIRECTION INPUT ;
    USE SIGNAL ;
    ANTENNAMODEL OXIDE1 ;
    ANTENNAGATEAREA 0.4836 LAYER Metal1 ;
    PORT
      LAYER Metal1 ;
        RECT 3.2500 1.5500 3.5500 1.5700 ;
        RECT 3.2500 1.5700 3.8700 1.8300 ;
        RECT 3.2500 1.8300 3.5500 1.8500 ;
    END
  END A3
  PIN B1
    DIRECTION INPUT ;
    USE SIGNAL ;
    ANTENNAMODEL OXIDE1 ;
    ANTENNAGATEAREA 0.4836 LAYER Metal1 ;
    PORT
      LAYER Metal1 ;
        RECT 4.4900 1.5700 5.0900 1.6050 ;
        RECT 4.4900 1.6050 5.1050 1.7950 ;
        RECT 4.4900 1.7950 5.0900 1.8300 ;
    END
  END B1
  PIN Y
    DIRECTION OUTPUT ;
    USE SIGNAL ;
    ANTENNAPARTIALMETALAREA 0.762 LAYER Metal1 ;
    ANTENNADIFFAREA 1.7394 LAYER Metal1 ;
    ANTENNADIFFAREA 1.7394 LAYER Metal2 ;
    PORT
      LAYER Metal2 ;
        RECT 0.9150 0.9300 4.8000 1.1300 ;
        RECT 4.6000 1.1300 4.8000 1.6000 ;
        RECT 4.6000 1.6000 5.6250 1.8000 ;
        RECT 0.9600 2.1950 1.1600 3.0600 ;
        RECT 4.6000 1.8000 4.8000 3.0600 ;
        RECT 0.9600 3.0600 4.8000 3.2600 ;
      LAYER Metal1 ;
        RECT 0.9300 0.7100 1.1900 0.8800 ;
        RECT 0.9100 0.8800 1.2100 1.1800 ;
        RECT 0.9300 1.1800 1.1900 1.3100 ;
        RECT 1.9700 0.7100 2.2300 0.8800 ;
        RECT 1.9500 0.8800 2.2500 1.1800 ;
        RECT 1.9700 1.1800 2.2300 1.3100 ;
        RECT 3.5300 0.7100 3.7900 0.8800 ;
        RECT 3.5100 0.8800 3.8100 1.1800 ;
        RECT 3.5300 1.1800 3.7900 1.3100 ;
        RECT 5.3300 1.5500 5.6300 1.8500 ;
        RECT 0.9300 2.0900 1.1900 2.1900 ;
        RECT 0.9100 2.1900 1.2100 2.4900 ;
        RECT 0.9300 2.4900 1.1900 2.6900 ;
        RECT 4.5700 2.1100 4.8300 3.0500 ;
        RECT 4.6200 3.0500 4.8300 3.0800 ;
        RECT 5.1400 2.6700 5.3000 3.0800 ;
        RECT 4.6200 3.0800 5.3000 3.2400 ;
      LAYER Via1 ;
        RECT 0.9650 0.9350 1.1550 1.1250 ;
        RECT 2.0050 0.9350 2.1950 1.1250 ;
        RECT 3.5650 0.9350 3.7550 1.1250 ;
        RECT 5.3850 1.6050 5.5750 1.7950 ;
        RECT 0.9650 2.2450 1.1550 2.4350 ;
        RECT 4.6050 2.6550 4.7950 2.8450 ;
    END
  END Y
  PIN VDD
    DIRECTION INOUT ;
    USE POWER ;
    SHAPE ABUTMENT ;
    PORT
      LAYER Metal1 ;
        RECT 4.0500 2.2300 4.3100 3.5600 ;
        RECT 0.0000 3.5600 5.7600 4.0000 ;
    END
  END VDD
  PIN VSS
    DIRECTION INOUT ;
    USE GROUND ;
    SHAPE ABUTMENT ;
    PORT
      LAYER Metal1 ;
        RECT 0.0000 -0.2200 5.7600 0.2200 ;
    END
  END VSS
  OBS
    LAYER Metal2 ;
      RECT 0.1350 1.6000 4.3250 1.8000 ;
      RECT 1.4350 2.2400 2.7650 2.4400 ;
    LAYER Metal1 ;
      RECT 0.4100 0.8300 0.6700 0.8800 ;
      RECT 0.2000 0.8800 0.6850 1.0400 ;
      RECT 0.2000 1.0400 0.6700 1.0900 ;
      RECT 0.2000 1.0900 0.3600 1.5550 ;
      RECT 0.1650 1.5550 0.3950 1.8450 ;
      RECT 1.4500 0.7100 1.7100 1.3100 ;
      RECT 1.5000 1.3100 1.6600 1.5550 ;
      RECT 1.4650 1.5550 1.6950 1.8450 ;
      RECT 2.4900 0.8300 2.7500 0.8800 ;
      RECT 3.0100 0.8300 3.2700 0.8800 ;
      RECT 2.4750 0.8800 3.2850 1.0400 ;
      RECT 2.4900 1.0400 3.2700 1.0900 ;
      RECT 2.8000 1.0900 2.9600 1.5550 ;
      RECT 2.7650 1.5550 2.9950 1.8450 ;
      RECT 4.1000 0.5400 5.3000 0.6600 ;
      RECT 4.0500 0.6600 5.3000 0.7000 ;
      RECT 5.0900 0.7000 5.3000 0.8300 ;
      RECT 5.0900 0.8300 5.3500 1.0900 ;
      RECT 5.1400 1.0900 5.3000 1.1050 ;
      RECT 4.0500 0.7000 4.3100 1.2600 ;
      RECT 4.1000 1.2600 4.2600 1.5550 ;
      RECT 4.0650 1.5550 4.2950 1.8450 ;
      RECT 2.4700 2.1900 2.7700 2.4900 ;
      RECT 0.4600 2.6050 0.6200 2.6200 ;
      RECT 0.4100 2.6200 0.6700 2.8800 ;
      RECT 1.4500 2.1100 1.7100 3.0500 ;
      RECT 0.4600 2.8800 0.6200 3.0800 ;
      RECT 1.4500 3.0500 1.6600 3.0800 ;
      RECT 0.4600 3.0800 1.6600 3.2400 ;
      RECT 1.9700 2.1100 2.2300 3.0500 ;
      RECT 3.5300 2.1100 3.7900 3.0500 ;
      RECT 2.0200 3.0500 2.2300 3.0800 ;
      RECT 3.4800 3.0500 3.7400 3.0800 ;
      RECT 2.0200 3.0800 3.7400 3.2400 ;
    LAYER Via1 ;
      RECT 0.1850 1.6050 0.3750 1.7950 ;
      RECT 1.4850 1.6050 1.6750 1.7950 ;
      RECT 2.7850 1.6050 2.9750 1.7950 ;
      RECT 4.0850 1.6050 4.2750 1.7950 ;
      RECT 1.4850 2.2450 1.6750 2.4350 ;
      RECT 2.5250 2.2450 2.7150 2.4350 ;
  END
END sg13g2_o31ai_2

MACRO sg13g2_xnor2_2
  CLASS CORE ;
  ORIGIN 0 0 ;
  FOREIGN sg13g2_xnor2_2 0 0 ;
  SIZE 5.7600 BY 3.7800 ;
  SYMMETRY X Y ;
  SITE CoreSite ;
  PIN A
    DIRECTION INPUT ;
    USE SIGNAL ;
    ANTENNAMODEL OXIDE1 ;
    ANTENNAGATEAREA 0.676 LAYER Metal1 ;
    PORT
      LAYER Metal1 ;
        RECT 4.8100 1.5500 5.1100 1.6200 ;
        RECT 4.7400 1.6200 5.1100 1.7800 ;
        RECT 4.8100 1.7800 5.1100 1.8500 ;
    END
  END A
  PIN B
    DIRECTION INPUT ;
    USE SIGNAL ;
    ANTENNAMODEL OXIDE1 ;
    ANTENNAGATEAREA 0.676 LAYER Metal1 ;
    PORT
      LAYER Metal1 ;
        RECT 2.2300 1.5700 3.0100 1.6200 ;
        RECT 3.2700 1.4000 3.5300 1.6200 ;
        RECT 2.2150 1.6200 3.5450 1.7800 ;
        RECT 2.2300 1.7800 3.0100 1.8300 ;
        RECT 3.2700 1.7800 3.5300 2.0000 ;
    END
  END B
  PIN Y
    DIRECTION OUTPUT ;
    USE SIGNAL ;
    ANTENNAPARTIALMETALAREA 0.8951 LAYER Metal1 ;
    ANTENNADIFFAREA 1.4572 LAYER Metal1 ;
    ANTENNADIFFAREA 1.4572 LAYER Metal2 ;
    PORT
      LAYER Metal2 ;
        RECT 0.9150 0.9300 2.2000 1.1300 ;
        RECT 2.0000 1.1300 2.2000 2.2400 ;
        RECT 1.4350 2.2400 2.7650 2.4400 ;
      LAYER Metal1 ;
        RECT 0.9300 0.7100 1.1900 0.8800 ;
        RECT 0.9100 0.8800 1.2100 1.1800 ;
        RECT 0.9300 1.1800 1.1900 1.3100 ;
        RECT 2.4700 2.1900 2.7700 2.4900 ;
        RECT 0.2000 1.6200 0.3600 2.5000 ;
        RECT 0.2000 2.5000 0.6700 2.5500 ;
        RECT 0.2000 2.5500 0.6850 2.7100 ;
        RECT 0.2000 2.7100 0.6700 2.7600 ;
        RECT 1.4500 2.0900 1.7100 3.0300 ;
        RECT 0.2000 2.7600 0.3600 3.0800 ;
        RECT 1.4500 3.0300 1.6600 3.0800 ;
        RECT 0.2000 3.0800 1.6600 3.2400 ;
      LAYER Via1 ;
        RECT 0.9650 0.9350 1.1550 1.1250 ;
        RECT 1.4850 2.2450 1.6750 2.4350 ;
        RECT 2.5250 2.2450 2.7150 2.4350 ;
    END
  END Y
  PIN VDD
    DIRECTION INOUT ;
    USE POWER ;
    SHAPE ABUTMENT ;
    PORT
      LAYER Metal1 ;
        RECT 0.0000 3.5600 5.7600 4.0000 ;
    END
  END VDD
  PIN VSS
    DIRECTION INOUT ;
    USE GROUND ;
    SHAPE ABUTMENT ;
    PORT
      LAYER Metal1 ;
        RECT 0.0000 -0.2200 5.7600 0.2200 ;
    END
  END VSS
  OBS
    LAYER Metal2 ;
      RECT 0.4400 0.8850 0.6400 1.6000 ;
      RECT 0.4400 1.6000 1.7250 1.8000 ;
      RECT 2.5200 0.8850 2.7200 1.6000 ;
      RECT 2.5200 1.6000 4.5850 1.8000 ;
      RECT 2.9950 0.9300 5.0600 1.1300 ;
      RECT 4.8600 1.1300 5.0600 2.2400 ;
      RECT 3.0400 2.2400 5.0600 2.4400 ;
      RECT 0.9600 2.1950 1.1600 3.0600 ;
      RECT 3.0400 2.4400 3.2400 3.0600 ;
      RECT 0.9600 3.0600 3.2400 3.2600 ;
    LAYER Metal1 ;
      RECT 0.3900 0.8800 0.6900 1.1800 ;
      RECT 1.5000 0.5400 2.4400 0.6600 ;
      RECT 1.4500 0.6600 2.4400 0.7000 ;
      RECT 2.2800 0.7000 2.4400 0.9000 ;
      RECT 2.2800 0.9000 2.7500 0.9150 ;
      RECT 2.2800 0.9150 2.7650 1.1100 ;
      RECT 2.4750 1.1100 2.7650 1.1450 ;
      RECT 2.4900 1.1450 2.7500 1.1600 ;
      RECT 1.4500 0.7000 1.7100 1.2600 ;
      RECT 1.5000 1.2600 1.6600 1.5550 ;
      RECT 1.4650 1.5550 1.6950 1.8450 ;
      RECT 4.5700 0.6100 4.8300 0.8300 ;
      RECT 4.3600 0.8300 4.8450 0.9900 ;
      RECT 4.3600 0.9900 4.8300 1.2100 ;
      RECT 4.3600 1.2100 4.5200 1.5550 ;
      RECT 4.3250 1.5550 4.5550 1.8450 ;
      RECT 2.9900 0.8800 3.2900 1.1800 ;
      RECT 0.6700 1.5700 1.2700 1.6200 ;
      RECT 0.6550 1.6200 1.2700 1.7800 ;
      RECT 0.6700 1.7800 1.2700 1.8300 ;
      RECT 0.9800 1.8300 1.1400 2.1950 ;
      RECT 0.9450 2.1950 1.1750 2.4850 ;
      RECT 3.5450 2.1950 3.7750 2.5000 ;
      RECT 3.5300 2.5000 3.7900 2.7600 ;
      RECT 3.5800 2.7600 3.7400 2.7750 ;
      RECT 3.5300 0.6100 3.7900 0.8300 ;
      RECT 3.5150 0.8300 4.0000 0.9900 ;
      RECT 3.5300 0.9900 4.0000 1.2100 ;
      RECT 3.8400 1.2100 4.0000 1.7800 ;
      RECT 1.9700 2.1300 2.2300 3.0700 ;
      RECT 4.5700 2.1300 4.8300 3.0700 ;
      RECT 2.0200 3.0700 2.2800 3.0800 ;
      RECT 4.5200 3.0700 4.8450 3.0800 ;
      RECT 5.4000 1.6200 5.5600 3.0800 ;
      RECT 2.0200 3.0800 5.5600 3.2400 ;
    LAYER Via1 ;
      RECT 0.4450 0.9350 0.6350 1.1250 ;
      RECT 2.5250 0.9350 2.7150 1.1250 ;
      RECT 1.4850 1.6050 1.6750 1.7950 ;
      RECT 4.3450 1.6050 4.5350 1.7950 ;
      RECT 3.0450 0.9350 3.2350 1.1250 ;
      RECT 0.9650 2.2450 1.1550 2.4350 ;
      RECT 3.5650 2.2450 3.7550 2.4350 ;
  END
END sg13g2_xnor2_2

MACRO sg13g2_xnor2_4
  CLASS CORE ;
  ORIGIN 0 0 ;
  FOREIGN sg13g2_xnor2_4 0 0 ;
  SIZE 9.6000 BY 3.7800 ;
  SYMMETRY X Y ;
  SITE CoreSite ;
  PIN A
    DIRECTION INPUT ;
    USE SIGNAL ;
    ANTENNAMODEL OXIDE1 ;
    ANTENNAGATEAREA 1.1596 LAYER Metal1 ;
    PORT
      LAYER Metal1 ;
        RECT 5.4300 1.5500 5.7300 1.5700 ;
        RECT 4.9300 1.5700 5.7300 1.8300 ;
        RECT 5.4300 1.8300 5.7300 1.8500 ;
    END
  END A
  PIN B
    DIRECTION INPUT ;
    USE SIGNAL ;
    ANTENNAPARTIALMETALAREA 0.26605 LAYER Metal1 ;
    ANTENNAPARTIALCUTAREA 0.0722 LAYER Via1 ;
    ANTENNAMODEL OXIDE1 ;
    ANTENNAGATEAREA 1.1596 LAYER Metal1 ;
    ANTENNAGATEAREA 1.1596 LAYER Metal2 ;
    ANTENNAMAXAREACAR 1.479864 LAYER Metal2 ;
    ANTENNAMAXCUTCAR 0.062263 LAYER Via1 ;
    PORT
      LAYER Metal2 ;
        RECT 6.0000 1.6000 8.0650 1.8000 ;
        RECT 3.1400 2.1950 3.3400 3.0600 ;
        RECT 6.0000 1.8000 6.2000 3.0600 ;
        RECT 3.1400 3.0600 6.2000 3.2600 ;
      LAYER Metal1 ;
        RECT 8.0500 1.5700 8.8300 1.5850 ;
        RECT 7.7750 1.5850 8.8300 1.8150 ;
        RECT 8.0500 1.8150 8.8300 1.8300 ;
        RECT 3.0300 1.5700 3.6300 1.6200 ;
        RECT 3.0300 1.6200 3.6450 1.7800 ;
        RECT 3.0300 1.7800 3.6300 1.8300 ;
        RECT 3.1600 1.8300 3.3200 2.1950 ;
        RECT 3.1250 2.1950 3.3550 2.4850 ;
      LAYER Via1 ;
        RECT 7.8250 1.6050 8.0150 1.7950 ;
        RECT 3.1450 2.2450 3.3350 2.4350 ;
    END
  END B
  PIN Y
    DIRECTION OUTPUT ;
    USE SIGNAL ;
    ANTENNADIFFAREA 2.8194 LAYER Metal1 ;
    PORT
      LAYER Metal1 ;
        RECT 0.5100 0.7800 0.7700 0.8300 ;
        RECT 2.6400 0.8850 2.8000 0.9000 ;
        RECT 0.3000 0.8300 0.7850 0.9900 ;
        RECT 0.3000 0.9900 0.7700 1.0400 ;
        RECT 2.5900 0.9000 2.8500 1.1600 ;
        RECT 1.5500 0.7100 1.8100 1.3100 ;
        RECT 6.8000 2.6250 6.9600 2.6400 ;
        RECT 8.8800 2.6250 9.0400 2.6400 ;
        RECT 6.7500 2.6400 7.0100 2.9000 ;
        RECT 8.8300 2.6400 9.0900 2.9000 ;
        RECT 1.0300 2.1300 1.2900 3.0700 ;
        RECT 7.7900 2.1300 8.0500 3.0700 ;
        RECT 0.3000 1.0400 0.4600 3.0800 ;
        RECT 1.0150 3.0700 1.3050 3.0800 ;
        RECT 1.6000 1.3100 1.7600 3.0800 ;
        RECT 2.0700 2.1300 2.3300 3.0800 ;
        RECT 2.6400 1.1600 2.8000 3.0800 ;
        RECT 6.8000 2.9000 6.9600 3.0800 ;
        RECT 7.7750 3.0700 8.0650 3.0800 ;
        RECT 8.8800 2.9000 9.0400 3.0800 ;
        RECT 0.3000 3.0800 9.0400 3.2400 ;
    END
  END Y
  PIN VDD
    DIRECTION INOUT ;
    USE POWER ;
    SHAPE ABUTMENT ;
    PORT
      LAYER Metal1 ;
        RECT 0.0000 3.5600 9.6000 4.0000 ;
    END
  END VDD
  PIN VSS
    DIRECTION INOUT ;
    USE GROUND ;
    SHAPE ABUTMENT ;
    PORT
      LAYER Metal1 ;
        RECT 0.0000 -0.2200 9.6000 0.2200 ;
    END
  END VSS
  OBS
    LAYER Metal2 ;
      RECT 0.5400 0.9300 1.3050 1.1300 ;
      RECT 2.0550 1.6000 4.6850 1.8000 ;
      RECT 0.5400 1.1300 0.7400 2.2400 ;
      RECT 2.3600 1.8000 2.5600 2.2400 ;
      RECT 0.5400 2.2400 2.5600 2.4400 ;
      RECT 1.5800 0.9300 5.1600 1.1300 ;
      RECT 1.5800 1.1300 1.7800 1.6000 ;
      RECT 1.0150 1.6000 1.7800 1.8000 ;
      RECT 4.9600 1.1300 5.1600 2.2400 ;
      RECT 3.6150 2.2400 5.1600 2.4400 ;
      RECT 7.2550 2.2400 8.5850 2.4400 ;
    LAYER Metal1 ;
      RECT 3.6300 0.6100 3.8900 0.8300 ;
      RECT 3.6150 0.8300 4.1000 0.9900 ;
      RECT 3.6300 0.9900 4.1000 1.2100 ;
      RECT 3.9400 1.2100 4.1000 1.7800 ;
      RECT 1.0300 0.7100 1.2900 0.8800 ;
      RECT 1.0100 0.8800 1.3100 1.1800 ;
      RECT 1.0300 1.1800 1.2900 1.3100 ;
      RECT 2.0700 0.7100 2.3300 1.3100 ;
      RECT 2.1200 1.3100 2.2800 1.5550 ;
      RECT 2.0850 1.5550 2.3150 1.8450 ;
      RECT 4.6700 0.6100 4.9300 0.8300 ;
      RECT 5.7100 0.6100 5.9700 0.8300 ;
      RECT 7.2700 0.6100 7.5300 0.8300 ;
      RECT 8.3100 0.6100 8.5700 0.8300 ;
      RECT 4.4600 0.8300 8.5850 0.9900 ;
      RECT 4.4600 0.9900 4.9300 1.2100 ;
      RECT 5.7100 0.9900 5.9700 1.2100 ;
      RECT 7.2700 0.9900 7.5300 1.2100 ;
      RECT 8.3100 0.9900 8.5700 1.2100 ;
      RECT 4.4600 1.2100 4.6200 1.5550 ;
      RECT 4.4250 1.5550 4.6550 1.8450 ;
      RECT 3.0900 0.8800 3.3900 1.1800 ;
      RECT 0.7700 1.5700 1.3700 1.6200 ;
      RECT 0.7550 1.6200 1.3700 1.7800 ;
      RECT 0.7700 1.7800 1.3700 1.8300 ;
      RECT 3.6450 2.1950 3.8750 2.5000 ;
      RECT 3.6300 2.5000 3.8900 2.7600 ;
      RECT 3.6800 2.7600 3.8400 2.7750 ;
      RECT 6.2800 1.6200 7.4800 1.7800 ;
      RECT 7.3200 1.7800 7.4800 2.0900 ;
      RECT 4.6700 2.0900 4.9300 2.2600 ;
      RECT 5.7100 2.0900 5.9700 2.2600 ;
      RECT 6.2800 1.7800 6.4400 2.2600 ;
      RECT 4.6550 2.2600 6.4400 2.4200 ;
      RECT 4.6700 2.4200 4.9300 2.6900 ;
      RECT 5.7100 2.4200 5.9700 2.6900 ;
      RECT 7.2700 2.0900 7.5300 2.6900 ;
      RECT 8.3100 2.0900 8.5700 2.1900 ;
      RECT 8.2900 2.1900 8.5900 2.4900 ;
      RECT 8.3100 2.4900 8.5700 2.6900 ;
    LAYER Via1 ;
      RECT 1.0650 0.9350 1.2550 1.1250 ;
      RECT 2.1050 1.6050 2.2950 1.7950 ;
      RECT 4.4450 1.6050 4.6350 1.7950 ;
      RECT 3.1450 0.9350 3.3350 1.1250 ;
      RECT 1.0650 1.6050 1.2550 1.7950 ;
      RECT 3.6650 2.2450 3.8550 2.4350 ;
      RECT 7.3050 2.2450 7.4950 2.4350 ;
      RECT 8.3450 2.2450 8.5350 2.4350 ;
  END
END sg13g2_xnor2_4

MACRO sg13g2_xor2_2
  CLASS CORE ;
  ORIGIN 0 0 ;
  FOREIGN sg13g2_xor2_2 0 0 ;
  SIZE 6.2400 BY 3.7800 ;
  SYMMETRY X Y ;
  SITE CoreSite ;
  PIN A
    DIRECTION INPUT ;
    USE SIGNAL ;
    ANTENNAMODEL OXIDE1 ;
    ANTENNAGATEAREA 0.6851 LAYER Metal1 ;
    PORT
      LAYER Metal1 ;
        RECT 0.6300 1.5500 0.9300 1.6700 ;
        RECT 0.6300 1.6700 0.9700 1.8300 ;
        RECT 0.6300 1.8300 0.9300 1.8500 ;
    END
  END A
  PIN B
    DIRECTION INPUT ;
    USE SIGNAL ;
    ANTENNAMODEL OXIDE1 ;
    ANTENNAGATEAREA 0.6851 LAYER Metal1 ;
    PORT
      LAYER Metal1 ;
        RECT 2.2100 1.5700 2.9900 1.6200 ;
        RECT 3.2500 1.5700 3.8500 1.6200 ;
        RECT 2.1950 1.6200 3.8500 1.7800 ;
        RECT 2.2100 1.7800 2.9900 1.8300 ;
        RECT 3.2500 1.7800 3.8500 1.8300 ;
    END
  END B
  PIN X
    DIRECTION OUTPUT ;
    USE SIGNAL ;
    ANTENNAPARTIALMETALAREA 0.336 LAYER Metal1 ;
    ANTENNADIFFAREA 1.014 LAYER Metal1 ;
    ANTENNADIFFAREA 1.014 LAYER Metal2 ;
    PORT
      LAYER Metal2 ;
        RECT 3.4950 0.9300 5.3000 1.1300 ;
        RECT 5.1000 1.1300 5.3000 1.6000 ;
        RECT 5.1000 1.6000 5.6050 1.8000 ;
        RECT 5.1000 1.8000 5.3000 2.4850 ;
      LAYER Metal1 ;
        RECT 3.5100 0.7100 3.7700 0.8800 ;
        RECT 3.4900 0.8800 3.7900 1.1800 ;
        RECT 3.5100 1.1800 3.7700 1.3100 ;
        RECT 5.0700 0.6100 5.3300 0.7850 ;
        RECT 5.0550 0.7850 5.5400 0.9450 ;
        RECT 5.0700 0.9450 5.5400 1.2100 ;
        RECT 5.3800 1.2100 5.5400 1.5550 ;
        RECT 5.3450 1.5550 5.5750 1.8450 ;
        RECT 5.0700 2.0900 5.3300 2.1900 ;
        RECT 5.0500 2.1900 5.3500 2.4900 ;
        RECT 5.0700 2.4900 5.3300 2.6900 ;
      LAYER Via1 ;
        RECT 3.5450 0.9350 3.7350 1.1250 ;
        RECT 5.3650 1.6050 5.5550 1.7950 ;
        RECT 5.1050 2.2450 5.2950 2.4350 ;
    END
  END X
  PIN VDD
    DIRECTION INOUT ;
    USE POWER ;
    SHAPE ABUTMENT ;
    PORT
      LAYER Metal1 ;
        RECT 0.0000 3.5600 6.2400 4.0000 ;
    END
  END VDD
  PIN VSS
    DIRECTION INOUT ;
    USE GROUND ;
    SHAPE ABUTMENT ;
    PORT
      LAYER Metal1 ;
        RECT 0.0000 -0.2200 6.2400 0.2200 ;
    END
  END VSS
  OBS
    LAYER Metal2 ;
      RECT 1.1550 0.9300 3.2200 1.1300 ;
      RECT 3.0200 1.1300 3.2200 1.6000 ;
      RECT 3.0200 1.6000 4.3050 1.8000 ;
      RECT 1.6750 1.6000 2.4400 1.8000 ;
      RECT 2.2400 1.8000 2.4400 2.2400 ;
      RECT 4.5800 1.5550 4.7800 2.2400 ;
      RECT 2.2400 2.2400 4.7800 2.4400 ;
      RECT 1.2000 1.5550 1.4000 2.2400 ;
      RECT 1.2000 2.2400 1.7050 2.4400 ;
    LAYER Metal1 ;
      RECT 2.9900 0.9000 3.2500 0.9150 ;
      RECT 2.7150 0.9150 3.2500 0.9500 ;
      RECT 2.7150 0.9500 3.2650 1.1100 ;
      RECT 2.7150 1.1100 3.2500 1.1450 ;
      RECT 2.9900 1.1450 3.2500 1.1600 ;
      RECT 0.9100 0.7100 1.1700 0.9150 ;
      RECT 0.9100 0.9150 1.4450 0.9500 ;
      RECT 0.8950 0.9500 1.4450 1.1100 ;
      RECT 0.9100 1.1100 1.4450 1.1450 ;
      RECT 0.9100 1.1450 1.1700 1.3100 ;
      RECT 4.0800 0.8850 4.2400 0.9000 ;
      RECT 4.0300 0.9000 4.2900 1.1600 ;
      RECT 4.0800 1.1600 4.2400 1.5550 ;
      RECT 4.0450 1.5550 4.2750 1.8450 ;
      RECT 4.4700 1.5700 5.0700 1.6200 ;
      RECT 4.4700 1.6200 5.0850 1.7800 ;
      RECT 4.4700 1.7800 5.0700 1.8300 ;
      RECT 1.9500 0.7350 2.2100 0.7850 ;
      RECT 1.7400 0.7850 2.2250 0.9450 ;
      RECT 1.7400 0.9450 2.2100 0.9950 ;
      RECT 1.7400 0.9950 1.9000 1.5550 ;
      RECT 1.7050 1.5550 1.9350 1.8450 ;
      RECT 2.4500 2.1900 2.7500 2.4900 ;
      RECT 1.1500 1.5500 1.4500 1.8500 ;
      RECT 1.4150 2.2250 1.7050 2.2600 ;
      RECT 1.9500 2.2100 2.2100 2.2600 ;
      RECT 1.4150 2.2600 2.2250 2.4200 ;
      RECT 1.4150 2.4200 1.7050 2.4550 ;
      RECT 1.9500 2.4200 2.2100 2.8100 ;
      RECT 4.6000 2.6050 4.7600 2.6200 ;
      RECT 5.6400 2.6050 5.8000 2.6200 ;
      RECT 4.5500 2.6200 4.8100 2.8800 ;
      RECT 5.5900 2.6200 5.8500 2.8800 ;
      RECT 0.9100 2.1100 1.1700 3.0500 ;
      RECT 3.5100 2.1100 3.7700 3.0500 ;
      RECT 0.1800 1.6200 0.3400 3.0800 ;
      RECT 0.8600 3.0500 1.1700 3.0800 ;
      RECT 3.4950 3.0500 3.7850 3.0800 ;
      RECT 4.6000 2.8800 4.7600 3.0800 ;
      RECT 5.6400 2.8800 5.8000 3.0800 ;
      RECT 0.1800 3.0800 5.8000 3.2400 ;
    LAYER Via1 ;
      RECT 1.2050 0.9350 1.3950 1.1250 ;
      RECT 2.7650 0.9350 2.9550 1.1250 ;
      RECT 4.0650 1.6050 4.2550 1.7950 ;
      RECT 1.7250 1.6050 1.9150 1.7950 ;
      RECT 4.5850 1.6050 4.7750 1.7950 ;
      RECT 2.5050 2.2450 2.6950 2.4350 ;
      RECT 1.2050 1.6050 1.3950 1.7950 ;
      RECT 1.4650 2.2450 1.6550 2.4350 ;
  END
END sg13g2_xor2_2

END LIBRARY
